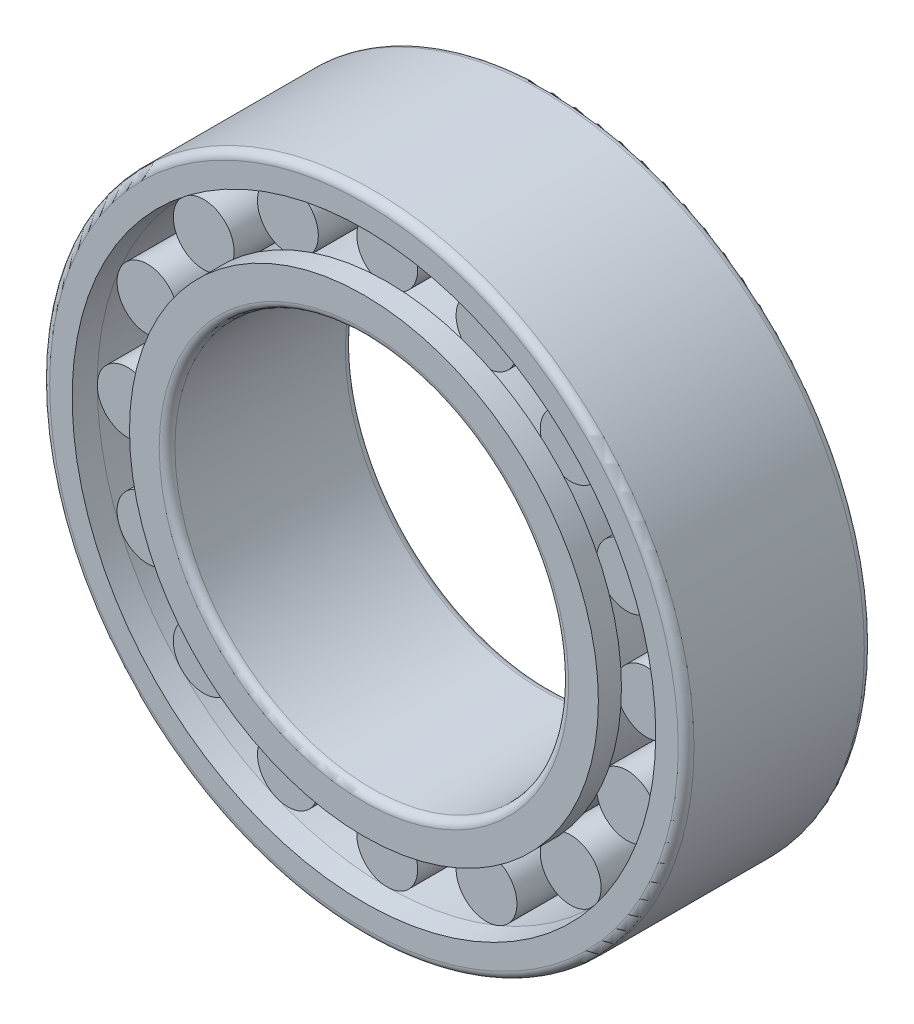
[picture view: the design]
ISO-10303-21;
HEADER;
FILE_DESCRIPTION(('STEP AP214'),'2;1');
FILE_NAME('part.step','',(''),(''),'','','');
FILE_SCHEMA(('AUTOMOTIVE_DESIGN { 1 0 10303 214 1 1 1 1 }'));
ENDSEC;
DATA;
#1=APPLICATION_CONTEXT('core data for automotive mechanical design processes');
#2=APPLICATION_PROTOCOL_DEFINITION('international standard','automotive_design',2000,#1);
#3=PRODUCT_CONTEXT('',#1,'mechanical');
#4=PRODUCT('Part','Part','',(#3));
#5=PRODUCT_RELATED_PRODUCT_CATEGORY('part','',(#4));
#6=PRODUCT_DEFINITION_FORMATION('','',#4);
#7=PRODUCT_DEFINITION_CONTEXT('part definition',#1,'design');
#8=PRODUCT_DEFINITION('design','',#6,#7);
#9=PRODUCT_DEFINITION_SHAPE('','',#8);
#10=(LENGTH_UNIT() NAMED_UNIT(*) SI_UNIT(.MILLI.,.METRE.));
#11=(NAMED_UNIT(*) PLANE_ANGLE_UNIT() SI_UNIT($,.RADIAN.));
#12=(NAMED_UNIT(*) SI_UNIT($,.STERADIAN.) SOLID_ANGLE_UNIT());
#13=UNCERTAINTY_MEASURE_WITH_UNIT(LENGTH_MEASURE(1.E-05),#10,'distance_accuracy_value','');
#14=(GEOMETRIC_REPRESENTATION_CONTEXT(3) GLOBAL_UNCERTAINTY_ASSIGNED_CONTEXT((#13)) GLOBAL_UNIT_ASSIGNED_CONTEXT((#10,
#11,#12)) REPRESENTATION_CONTEXT('',''));
#15=CARTESIAN_POINT('',(0.,0.,0.));
#16=DIRECTION('',(0.,0.,1.));
#17=DIRECTION('',(1.,0.,0.));
#18=AXIS2_PLACEMENT_3D('',#15,#16,#17);
#19=CARTESIAN_POINT('',(0.,0.,50.3916163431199));
#20=DIRECTION('',(0.,0.,1.));
#21=DIRECTION('',(1.,0.,0.));
#22=AXIS2_PLACEMENT_3D('',#19,#20,#21);
#23=CYLINDRICAL_SURFACE('',#22,40.48);
#24=DIRECTION('',(0.,0.,1.));
#25=VECTOR('',#24,1.);
#26=CARTESIAN_POINT('',(-15.8921876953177,37.2299445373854,5.52499999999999));
#27=LINE('',#26,#25);
#28=CARTESIAN_POINT('',(-15.8921876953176,37.2299445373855,9.74999999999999));
#29=VERTEX_POINT('',#28);
#30=CARTESIAN_POINT('',(-15.8921876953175,37.2299445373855,1.29999999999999));
#31=VERTEX_POINT('',#30);
#32=EDGE_CURVE('E860',#29,#31,#27,.F.);
#33=ORIENTED_EDGE('',*,*,#32,.F.);
#34=CARTESIAN_POINT('',(0.,0.,9.74999999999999));
#35=DIRECTION('',(0.,0.,-1.));
#36=DIRECTION('',(-1.,0.,0.));
#37=AXIS2_PLACEMENT_3D('',#34,#35,#36);
#38=CIRCLE('',#37,40.48);
#39=CARTESIAN_POINT('',(-15.0880725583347,37.5630199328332,9.74999999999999));
#40=VERTEX_POINT('',#39);
#41=EDGE_CURVE('E862',#40,#29,#38,.F.);
#42=ORIENTED_EDGE('',*,*,#41,.F.);
#43=DIRECTION('',(0.,0.,1.));
#44=VECTOR('',#43,1.);
#45=CARTESIAN_POINT('',(-15.0880725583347,37.5630199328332,5.52499999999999));
#46=LINE('',#45,#44);
#47=CARTESIAN_POINT('',(-15.0880725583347,37.5630199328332,1.29999999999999));
#48=VERTEX_POINT('',#47);
#49=EDGE_CURVE('E858',#48,#40,#46,.T.);
#50=ORIENTED_EDGE('',*,*,#49,.F.);
#51=CARTESIAN_POINT('',(0.,0.,1.29999999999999));
#52=DIRECTION('',(0.,0.,1.));
#53=DIRECTION('',(1.,0.,0.));
#54=AXIS2_PLACEMENT_3D('',#51,#52,#53);
#55=CIRCLE('',#54,40.48);
#56=EDGE_CURVE('E865',#31,#48,#55,.F.);
#57=ORIENTED_EDGE('',*,*,#56,.F.);
#58=EDGE_LOOP('',(#33,#42,#50,#57));
#59=FACE_BOUND('',#58,.T.);
#60=DIRECTION('',(0.,0.,1.));
#61=VECTOR('',#60,1.);
#62=CARTESIAN_POINT('',(-28.9297499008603,28.3143068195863,5.52499999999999));
#63=LINE('',#62,#61);
#64=CARTESIAN_POINT('',(-28.9297499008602,28.3143068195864,9.74999999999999));
#65=VERTEX_POINT('',#64);
#66=CARTESIAN_POINT('',(-28.9297499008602,28.3143068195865,1.29999999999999));
#67=VERTEX_POINT('',#66);
#68=EDGE_CURVE('E898',#65,#67,#63,.F.);
#69=ORIENTED_EDGE('',*,*,#68,.F.);
#70=CARTESIAN_POINT('',(0.,0.,9.74999999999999));
#71=DIRECTION('',(0.,0.,-1.));
#72=DIRECTION('',(-1.,0.,0.));
#73=AXIS2_PLACEMENT_3D('',#70,#71,#72);
#74=CIRCLE('',#73,40.48);
#75=CARTESIAN_POINT('',(-28.3143068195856,28.929749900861,9.74999999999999));
#76=VERTEX_POINT('',#75);
#77=EDGE_CURVE('E901',#76,#65,#74,.F.);
#78=ORIENTED_EDGE('',*,*,#77,.F.);
#79=DIRECTION('',(0.,0.,1.));
#80=VECTOR('',#79,1.);
#81=CARTESIAN_POINT('',(-28.3143068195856,28.929749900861,5.52499999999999));
#82=LINE('',#81,#80);
#83=CARTESIAN_POINT('',(-28.3143068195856,28.929749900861,1.29999999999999));
#84=VERTEX_POINT('',#83);
#85=EDGE_CURVE('E899',#84,#76,#82,.T.);
#86=ORIENTED_EDGE('',*,*,#85,.F.);
#87=CARTESIAN_POINT('',(0.,0.,1.29999999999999));
#88=DIRECTION('',(0.,0.,1.));
#89=DIRECTION('',(1.,0.,0.));
#90=AXIS2_PLACEMENT_3D('',#87,#88,#89);
#91=CIRCLE('',#90,40.48);
#92=EDGE_CURVE('E904',#67,#84,#91,.F.);
#93=ORIENTED_EDGE('',*,*,#92,.F.);
#94=EDGE_LOOP('',(#69,#78,#86,#93));
#95=FACE_BOUND('',#94,.T.);
#96=DIRECTION('',(0.,0.,1.));
#97=VECTOR('',#96,1.);
#98=CARTESIAN_POINT('',(-37.5630199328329,15.0880725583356,5.52499999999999));
#99=LINE('',#98,#97);
#100=CARTESIAN_POINT('',(-37.5630199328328,15.0880725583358,9.74999999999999));
#101=VERTEX_POINT('',#100);
#102=CARTESIAN_POINT('',(-37.5630199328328,15.0880725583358,1.29999999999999));
#103=VERTEX_POINT('',#102);
#104=EDGE_CURVE('E939',#101,#103,#99,.F.);
#105=ORIENTED_EDGE('',*,*,#104,.F.);
#106=CARTESIAN_POINT('',(0.,0.,9.74999999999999));
#107=DIRECTION('',(0.,0.,-1.));
#108=DIRECTION('',(-1.,0.,0.));
#109=AXIS2_PLACEMENT_3D('',#106,#107,#108);
#110=CIRCLE('',#109,40.48);
#111=CARTESIAN_POINT('',(-37.229944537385,15.8921876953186,9.74999999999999));
#112=VERTEX_POINT('',#111);
#113=EDGE_CURVE('E944',#112,#101,#110,.F.);
#114=ORIENTED_EDGE('',*,*,#113,.F.);
#115=DIRECTION('',(0.,0.,1.));
#116=VECTOR('',#115,1.);
#117=CARTESIAN_POINT('',(-37.229944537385,15.8921876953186,5.52499999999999));
#118=LINE('',#117,#116);
#119=CARTESIAN_POINT('',(-37.229944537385,15.8921876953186,1.29999999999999));
#120=VERTEX_POINT('',#119);
#121=EDGE_CURVE('E938',#120,#112,#118,.T.);
#122=ORIENTED_EDGE('',*,*,#121,.F.);
#123=CARTESIAN_POINT('',(0.,0.,1.29999999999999));
#124=DIRECTION('',(0.,0.,1.));
#125=DIRECTION('',(1.,0.,0.));
#126=AXIS2_PLACEMENT_3D('',#123,#124,#125);
#127=CIRCLE('',#126,40.48);
#128=EDGE_CURVE('E945',#103,#120,#127,.F.);
#129=ORIENTED_EDGE('',*,*,#128,.F.);
#130=EDGE_LOOP('',(#105,#114,#122,#129));
#131=FACE_BOUND('',#130,.T.);
#132=DIRECTION('',(0.,0.,1.));
#133=VECTOR('',#132,1.);
#134=CARTESIAN_POINT('',(-40.4776606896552,-0.435183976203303,5.52499999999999));
#135=LINE('',#134,#133);
#136=CARTESIAN_POINT('',(-40.4776606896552,-0.435183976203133,9.74999999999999));
#137=VERTEX_POINT('',#136);
#138=CARTESIAN_POINT('',(-40.4776606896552,-0.435183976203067,1.29999999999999));
#139=VERTEX_POINT('',#138);
#140=EDGE_CURVE('E980',#137,#139,#135,.F.);
#141=ORIENTED_EDGE('',*,*,#140,.F.);
#142=CARTESIAN_POINT('',(0.,0.,9.74999999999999));
#143=DIRECTION('',(0.,0.,-1.));
#144=DIRECTION('',(-1.,0.,0.));
#145=AXIS2_PLACEMENT_3D('',#142,#143,#144);
#146=CIRCLE('',#145,40.48);
#147=CARTESIAN_POINT('',(-40.4776606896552,0.435183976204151,9.74999999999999));
#148=VERTEX_POINT('',#147);
#149=EDGE_CURVE('E983',#148,#137,#146,.F.);
#150=ORIENTED_EDGE('',*,*,#149,.F.);
#151=DIRECTION('',(0.,0.,1.));
#152=VECTOR('',#151,1.);
#153=CARTESIAN_POINT('',(-40.4776606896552,0.43518397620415,5.52499999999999));
#154=LINE('',#153,#152);
#155=CARTESIAN_POINT('',(-40.4776606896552,0.43518397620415,1.29999999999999));
#156=VERTEX_POINT('',#155);
#157=EDGE_CURVE('E978',#156,#148,#154,.T.);
#158=ORIENTED_EDGE('',*,*,#157,.F.);
#159=CARTESIAN_POINT('',(0.,0.,1.29999999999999));
#160=DIRECTION('',(0.,0.,1.));
#161=DIRECTION('',(1.,0.,0.));
#162=AXIS2_PLACEMENT_3D('',#159,#160,#161);
#163=CIRCLE('',#162,40.48);
#164=EDGE_CURVE('E985',#139,#156,#163,.F.);
#165=ORIENTED_EDGE('',*,*,#164,.F.);
#166=EDGE_LOOP('',(#141,#150,#158,#165));
#167=FACE_BOUND('',#166,.T.);
#168=DIRECTION('',(0.,0.,1.));
#169=VECTOR('',#168,1.);
#170=CARTESIAN_POINT('',(-37.2299445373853,-15.8921876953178,5.52499999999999));
#171=LINE('',#170,#169);
#172=CARTESIAN_POINT('',(-37.2299445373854,-15.8921876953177,9.74999999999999));
#173=VERTEX_POINT('',#172);
#174=CARTESIAN_POINT('',(-37.2299445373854,-15.8921876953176,1.29999999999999));
#175=VERTEX_POINT('',#174);
#176=EDGE_CURVE('E1017',#173,#175,#171,.F.);
#177=ORIENTED_EDGE('',*,*,#176,.F.);
#178=CARTESIAN_POINT('',(0.,0.,9.74999999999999));
#179=DIRECTION('',(0.,0.,-1.));
#180=DIRECTION('',(-1.,0.,0.));
#181=AXIS2_PLACEMENT_3D('',#178,#179,#180);
#182=CIRCLE('',#181,40.48);
#183=CARTESIAN_POINT('',(-37.5630199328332,-15.0880725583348,9.74999999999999));
#184=VERTEX_POINT('',#183);
#185=EDGE_CURVE('E1024',#184,#173,#182,.F.);
#186=ORIENTED_EDGE('',*,*,#185,.F.);
#187=DIRECTION('',(0.,0.,1.));
#188=VECTOR('',#187,1.);
#189=CARTESIAN_POINT('',(-37.5630199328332,-15.0880725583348,5.52499999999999));
#190=LINE('',#189,#188);
#191=CARTESIAN_POINT('',(-37.5630199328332,-15.0880725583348,1.29999999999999));
#192=VERTEX_POINT('',#191);
#193=EDGE_CURVE('E1016',#192,#184,#190,.T.);
#194=ORIENTED_EDGE('',*,*,#193,.F.);
#195=CARTESIAN_POINT('',(0.,0.,1.29999999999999));
#196=DIRECTION('',(0.,0.,1.));
#197=DIRECTION('',(1.,0.,0.));
#198=AXIS2_PLACEMENT_3D('',#195,#196,#197);
#199=CIRCLE('',#198,40.48);
#200=EDGE_CURVE('E1025',#175,#192,#199,.F.);
#201=ORIENTED_EDGE('',*,*,#200,.F.);
#202=EDGE_LOOP('',(#177,#186,#194,#201));
#203=FACE_BOUND('',#202,.T.);
#204=DIRECTION('',(0.,0.,1.));
#205=VECTOR('',#204,1.);
#206=CARTESIAN_POINT('',(-28.3143068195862,-28.9297499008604,5.52499999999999));
#207=LINE('',#206,#205);
#208=CARTESIAN_POINT('',(-28.3143068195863,-28.9297499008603,9.74999999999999));
#209=VERTEX_POINT('',#208);
#210=CARTESIAN_POINT('',(-28.3143068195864,-28.9297499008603,1.29999999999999));
#211=VERTEX_POINT('',#210);
#212=EDGE_CURVE('E1059',#209,#211,#207,.F.);
#213=ORIENTED_EDGE('',*,*,#212,.F.);
#214=CARTESIAN_POINT('',(0.,0.,9.74999999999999));
#215=DIRECTION('',(0.,0.,-1.));
#216=DIRECTION('',(-1.,0.,0.));
#217=AXIS2_PLACEMENT_3D('',#214,#215,#216);
#218=CIRCLE('',#217,40.48);
#219=CARTESIAN_POINT('',(-28.9297499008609,-28.3143068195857,9.74999999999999));
#220=VERTEX_POINT('',#219);
#221=EDGE_CURVE('E1063',#220,#209,#218,.F.);
#222=ORIENTED_EDGE('',*,*,#221,.F.);
#223=DIRECTION('',(0.,0.,1.));
#224=VECTOR('',#223,1.);
#225=CARTESIAN_POINT('',(-28.9297499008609,-28.3143068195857,5.52499999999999));
#226=LINE('',#225,#224);
#227=CARTESIAN_POINT('',(-28.9297499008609,-28.3143068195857,1.29999999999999));
#228=VERTEX_POINT('',#227);
#229=EDGE_CURVE('E1057',#228,#220,#226,.T.);
#230=ORIENTED_EDGE('',*,*,#229,.F.);
#231=CARTESIAN_POINT('',(0.,0.,1.29999999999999));
#232=DIRECTION('',(0.,0.,1.));
#233=DIRECTION('',(1.,0.,0.));
#234=AXIS2_PLACEMENT_3D('',#231,#232,#233);
#235=CIRCLE('',#234,40.48);
#236=EDGE_CURVE('E1065',#211,#228,#235,.F.);
#237=ORIENTED_EDGE('',*,*,#236,.F.);
#238=EDGE_LOOP('',(#213,#222,#230,#237));
#239=FACE_BOUND('',#238,.T.);
#240=DIRECTION('',(0.,0.,1.));
#241=VECTOR('',#240,1.);
#242=CARTESIAN_POINT('',(-15.0880725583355,-37.5630199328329,5.52499999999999));
#243=LINE('',#242,#241);
#244=CARTESIAN_POINT('',(-15.0880725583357,-37.5630199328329,9.74999999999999));
#245=VERTEX_POINT('',#244);
#246=CARTESIAN_POINT('',(-15.0880725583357,-37.5630199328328,1.29999999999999));
#247=VERTEX_POINT('',#246);
#248=EDGE_CURVE('E1097',#245,#247,#243,.F.);
#249=ORIENTED_EDGE('',*,*,#248,.F.);
#250=CARTESIAN_POINT('',(0.,0.,9.74999999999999));
#251=DIRECTION('',(0.,0.,-1.));
#252=DIRECTION('',(-1.,0.,0.));
#253=AXIS2_PLACEMENT_3D('',#250,#251,#252);
#254=CIRCLE('',#253,40.48);
#255=CARTESIAN_POINT('',(-15.8921876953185,-37.229944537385,9.74999999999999));
#256=VERTEX_POINT('',#255);
#257=EDGE_CURVE('E1104',#256,#245,#254,.F.);
#258=ORIENTED_EDGE('',*,*,#257,.F.);
#259=DIRECTION('',(0.,0.,1.));
#260=VECTOR('',#259,1.);
#261=CARTESIAN_POINT('',(-15.8921876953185,-37.229944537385,5.52499999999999));
#262=LINE('',#261,#260);
#263=CARTESIAN_POINT('',(-15.8921876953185,-37.229944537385,1.29999999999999));
#264=VERTEX_POINT('',#263);
#265=EDGE_CURVE('E1096',#264,#256,#262,.T.);
#266=ORIENTED_EDGE('',*,*,#265,.F.);
#267=CARTESIAN_POINT('',(0.,0.,1.29999999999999));
#268=DIRECTION('',(0.,0.,1.));
#269=DIRECTION('',(1.,0.,0.));
#270=AXIS2_PLACEMENT_3D('',#267,#268,#269);
#271=CIRCLE('',#270,40.48);
#272=EDGE_CURVE('E1105',#247,#264,#271,.F.);
#273=ORIENTED_EDGE('',*,*,#272,.F.);
#274=EDGE_LOOP('',(#249,#258,#266,#273));
#275=FACE_BOUND('',#274,.T.);
#276=DIRECTION('',(0.,0.,1.));
#277=VECTOR('',#276,1.);
#278=CARTESIAN_POINT('',(0.435183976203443,-40.4776606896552,5.52499999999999));
#279=LINE('',#278,#277);
#280=CARTESIAN_POINT('',(0.435183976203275,-40.4776606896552,9.74999999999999));
#281=VERTEX_POINT('',#280);
#282=CARTESIAN_POINT('',(0.435183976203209,-40.4776606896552,1.29999999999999));
#283=VERTEX_POINT('',#282);
#284=EDGE_CURVE('E1136',#281,#283,#279,.F.);
#285=ORIENTED_EDGE('',*,*,#284,.F.);
#286=CARTESIAN_POINT('',(0.,0.,9.74999999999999));
#287=DIRECTION('',(0.,0.,-1.));
#288=DIRECTION('',(-1.,0.,0.));
#289=AXIS2_PLACEMENT_3D('',#286,#287,#288);
#290=CIRCLE('',#289,40.48);
#291=CARTESIAN_POINT('',(-0.43518397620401,-40.4776606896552,9.74999999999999));
#292=VERTEX_POINT('',#291);
#293=EDGE_CURVE('E1142',#292,#281,#290,.F.);
#294=ORIENTED_EDGE('',*,*,#293,.F.);
#295=DIRECTION('',(0.,0.,1.));
#296=VECTOR('',#295,1.);
#297=CARTESIAN_POINT('',(-0.435183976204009,-40.4776606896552,5.52499999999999));
#298=LINE('',#297,#296);
#299=CARTESIAN_POINT('',(-0.435183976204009,-40.4776606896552,1.29999999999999));
#300=VERTEX_POINT('',#299);
#301=EDGE_CURVE('E1137',#300,#292,#298,.T.);
#302=ORIENTED_EDGE('',*,*,#301,.F.);
#303=CARTESIAN_POINT('',(0.,0.,1.29999999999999));
#304=DIRECTION('',(0.,0.,1.));
#305=DIRECTION('',(1.,0.,0.));
#306=AXIS2_PLACEMENT_3D('',#303,#304,#305);
#307=CIRCLE('',#306,40.48);
#308=EDGE_CURVE('E1141',#283,#300,#307,.F.);
#309=ORIENTED_EDGE('',*,*,#308,.F.);
#310=EDGE_LOOP('',(#285,#294,#302,#309));
#311=FACE_BOUND('',#310,.T.);
#312=DIRECTION('',(0.,0.,1.));
#313=VECTOR('',#312,1.);
#314=CARTESIAN_POINT('',(15.892187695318,-37.2299445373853,5.52499999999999));
#315=LINE('',#314,#313);
#316=CARTESIAN_POINT('',(15.8921876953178,-37.2299445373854,9.74999999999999));
#317=VERTEX_POINT('',#316);
#318=CARTESIAN_POINT('',(15.8921876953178,-37.2299445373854,1.29999999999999));
#319=VERTEX_POINT('',#318);
#320=EDGE_CURVE('E1178',#317,#319,#315,.F.);
#321=ORIENTED_EDGE('',*,*,#320,.F.);
#322=CARTESIAN_POINT('',(0.,0.,9.74999999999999));
#323=DIRECTION('',(0.,0.,-1.));
#324=DIRECTION('',(-1.,0.,0.));
#325=AXIS2_PLACEMENT_3D('',#322,#323,#324);
#326=CIRCLE('',#325,40.48);
#327=CARTESIAN_POINT('',(15.088072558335,-37.5630199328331,9.74999999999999));
#328=VERTEX_POINT('',#327);
#329=EDGE_CURVE('E1183',#328,#317,#326,.F.);
#330=ORIENTED_EDGE('',*,*,#329,.F.);
#331=DIRECTION('',(0.,0.,1.));
#332=VECTOR('',#331,1.);
#333=CARTESIAN_POINT('',(15.088072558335,-37.5630199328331,5.52499999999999));
#334=LINE('',#333,#332);
#335=CARTESIAN_POINT('',(15.088072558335,-37.5630199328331,1.29999999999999));
#336=VERTEX_POINT('',#335);
#337=EDGE_CURVE('E1176',#336,#328,#334,.T.);
#338=ORIENTED_EDGE('',*,*,#337,.F.);
#339=CARTESIAN_POINT('',(0.,0.,1.29999999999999));
#340=DIRECTION('',(0.,0.,1.));
#341=DIRECTION('',(1.,0.,0.));
#342=AXIS2_PLACEMENT_3D('',#339,#340,#341);
#343=CIRCLE('',#342,40.48);
#344=EDGE_CURVE('E1185',#319,#336,#343,.F.);
#345=ORIENTED_EDGE('',*,*,#344,.F.);
#346=EDGE_LOOP('',(#321,#330,#338,#345));
#347=FACE_BOUND('',#346,.T.);
#348=DIRECTION('',(0.,0.,1.));
#349=VECTOR('',#348,1.);
#350=CARTESIAN_POINT('',(28.9297499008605,-28.3143068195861,5.52499999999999));
#351=LINE('',#350,#349);
#352=CARTESIAN_POINT('',(28.9297499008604,-28.3143068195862,9.74999999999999));
#353=VERTEX_POINT('',#352);
#354=CARTESIAN_POINT('',(28.9297499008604,-28.3143068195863,1.29999999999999));
#355=VERTEX_POINT('',#354);
#356=EDGE_CURVE('E1218',#353,#355,#351,.F.);
#357=ORIENTED_EDGE('',*,*,#356,.F.);
#358=CARTESIAN_POINT('',(0.,0.,9.74999999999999));
#359=DIRECTION('',(0.,0.,-1.));
#360=DIRECTION('',(-1.,0.,0.));
#361=AXIS2_PLACEMENT_3D('',#358,#359,#360);
#362=CIRCLE('',#361,40.48);
#363=CARTESIAN_POINT('',(28.3143068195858,-28.9297499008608,9.74999999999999));
#364=VERTEX_POINT('',#363);
#365=EDGE_CURVE('E1222',#364,#353,#362,.F.);
#366=ORIENTED_EDGE('',*,*,#365,.F.);
#367=DIRECTION('',(0.,0.,1.));
#368=VECTOR('',#367,1.);
#369=CARTESIAN_POINT('',(28.3143068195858,-28.9297499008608,5.52499999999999));
#370=LINE('',#369,#368);
#371=CARTESIAN_POINT('',(28.3143068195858,-28.9297499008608,1.29999999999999));
#372=VERTEX_POINT('',#371);
#373=EDGE_CURVE('E1219',#372,#364,#370,.T.);
#374=ORIENTED_EDGE('',*,*,#373,.F.);
#375=CARTESIAN_POINT('',(0.,0.,1.29999999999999));
#376=DIRECTION('',(0.,0.,1.));
#377=DIRECTION('',(1.,0.,0.));
#378=AXIS2_PLACEMENT_3D('',#375,#376,#377);
#379=CIRCLE('',#378,40.48);
#380=EDGE_CURVE('E1221',#355,#372,#379,.F.);
#381=ORIENTED_EDGE('',*,*,#380,.F.);
#382=EDGE_LOOP('',(#357,#366,#374,#381));
#383=FACE_BOUND('',#382,.T.);
#384=DIRECTION('',(0.,0.,1.));
#385=VECTOR('',#384,1.);
#386=CARTESIAN_POINT('',(37.563019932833,-15.0880725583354,5.52499999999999));
#387=LINE('',#386,#385);
#388=CARTESIAN_POINT('',(37.563019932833,-15.0880725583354,9.74999999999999));
#389=VERTEX_POINT('',#388);
#390=CARTESIAN_POINT('',(37.5630199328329,-15.0880725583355,1.29999999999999));
#391=VERTEX_POINT('',#390);
#392=EDGE_CURVE('E1256',#389,#391,#387,.F.);
#393=ORIENTED_EDGE('',*,*,#392,.F.);
#394=CARTESIAN_POINT('',(0.,0.,9.74999999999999));
#395=DIRECTION('',(0.,0.,-1.));
#396=DIRECTION('',(-1.,0.,0.));
#397=AXIS2_PLACEMENT_3D('',#394,#395,#396);
#398=CIRCLE('',#397,40.48);
#399=CARTESIAN_POINT('',(37.2299445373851,-15.8921876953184,9.74999999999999));
#400=VERTEX_POINT('',#399);
#401=EDGE_CURVE('E1263',#400,#389,#398,.F.);
#402=ORIENTED_EDGE('',*,*,#401,.F.);
#403=DIRECTION('',(0.,0.,1.));
#404=VECTOR('',#403,1.);
#405=CARTESIAN_POINT('',(37.2299445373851,-15.8921876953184,5.52499999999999));
#406=LINE('',#405,#404);
#407=CARTESIAN_POINT('',(37.2299445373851,-15.8921876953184,1.29999999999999));
#408=VERTEX_POINT('',#407);
#409=EDGE_CURVE('E1257',#408,#400,#406,.T.);
#410=ORIENTED_EDGE('',*,*,#409,.F.);
#411=CARTESIAN_POINT('',(0.,0.,1.29999999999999));
#412=DIRECTION('',(0.,0.,1.));
#413=DIRECTION('',(1.,0.,0.));
#414=AXIS2_PLACEMENT_3D('',#411,#412,#413);
#415=CIRCLE('',#414,40.48);
#416=EDGE_CURVE('E1265',#391,#408,#415,.F.);
#417=ORIENTED_EDGE('',*,*,#416,.F.);
#418=EDGE_LOOP('',(#393,#402,#410,#417));
#419=FACE_BOUND('',#418,.T.);
#420=DIRECTION('',(0.,0.,1.));
#421=VECTOR('',#420,1.);
#422=CARTESIAN_POINT('',(40.4776606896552,0.435183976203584,5.52499999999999));
#423=LINE('',#422,#421);
#424=CARTESIAN_POINT('',(40.4776606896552,0.435183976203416,9.74999999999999));
#425=VERTEX_POINT('',#424);
#426=CARTESIAN_POINT('',(40.4776606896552,0.43518397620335,1.29999999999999));
#427=VERTEX_POINT('',#426);
#428=EDGE_CURVE('E1298',#425,#427,#423,.F.);
#429=ORIENTED_EDGE('',*,*,#428,.F.);
#430=CARTESIAN_POINT('',(0.,0.,9.74999999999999));
#431=DIRECTION('',(0.,0.,-1.));
#432=DIRECTION('',(-1.,0.,0.));
#433=AXIS2_PLACEMENT_3D('',#430,#431,#432);
#434=CIRCLE('',#433,40.48);
#435=CARTESIAN_POINT('',(40.4776606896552,-0.435183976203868,9.74999999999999));
#436=VERTEX_POINT('',#435);
#437=EDGE_CURVE('E1301',#436,#425,#434,.F.);
#438=ORIENTED_EDGE('',*,*,#437,.F.);
#439=DIRECTION('',(0.,0.,1.));
#440=VECTOR('',#439,1.);
#441=CARTESIAN_POINT('',(40.4776606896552,-0.435183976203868,5.52499999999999));
#442=LINE('',#441,#440);
#443=CARTESIAN_POINT('',(40.4776606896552,-0.435183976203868,1.29999999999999));
#444=VERTEX_POINT('',#443);
#445=EDGE_CURVE('E1299',#444,#436,#442,.T.);
#446=ORIENTED_EDGE('',*,*,#445,.F.);
#447=CARTESIAN_POINT('',(0.,0.,1.29999999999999));
#448=DIRECTION('',(0.,0.,1.));
#449=DIRECTION('',(1.,0.,0.));
#450=AXIS2_PLACEMENT_3D('',#447,#448,#449);
#451=CIRCLE('',#450,40.48);
#452=EDGE_CURVE('E1304',#427,#444,#451,.F.);
#453=ORIENTED_EDGE('',*,*,#452,.F.);
#454=EDGE_LOOP('',(#429,#438,#446,#453));
#455=FACE_BOUND('',#454,.T.);
#456=DIRECTION('',(0.,0.,1.));
#457=VECTOR('',#456,1.);
#458=CARTESIAN_POINT('',(37.2299445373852,15.8921876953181,5.52499999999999));
#459=LINE('',#458,#457);
#460=CARTESIAN_POINT('',(37.2299445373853,15.8921876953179,9.74999999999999));
#461=VERTEX_POINT('',#460);
#462=CARTESIAN_POINT('',(37.2299445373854,15.8921876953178,1.29999999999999));
#463=VERTEX_POINT('',#462);
#464=EDGE_CURVE('E1336',#461,#463,#459,.F.);
#465=ORIENTED_EDGE('',*,*,#464,.F.);
#466=CARTESIAN_POINT('',(0.,0.,9.74999999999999));
#467=DIRECTION('',(0.,0.,-1.));
#468=DIRECTION('',(-1.,0.,0.));
#469=AXIS2_PLACEMENT_3D('',#466,#467,#468);
#470=CIRCLE('',#469,40.48);
#471=CARTESIAN_POINT('',(37.5630199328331,15.0880725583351,9.74999999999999));
#472=VERTEX_POINT('',#471);
#473=EDGE_CURVE('E1342',#472,#461,#470,.F.);
#474=ORIENTED_EDGE('',*,*,#473,.F.);
#475=DIRECTION('',(0.,0.,1.));
#476=VECTOR('',#475,1.);
#477=CARTESIAN_POINT('',(37.5630199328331,15.0880725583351,5.52499999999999));
#478=LINE('',#477,#476);
#479=CARTESIAN_POINT('',(37.5630199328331,15.0880725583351,1.29999999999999));
#480=VERTEX_POINT('',#479);
#481=EDGE_CURVE('E1337',#480,#472,#478,.T.);
#482=ORIENTED_EDGE('',*,*,#481,.F.);
#483=CARTESIAN_POINT('',(0.,0.,1.29999999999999));
#484=DIRECTION('',(0.,0.,1.));
#485=DIRECTION('',(1.,0.,0.));
#486=AXIS2_PLACEMENT_3D('',#483,#484,#485);
#487=CIRCLE('',#486,40.48);
#488=EDGE_CURVE('E1341',#463,#480,#487,.F.);
#489=ORIENTED_EDGE('',*,*,#488,.F.);
#490=EDGE_LOOP('',(#465,#474,#482,#489));
#491=FACE_BOUND('',#490,.T.);
#492=DIRECTION('',(0.,0.,1.));
#493=VECTOR('',#492,1.);
#494=CARTESIAN_POINT('',(28.314306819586,28.9297499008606,5.52499999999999));
#495=LINE('',#494,#493);
#496=CARTESIAN_POINT('',(28.3143068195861,28.9297499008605,9.74999999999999));
#497=VERTEX_POINT('',#496);
#498=CARTESIAN_POINT('',(28.3143068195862,28.9297499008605,1.29999999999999));
#499=VERTEX_POINT('',#498);
#500=EDGE_CURVE('E1380',#497,#499,#495,.F.);
#501=ORIENTED_EDGE('',*,*,#500,.F.);
#502=CARTESIAN_POINT('',(0.,0.,9.74999999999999));
#503=DIRECTION('',(0.,0.,-1.));
#504=DIRECTION('',(-1.,0.,0.));
#505=AXIS2_PLACEMENT_3D('',#502,#503,#504);
#506=CIRCLE('',#505,40.48);
#507=CARTESIAN_POINT('',(28.9297499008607,28.3143068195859,9.74999999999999));
#508=VERTEX_POINT('',#507);
#509=EDGE_CURVE('E1384',#508,#497,#506,.F.);
#510=ORIENTED_EDGE('',*,*,#509,.F.);
#511=DIRECTION('',(0.,0.,1.));
#512=VECTOR('',#511,1.);
#513=CARTESIAN_POINT('',(28.9297499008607,28.3143068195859,5.52499999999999));
#514=LINE('',#513,#512);
#515=CARTESIAN_POINT('',(28.9297499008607,28.3143068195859,1.29999999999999));
#516=VERTEX_POINT('',#515);
#517=EDGE_CURVE('E1378',#516,#508,#514,.T.);
#518=ORIENTED_EDGE('',*,*,#517,.F.);
#519=CARTESIAN_POINT('',(0.,0.,1.29999999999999));
#520=DIRECTION('',(0.,0.,1.));
#521=DIRECTION('',(1.,0.,0.));
#522=AXIS2_PLACEMENT_3D('',#519,#520,#521);
#523=CIRCLE('',#522,40.48);
#524=EDGE_CURVE('E1382',#499,#516,#523,.F.);
#525=ORIENTED_EDGE('',*,*,#524,.F.);
#526=EDGE_LOOP('',(#501,#510,#518,#525));
#527=FACE_BOUND('',#526,.T.);
#528=DIRECTION('',(0.,0.,1.));
#529=VECTOR('',#528,1.);
#530=CARTESIAN_POINT('',(15.0880725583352,37.563019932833,5.52499999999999));
#531=LINE('',#530,#529);
#532=CARTESIAN_POINT('',(15.0880725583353,37.563019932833,9.74999999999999));
#533=VERTEX_POINT('',#532);
#534=CARTESIAN_POINT('',(15.0880725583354,37.563019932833,1.29999999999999));
#535=VERTEX_POINT('',#534);
#536=EDGE_CURVE('E1418',#533,#535,#531,.F.);
#537=ORIENTED_EDGE('',*,*,#536,.F.);
#538=CARTESIAN_POINT('',(0.,0.,9.74999999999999));
#539=DIRECTION('',(0.,0.,-1.));
#540=DIRECTION('',(-1.,0.,0.));
#541=AXIS2_PLACEMENT_3D('',#538,#539,#540);
#542=CIRCLE('',#541,40.48);
#543=CARTESIAN_POINT('',(15.8921876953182,37.2299445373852,9.74999999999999));
#544=VERTEX_POINT('',#543);
#545=EDGE_CURVE('E1422',#544,#533,#542,.F.);
#546=ORIENTED_EDGE('',*,*,#545,.F.);
#547=DIRECTION('',(0.,0.,1.));
#548=VECTOR('',#547,1.);
#549=CARTESIAN_POINT('',(15.8921876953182,37.2299445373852,5.52499999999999));
#550=LINE('',#549,#548);
#551=CARTESIAN_POINT('',(15.8921876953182,37.2299445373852,1.29999999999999));
#552=VERTEX_POINT('',#551);
#553=EDGE_CURVE('E1419',#552,#544,#550,.T.);
#554=ORIENTED_EDGE('',*,*,#553,.F.);
#555=CARTESIAN_POINT('',(0.,0.,1.29999999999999));
#556=DIRECTION('',(0.,0.,1.));
#557=DIRECTION('',(1.,0.,0.));
#558=AXIS2_PLACEMENT_3D('',#555,#556,#557);
#559=CIRCLE('',#558,40.48);
#560=EDGE_CURVE('E1421',#535,#552,#559,.F.);
#561=ORIENTED_EDGE('',*,*,#560,.F.);
#562=EDGE_LOOP('',(#537,#546,#554,#561));
#563=FACE_BOUND('',#562,.T.);
#564=CARTESIAN_POINT('',(0.,0.,9.74999999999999));
#565=DIRECTION('',(0.,0.,-1.));
#566=DIRECTION('',(-1.,0.,0.));
#567=AXIS2_PLACEMENT_3D('',#564,#565,#566);
#568=CIRCLE('',#567,40.48);
#569=CARTESIAN_POINT('',(-0.435183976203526,40.4776606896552,9.74999999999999));
#570=VERTEX_POINT('',#569);
#571=CARTESIAN_POINT('',(0.435183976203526,40.4776606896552,9.74999999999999));
#572=VERTEX_POINT('',#571);
#573=EDGE_CURVE('E1488',#570,#572,#568,.T.);
#574=ORIENTED_EDGE('',*,*,#573,.T.);
#575=DIRECTION('',(0.,0.,1.));
#576=VECTOR('',#575,1.);
#577=CARTESIAN_POINT('',(0.435183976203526,40.4776606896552,5.52499999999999));
#578=LINE('',#577,#576);
#579=CARTESIAN_POINT('',(0.435183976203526,40.4776606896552,1.29999999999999));
#580=VERTEX_POINT('',#579);
#581=EDGE_CURVE('E1502',#572,#580,#578,.F.);
#582=ORIENTED_EDGE('',*,*,#581,.T.);
#583=CARTESIAN_POINT('',(0.,0.,1.29999999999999));
#584=DIRECTION('',(0.,0.,1.));
#585=DIRECTION('',(1.,0.,0.));
#586=AXIS2_PLACEMENT_3D('',#583,#584,#585);
#587=CIRCLE('',#586,40.48);
#588=CARTESIAN_POINT('',(-0.435183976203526,40.4776606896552,1.29999999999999));
#589=VERTEX_POINT('',#588);
#590=EDGE_CURVE('E1490',#580,#589,#587,.T.);
#591=ORIENTED_EDGE('',*,*,#590,.T.);
#592=DIRECTION('',(0.,0.,1.));
#593=VECTOR('',#592,1.);
#594=CARTESIAN_POINT('',(-0.435183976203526,40.4776606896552,5.52499999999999));
#595=LINE('',#594,#593);
#596=EDGE_CURVE('E1497',#589,#570,#595,.T.);
#597=ORIENTED_EDGE('',*,*,#596,.T.);
#598=EDGE_LOOP('',(#574,#582,#591,#597));
#599=FACE_BOUND('',#598,.T.);
#600=CARTESIAN_POINT('',(0.,0.,9.775));
#601=DIRECTION('',(0.,0.,1.));
#602=DIRECTION('',(1.,0.,0.));
#603=AXIS2_PLACEMENT_3D('',#600,#601,#602);
#604=CIRCLE('',#603,40.48);
#605=CARTESIAN_POINT('',(40.48,0.,9.775));
#606=VERTEX_POINT('',#605);
#607=EDGE_CURVE('E1482',#606,#606,#604,.T.);
#608=ORIENTED_EDGE('',*,*,#607,.T.);
#609=EDGE_LOOP('',(#608));
#610=FACE_BOUND('',#609,.T.);
#611=CARTESIAN_POINT('',(0.,0.,-9.775));
#612=DIRECTION('',(0.,0.,1.));
#613=DIRECTION('',(1.,0.,0.));
#614=AXIS2_PLACEMENT_3D('',#611,#612,#613);
#615=CIRCLE('',#614,40.48);
#616=CARTESIAN_POINT('',(40.48,0.,-9.775));
#617=VERTEX_POINT('',#616);
#618=EDGE_CURVE('E1477',#617,#617,#615,.T.);
#619=ORIENTED_EDGE('',*,*,#618,.F.);
#620=EDGE_LOOP('',(#619));
#621=FACE_BOUND('',#620,.T.);
#622=CARTESIAN_POINT('',(0.,0.,-1.30000000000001));
#623=DIRECTION('',(0.,0.,-1.));
#624=DIRECTION('',(-1.,0.,0.));
#625=AXIS2_PLACEMENT_3D('',#622,#623,#624);
#626=CIRCLE('',#625,40.48);
#627=CARTESIAN_POINT('',(0.435183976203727,40.4776606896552,-1.30000000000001));
#628=VERTEX_POINT('',#627);
#629=CARTESIAN_POINT('',(-0.435183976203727,40.4776606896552,-1.30000000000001));
#630=VERTEX_POINT('',#629);
#631=EDGE_CURVE('E1513',#628,#630,#626,.F.);
#632=ORIENTED_EDGE('',*,*,#631,.F.);
#633=DIRECTION('',(0.,0.,1.));
#634=VECTOR('',#633,1.);
#635=CARTESIAN_POINT('',(0.435183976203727,40.4776606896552,-5.52500000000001));
#636=LINE('',#635,#634);
#637=CARTESIAN_POINT('',(0.435183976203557,40.4776606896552,-9.75000000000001));
#638=VERTEX_POINT('',#637);
#639=EDGE_CURVE('E1509',#638,#628,#636,.T.);
#640=ORIENTED_EDGE('',*,*,#639,.F.);
#641=CARTESIAN_POINT('',(0.,0.,-9.75000000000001));
#642=DIRECTION('',(0.,0.,1.));
#643=DIRECTION('',(1.,0.,0.));
#644=AXIS2_PLACEMENT_3D('',#641,#642,#643);
#645=CIRCLE('',#644,40.48);
#646=CARTESIAN_POINT('',(-0.435183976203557,40.4776606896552,-9.75000000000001));
#647=VERTEX_POINT('',#646);
#648=EDGE_CURVE('E1507',#647,#638,#645,.F.);
#649=ORIENTED_EDGE('',*,*,#648,.F.);
#650=DIRECTION('',(0.,0.,1.));
#651=VECTOR('',#650,1.);
#652=CARTESIAN_POINT('',(-0.435183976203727,40.4776606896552,-5.52500000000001));
#653=LINE('',#652,#651);
#654=EDGE_CURVE('E1515',#630,#647,#653,.F.);
#655=ORIENTED_EDGE('',*,*,#654,.F.);
#656=EDGE_LOOP('',(#632,#640,#649,#655));
#657=FACE_BOUND('',#656,.T.);
#658=CARTESIAN_POINT('',(0.,0.,-1.30000000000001));
#659=DIRECTION('',(0.,0.,-1.));
#660=DIRECTION('',(-1.,0.,0.));
#661=AXIS2_PLACEMENT_3D('',#658,#659,#660);
#662=CIRCLE('',#661,40.48);
#663=CARTESIAN_POINT('',(15.8921876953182,37.2299445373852,-1.30000000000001));
#664=VERTEX_POINT('',#663);
#665=CARTESIAN_POINT('',(15.0880725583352,37.563019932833,-1.30000000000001));
#666=VERTEX_POINT('',#665);
#667=EDGE_CURVE('E1404',#664,#666,#662,.F.);
#668=ORIENTED_EDGE('',*,*,#667,.F.);
#669=DIRECTION('',(0.,0.,1.));
#670=VECTOR('',#669,1.);
#671=CARTESIAN_POINT('',(15.8921876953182,37.2299445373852,-5.52500000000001));
#672=LINE('',#671,#670);
#673=CARTESIAN_POINT('',(15.8921876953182,37.2299445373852,-9.75000000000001));
#674=VERTEX_POINT('',#673);
#675=EDGE_CURVE('E1397',#674,#664,#672,.T.);
#676=ORIENTED_EDGE('',*,*,#675,.F.);
#677=CARTESIAN_POINT('',(0.,0.,-9.75000000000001));
#678=DIRECTION('',(0.,0.,1.));
#679=DIRECTION('',(1.,0.,0.));
#680=AXIS2_PLACEMENT_3D('',#677,#678,#679);
#681=CIRCLE('',#680,40.48);
#682=CARTESIAN_POINT('',(15.0880725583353,37.563019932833,-9.75000000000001));
#683=VERTEX_POINT('',#682);
#684=EDGE_CURVE('E1396',#683,#674,#681,.F.);
#685=ORIENTED_EDGE('',*,*,#684,.F.);
#686=DIRECTION('',(0.,0.,1.));
#687=VECTOR('',#686,1.);
#688=CARTESIAN_POINT('',(15.0880725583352,37.563019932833,-5.52500000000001));
#689=LINE('',#688,#687);
#690=EDGE_CURVE('E1405',#666,#683,#689,.F.);
#691=ORIENTED_EDGE('',*,*,#690,.F.);
#692=EDGE_LOOP('',(#668,#676,#685,#691));
#693=FACE_BOUND('',#692,.T.);
#694=CARTESIAN_POINT('',(0.,0.,-1.30000000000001));
#695=DIRECTION('',(0.,0.,-1.));
#696=DIRECTION('',(-1.,0.,0.));
#697=AXIS2_PLACEMENT_3D('',#694,#695,#696);
#698=CIRCLE('',#697,40.48);
#699=CARTESIAN_POINT('',(28.9297499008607,28.3143068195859,-1.30000000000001));
#700=VERTEX_POINT('',#699);
#701=CARTESIAN_POINT('',(28.314306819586,28.9297499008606,-1.30000000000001));
#702=VERTEX_POINT('',#701);
#703=EDGE_CURVE('E1363',#700,#702,#698,.F.);
#704=ORIENTED_EDGE('',*,*,#703,.F.);
#705=DIRECTION('',(0.,0.,1.));
#706=VECTOR('',#705,1.);
#707=CARTESIAN_POINT('',(28.9297499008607,28.3143068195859,-5.52500000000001));
#708=LINE('',#707,#706);
#709=CARTESIAN_POINT('',(28.9297499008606,28.314306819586,-9.75000000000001));
#710=VERTEX_POINT('',#709);
#711=EDGE_CURVE('E1359',#710,#700,#708,.T.);
#712=ORIENTED_EDGE('',*,*,#711,.F.);
#713=CARTESIAN_POINT('',(0.,0.,-9.75000000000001));
#714=DIRECTION('',(0.,0.,1.));
#715=DIRECTION('',(1.,0.,0.));
#716=AXIS2_PLACEMENT_3D('',#713,#714,#715);
#717=CIRCLE('',#716,40.48);
#718=CARTESIAN_POINT('',(28.3143068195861,28.9297499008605,-9.75000000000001));
#719=VERTEX_POINT('',#718);
#720=EDGE_CURVE('E1357',#719,#710,#717,.F.);
#721=ORIENTED_EDGE('',*,*,#720,.F.);
#722=DIRECTION('',(0.,0.,1.));
#723=VECTOR('',#722,1.);
#724=CARTESIAN_POINT('',(28.314306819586,28.9297499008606,-5.52500000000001));
#725=LINE('',#724,#723);
#726=EDGE_CURVE('E1365',#702,#719,#725,.F.);
#727=ORIENTED_EDGE('',*,*,#726,.F.);
#728=EDGE_LOOP('',(#704,#712,#721,#727));
#729=FACE_BOUND('',#728,.T.);
#730=CARTESIAN_POINT('',(0.,0.,-1.30000000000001));
#731=DIRECTION('',(0.,0.,-1.));
#732=DIRECTION('',(-1.,0.,0.));
#733=AXIS2_PLACEMENT_3D('',#730,#731,#732);
#734=CIRCLE('',#733,40.48);
#735=CARTESIAN_POINT('',(37.5630199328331,15.0880725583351,-1.30000000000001));
#736=VERTEX_POINT('',#735);
#737=CARTESIAN_POINT('',(37.2299445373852,15.8921876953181,-1.30000000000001));
#738=VERTEX_POINT('',#737);
#739=EDGE_CURVE('E1324',#736,#738,#734,.F.);
#740=ORIENTED_EDGE('',*,*,#739,.F.);
#741=DIRECTION('',(0.,0.,1.));
#742=VECTOR('',#741,1.);
#743=CARTESIAN_POINT('',(37.5630199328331,15.0880725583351,-5.52500000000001));
#744=LINE('',#743,#742);
#745=CARTESIAN_POINT('',(37.563019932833,15.0880725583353,-9.75000000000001));
#746=VERTEX_POINT('',#745);
#747=EDGE_CURVE('E1317',#746,#736,#744,.T.);
#748=ORIENTED_EDGE('',*,*,#747,.F.);
#749=CARTESIAN_POINT('',(0.,0.,-9.75000000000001));
#750=DIRECTION('',(0.,0.,1.));
#751=DIRECTION('',(1.,0.,0.));
#752=AXIS2_PLACEMENT_3D('',#749,#750,#751);
#753=CIRCLE('',#752,40.48);
#754=CARTESIAN_POINT('',(37.2299445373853,15.8921876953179,-9.75000000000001));
#755=VERTEX_POINT('',#754);
#756=EDGE_CURVE('E1316',#755,#746,#753,.F.);
#757=ORIENTED_EDGE('',*,*,#756,.F.);
#758=DIRECTION('',(0.,0.,1.));
#759=VECTOR('',#758,1.);
#760=CARTESIAN_POINT('',(37.2299445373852,15.8921876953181,-5.52500000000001));
#761=LINE('',#760,#759);
#762=EDGE_CURVE('E1325',#738,#755,#761,.F.);
#763=ORIENTED_EDGE('',*,*,#762,.F.);
#764=EDGE_LOOP('',(#740,#748,#757,#763));
#765=FACE_BOUND('',#764,.T.);
#766=CARTESIAN_POINT('',(0.,0.,-1.30000000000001));
#767=DIRECTION('',(0.,0.,-1.));
#768=DIRECTION('',(-1.,0.,0.));
#769=AXIS2_PLACEMENT_3D('',#766,#767,#768);
#770=CIRCLE('',#769,40.48);
#771=CARTESIAN_POINT('',(40.4776606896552,-0.435183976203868,-1.30000000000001));
#772=VERTEX_POINT('',#771);
#773=CARTESIAN_POINT('',(40.4776606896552,0.435183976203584,-1.30000000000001));
#774=VERTEX_POINT('',#773);
#775=EDGE_CURVE('E1283',#772,#774,#770,.F.);
#776=ORIENTED_EDGE('',*,*,#775,.F.);
#777=DIRECTION('',(0.,0.,1.));
#778=VECTOR('',#777,1.);
#779=CARTESIAN_POINT('',(40.4776606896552,-0.435183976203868,-5.52500000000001));
#780=LINE('',#779,#778);
#781=CARTESIAN_POINT('',(40.4776606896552,-0.435183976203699,-9.75000000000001));
#782=VERTEX_POINT('',#781);
#783=EDGE_CURVE('E1280',#782,#772,#780,.T.);
#784=ORIENTED_EDGE('',*,*,#783,.F.);
#785=CARTESIAN_POINT('',(0.,0.,-9.75000000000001));
#786=DIRECTION('',(0.,0.,1.));
#787=DIRECTION('',(1.,0.,0.));
#788=AXIS2_PLACEMENT_3D('',#785,#786,#787);
#789=CIRCLE('',#788,40.48);
#790=CARTESIAN_POINT('',(40.4776606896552,0.435183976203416,-9.75000000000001));
#791=VERTEX_POINT('',#790);
#792=EDGE_CURVE('E1278',#791,#782,#789,.F.);
#793=ORIENTED_EDGE('',*,*,#792,.F.);
#794=DIRECTION('',(0.,0.,1.));
#795=VECTOR('',#794,1.);
#796=CARTESIAN_POINT('',(40.4776606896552,0.435183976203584,-5.52500000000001));
#797=LINE('',#796,#795);
#798=EDGE_CURVE('E1285',#774,#791,#797,.F.);
#799=ORIENTED_EDGE('',*,*,#798,.F.);
#800=EDGE_LOOP('',(#776,#784,#793,#799));
#801=FACE_BOUND('',#800,.T.);
#802=CARTESIAN_POINT('',(0.,0.,-1.30000000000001));
#803=DIRECTION('',(0.,0.,-1.));
#804=DIRECTION('',(-1.,0.,0.));
#805=AXIS2_PLACEMENT_3D('',#802,#803,#804);
#806=CIRCLE('',#805,40.48);
#807=CARTESIAN_POINT('',(37.2299445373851,-15.8921876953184,-1.30000000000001));
#808=VERTEX_POINT('',#807);
#809=CARTESIAN_POINT('',(37.563019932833,-15.0880725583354,-1.30000000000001));
#810=VERTEX_POINT('',#809);
#811=EDGE_CURVE('E1244',#808,#810,#806,.F.);
#812=ORIENTED_EDGE('',*,*,#811,.F.);
#813=DIRECTION('',(0.,0.,1.));
#814=VECTOR('',#813,1.);
#815=CARTESIAN_POINT('',(37.2299445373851,-15.8921876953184,-5.52500000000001));
#816=LINE('',#815,#814);
#817=CARTESIAN_POINT('',(37.2299445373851,-15.8921876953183,-9.75000000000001));
#818=VERTEX_POINT('',#817);
#819=EDGE_CURVE('E1239',#818,#808,#816,.T.);
#820=ORIENTED_EDGE('',*,*,#819,.F.);
#821=CARTESIAN_POINT('',(0.,0.,-9.75000000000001));
#822=DIRECTION('',(0.,0.,1.));
#823=DIRECTION('',(1.,0.,0.));
#824=AXIS2_PLACEMENT_3D('',#821,#822,#823);
#825=CIRCLE('',#824,40.48);
#826=CARTESIAN_POINT('',(37.563019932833,-15.0880725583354,-9.75000000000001));
#827=VERTEX_POINT('',#826);
#828=EDGE_CURVE('E1238',#827,#818,#825,.F.);
#829=ORIENTED_EDGE('',*,*,#828,.F.);
#830=DIRECTION('',(0.,0.,1.));
#831=VECTOR('',#830,1.);
#832=CARTESIAN_POINT('',(37.563019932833,-15.0880725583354,-5.52500000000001));
#833=LINE('',#832,#831);
#834=EDGE_CURVE('E1245',#810,#827,#833,.F.);
#835=ORIENTED_EDGE('',*,*,#834,.F.);
#836=EDGE_LOOP('',(#812,#820,#829,#835));
#837=FACE_BOUND('',#836,.T.);
#838=CARTESIAN_POINT('',(0.,0.,-1.30000000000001));
#839=DIRECTION('',(0.,0.,-1.));
#840=DIRECTION('',(-1.,0.,0.));
#841=AXIS2_PLACEMENT_3D('',#838,#839,#840);
#842=CIRCLE('',#841,40.48);
#843=CARTESIAN_POINT('',(28.3143068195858,-28.9297499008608,-1.30000000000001));
#844=VERTEX_POINT('',#843);
#845=CARTESIAN_POINT('',(28.9297499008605,-28.3143068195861,-1.30000000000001));
#846=VERTEX_POINT('',#845);
#847=EDGE_CURVE('E1201',#844,#846,#842,.F.);
#848=ORIENTED_EDGE('',*,*,#847,.F.);
#849=DIRECTION('',(0.,0.,1.));
#850=VECTOR('',#849,1.);
#851=CARTESIAN_POINT('',(28.3143068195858,-28.9297499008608,-5.52500000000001));
#852=LINE('',#851,#850);
#853=CARTESIAN_POINT('',(28.3143068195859,-28.9297499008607,-9.75000000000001));
#854=VERTEX_POINT('',#853);
#855=EDGE_CURVE('E1198',#854,#844,#852,.T.);
#856=ORIENTED_EDGE('',*,*,#855,.F.);
#857=CARTESIAN_POINT('',(0.,0.,-9.75000000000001));
#858=DIRECTION('',(0.,0.,1.));
#859=DIRECTION('',(1.,0.,0.));
#860=AXIS2_PLACEMENT_3D('',#857,#858,#859);
#861=CIRCLE('',#860,40.48);
#862=CARTESIAN_POINT('',(28.9297499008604,-28.3143068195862,-9.75000000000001));
#863=VERTEX_POINT('',#862);
#864=EDGE_CURVE('E1199',#863,#854,#861,.F.);
#865=ORIENTED_EDGE('',*,*,#864,.F.);
#866=DIRECTION('',(0.,0.,1.));
#867=VECTOR('',#866,1.);
#868=CARTESIAN_POINT('',(28.9297499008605,-28.3143068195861,-5.52500000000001));
#869=LINE('',#868,#867);
#870=EDGE_CURVE('E1204',#846,#863,#869,.F.);
#871=ORIENTED_EDGE('',*,*,#870,.F.);
#872=EDGE_LOOP('',(#848,#856,#865,#871));
#873=FACE_BOUND('',#872,.T.);
#874=CARTESIAN_POINT('',(0.,0.,-1.30000000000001));
#875=DIRECTION('',(0.,0.,-1.));
#876=DIRECTION('',(-1.,0.,0.));
#877=AXIS2_PLACEMENT_3D('',#874,#875,#876);
#878=CIRCLE('',#877,40.48);
#879=CARTESIAN_POINT('',(15.088072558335,-37.5630199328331,-1.30000000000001));
#880=VERTEX_POINT('',#879);
#881=CARTESIAN_POINT('',(15.892187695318,-37.2299445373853,-1.30000000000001));
#882=VERTEX_POINT('',#881);
#883=EDGE_CURVE('E1162',#880,#882,#878,.F.);
#884=ORIENTED_EDGE('',*,*,#883,.F.);
#885=DIRECTION('',(0.,0.,1.));
#886=VECTOR('',#885,1.);
#887=CARTESIAN_POINT('',(15.088072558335,-37.5630199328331,-5.52500000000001));
#888=LINE('',#887,#886);
#889=CARTESIAN_POINT('',(15.0880725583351,-37.5630199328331,-9.75000000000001));
#890=VERTEX_POINT('',#889);
#891=EDGE_CURVE('E1160',#890,#880,#888,.T.);
#892=ORIENTED_EDGE('',*,*,#891,.F.);
#893=CARTESIAN_POINT('',(0.,0.,-9.75000000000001));
#894=DIRECTION('',(0.,0.,1.));
#895=DIRECTION('',(1.,0.,0.));
#896=AXIS2_PLACEMENT_3D('',#893,#894,#895);
#897=CIRCLE('',#896,40.48);
#898=CARTESIAN_POINT('',(15.8921876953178,-37.2299445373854,-9.75000000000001));
#899=VERTEX_POINT('',#898);
#900=EDGE_CURVE('E1158',#899,#890,#897,.F.);
#901=ORIENTED_EDGE('',*,*,#900,.F.);
#902=DIRECTION('',(0.,0.,1.));
#903=VECTOR('',#902,1.);
#904=CARTESIAN_POINT('',(15.892187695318,-37.2299445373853,-5.52500000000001));
#905=LINE('',#904,#903);
#906=EDGE_CURVE('E1165',#882,#899,#905,.F.);
#907=ORIENTED_EDGE('',*,*,#906,.F.);
#908=EDGE_LOOP('',(#884,#892,#901,#907));
#909=FACE_BOUND('',#908,.T.);
#910=CARTESIAN_POINT('',(0.,0.,-1.30000000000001));
#911=DIRECTION('',(0.,0.,-1.));
#912=DIRECTION('',(-1.,0.,0.));
#913=AXIS2_PLACEMENT_3D('',#910,#911,#912);
#914=CIRCLE('',#913,40.48);
#915=CARTESIAN_POINT('',(-0.435183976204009,-40.4776606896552,-1.30000000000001));
#916=VERTEX_POINT('',#915);
#917=CARTESIAN_POINT('',(0.435183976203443,-40.4776606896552,-1.30000000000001));
#918=VERTEX_POINT('',#917);
#919=EDGE_CURVE('E1122',#916,#918,#914,.F.);
#920=ORIENTED_EDGE('',*,*,#919,.F.);
#921=DIRECTION('',(0.,0.,1.));
#922=VECTOR('',#921,1.);
#923=CARTESIAN_POINT('',(-0.435183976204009,-40.4776606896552,-5.52500000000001));
#924=LINE('',#923,#922);
#925=CARTESIAN_POINT('',(-0.43518397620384,-40.4776606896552,-9.75000000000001));
#926=VERTEX_POINT('',#925);
#927=EDGE_CURVE('E1118',#926,#916,#924,.T.);
#928=ORIENTED_EDGE('',*,*,#927,.F.);
#929=CARTESIAN_POINT('',(0.,0.,-9.75000000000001));
#930=DIRECTION('',(0.,0.,1.));
#931=DIRECTION('',(1.,0.,0.));
#932=AXIS2_PLACEMENT_3D('',#929,#930,#931);
#933=CIRCLE('',#932,40.48);
#934=CARTESIAN_POINT('',(0.435183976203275,-40.4776606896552,-9.75000000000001));
#935=VERTEX_POINT('',#934);
#936=EDGE_CURVE('E1119',#935,#926,#933,.F.);
#937=ORIENTED_EDGE('',*,*,#936,.F.);
#938=DIRECTION('',(0.,0.,1.));
#939=VECTOR('',#938,1.);
#940=CARTESIAN_POINT('',(0.435183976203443,-40.4776606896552,-5.52500000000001));
#941=LINE('',#940,#939);
#942=EDGE_CURVE('E1121',#918,#935,#941,.F.);
#943=ORIENTED_EDGE('',*,*,#942,.F.);
#944=EDGE_LOOP('',(#920,#928,#937,#943));
#945=FACE_BOUND('',#944,.T.);
#946=CARTESIAN_POINT('',(0.,0.,-1.30000000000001));
#947=DIRECTION('',(0.,0.,-1.));
#948=DIRECTION('',(-1.,0.,0.));
#949=AXIS2_PLACEMENT_3D('',#946,#947,#948);
#950=CIRCLE('',#949,40.48);
#951=CARTESIAN_POINT('',(-15.8921876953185,-37.229944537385,-1.30000000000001));
#952=VERTEX_POINT('',#951);
#953=CARTESIAN_POINT('',(-15.0880725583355,-37.5630199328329,-1.30000000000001));
#954=VERTEX_POINT('',#953);
#955=EDGE_CURVE('E1084',#952,#954,#950,.F.);
#956=ORIENTED_EDGE('',*,*,#955,.F.);
#957=DIRECTION('',(0.,0.,1.));
#958=VECTOR('',#957,1.);
#959=CARTESIAN_POINT('',(-15.8921876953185,-37.229944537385,-5.52500000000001));
#960=LINE('',#959,#958);
#961=CARTESIAN_POINT('',(-15.8921876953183,-37.2299445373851,-9.75000000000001));
#962=VERTEX_POINT('',#961);
#963=EDGE_CURVE('E1080',#962,#952,#960,.T.);
#964=ORIENTED_EDGE('',*,*,#963,.F.);
#965=CARTESIAN_POINT('',(0.,0.,-9.75000000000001));
#966=DIRECTION('',(0.,0.,1.));
#967=DIRECTION('',(1.,0.,0.));
#968=AXIS2_PLACEMENT_3D('',#965,#966,#967);
#969=CIRCLE('',#968,40.48);
#970=CARTESIAN_POINT('',(-15.0880725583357,-37.5630199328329,-9.75000000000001));
#971=VERTEX_POINT('',#970);
#972=EDGE_CURVE('E1078',#971,#962,#969,.F.);
#973=ORIENTED_EDGE('',*,*,#972,.F.);
#974=DIRECTION('',(0.,0.,1.));
#975=VECTOR('',#974,1.);
#976=CARTESIAN_POINT('',(-15.0880725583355,-37.5630199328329,-5.52500000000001));
#977=LINE('',#976,#975);
#978=EDGE_CURVE('E1082',#954,#971,#977,.F.);
#979=ORIENTED_EDGE('',*,*,#978,.F.);
#980=EDGE_LOOP('',(#956,#964,#973,#979));
#981=FACE_BOUND('',#980,.T.);
#982=CARTESIAN_POINT('',(0.,0.,-1.30000000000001));
#983=DIRECTION('',(0.,0.,-1.));
#984=DIRECTION('',(-1.,0.,0.));
#985=AXIS2_PLACEMENT_3D('',#982,#983,#984);
#986=CIRCLE('',#985,40.48);
#987=CARTESIAN_POINT('',(-28.9297499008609,-28.3143068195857,-1.30000000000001));
#988=VERTEX_POINT('',#987);
#989=CARTESIAN_POINT('',(-28.3143068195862,-28.9297499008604,-1.30000000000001));
#990=VERTEX_POINT('',#989);
#991=EDGE_CURVE('E1042',#988,#990,#986,.F.);
#992=ORIENTED_EDGE('',*,*,#991,.F.);
#993=DIRECTION('',(0.,0.,1.));
#994=VECTOR('',#993,1.);
#995=CARTESIAN_POINT('',(-28.9297499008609,-28.3143068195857,-5.52500000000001));
#996=LINE('',#995,#994);
#997=CARTESIAN_POINT('',(-28.9297499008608,-28.3143068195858,-9.75000000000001));
#998=VERTEX_POINT('',#997);
#999=EDGE_CURVE('E1036',#998,#988,#996,.T.);
#1000=ORIENTED_EDGE('',*,*,#999,.F.);
#1001=CARTESIAN_POINT('',(0.,0.,-9.75000000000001));
#1002=DIRECTION('',(0.,0.,1.));
#1003=DIRECTION('',(1.,0.,0.));
#1004=AXIS2_PLACEMENT_3D('',#1001,#1002,#1003);
#1005=CIRCLE('',#1004,40.48);
#1006=CARTESIAN_POINT('',(-28.3143068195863,-28.9297499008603,-9.75000000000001));
#1007=VERTEX_POINT('',#1006);
#1008=EDGE_CURVE('E1037',#1007,#998,#1005,.F.);
#1009=ORIENTED_EDGE('',*,*,#1008,.F.);
#1010=DIRECTION('',(0.,0.,1.));
#1011=VECTOR('',#1010,1.);
#1012=CARTESIAN_POINT('',(-28.3143068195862,-28.9297499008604,-5.52500000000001));
#1013=LINE('',#1012,#1011);
#1014=EDGE_CURVE('E1041',#990,#1007,#1013,.F.);
#1015=ORIENTED_EDGE('',*,*,#1014,.F.);
#1016=EDGE_LOOP('',(#992,#1000,#1009,#1015));
#1017=FACE_BOUND('',#1016,.T.);
#1018=CARTESIAN_POINT('',(0.,0.,-1.30000000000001));
#1019=DIRECTION('',(0.,0.,-1.));
#1020=DIRECTION('',(-1.,0.,0.));
#1021=AXIS2_PLACEMENT_3D('',#1018,#1019,#1020);
#1022=CIRCLE('',#1021,40.48);
#1023=CARTESIAN_POINT('',(-37.5630199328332,-15.0880725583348,-1.30000000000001));
#1024=VERTEX_POINT('',#1023);
#1025=CARTESIAN_POINT('',(-37.2299445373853,-15.8921876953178,-1.30000000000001));
#1026=VERTEX_POINT('',#1025);
#1027=EDGE_CURVE('E1001',#1024,#1026,#1022,.F.);
#1028=ORIENTED_EDGE('',*,*,#1027,.F.);
#1029=DIRECTION('',(0.,0.,1.));
#1030=VECTOR('',#1029,1.);
#1031=CARTESIAN_POINT('',(-37.5630199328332,-15.0880725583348,-5.52500000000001));
#1032=LINE('',#1031,#1030);
#1033=CARTESIAN_POINT('',(-37.5630199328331,-15.088072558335,-9.75000000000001));
#1034=VERTEX_POINT('',#1033);
#1035=EDGE_CURVE('E998',#1034,#1024,#1032,.T.);
#1036=ORIENTED_EDGE('',*,*,#1035,.F.);
#1037=CARTESIAN_POINT('',(0.,0.,-9.75000000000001));
#1038=DIRECTION('',(0.,0.,1.));
#1039=DIRECTION('',(1.,0.,0.));
#1040=AXIS2_PLACEMENT_3D('',#1037,#1038,#1039);
#1041=CIRCLE('',#1040,40.48);
#1042=CARTESIAN_POINT('',(-37.2299445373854,-15.8921876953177,-9.75000000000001));
#1043=VERTEX_POINT('',#1042);
#1044=EDGE_CURVE('E999',#1043,#1034,#1041,.F.);
#1045=ORIENTED_EDGE('',*,*,#1044,.F.);
#1046=DIRECTION('',(0.,0.,1.));
#1047=VECTOR('',#1046,1.);
#1048=CARTESIAN_POINT('',(-37.2299445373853,-15.8921876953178,-5.52500000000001));
#1049=LINE('',#1048,#1047);
#1050=EDGE_CURVE('E1004',#1026,#1043,#1049,.F.);
#1051=ORIENTED_EDGE('',*,*,#1050,.F.);
#1052=EDGE_LOOP('',(#1028,#1036,#1045,#1051));
#1053=FACE_BOUND('',#1052,.T.);
#1054=CARTESIAN_POINT('',(0.,0.,-1.30000000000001));
#1055=DIRECTION('',(0.,0.,-1.));
#1056=DIRECTION('',(-1.,0.,0.));
#1057=AXIS2_PLACEMENT_3D('',#1054,#1055,#1056);
#1058=CIRCLE('',#1057,40.48);
#1059=CARTESIAN_POINT('',(-40.4776606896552,0.43518397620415,-1.30000000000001));
#1060=VERTEX_POINT('',#1059);
#1061=CARTESIAN_POINT('',(-40.4776606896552,-0.435183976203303,-1.30000000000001));
#1062=VERTEX_POINT('',#1061);
#1063=EDGE_CURVE('E963',#1060,#1062,#1058,.F.);
#1064=ORIENTED_EDGE('',*,*,#1063,.F.);
#1065=DIRECTION('',(0.,0.,1.));
#1066=VECTOR('',#1065,1.);
#1067=CARTESIAN_POINT('',(-40.4776606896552,0.43518397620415,-5.52500000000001));
#1068=LINE('',#1067,#1066);
#1069=CARTESIAN_POINT('',(-40.4776606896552,0.435183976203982,-9.75000000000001));
#1070=VERTEX_POINT('',#1069);
#1071=EDGE_CURVE('E956',#1070,#1060,#1068,.T.);
#1072=ORIENTED_EDGE('',*,*,#1071,.F.);
#1073=CARTESIAN_POINT('',(0.,0.,-9.75000000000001));
#1074=DIRECTION('',(0.,0.,1.));
#1075=DIRECTION('',(1.,0.,0.));
#1076=AXIS2_PLACEMENT_3D('',#1073,#1074,#1075);
#1077=CIRCLE('',#1076,40.48);
#1078=CARTESIAN_POINT('',(-40.4776606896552,-0.435183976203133,-9.75000000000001));
#1079=VERTEX_POINT('',#1078);
#1080=EDGE_CURVE('E957',#1079,#1070,#1077,.F.);
#1081=ORIENTED_EDGE('',*,*,#1080,.F.);
#1082=DIRECTION('',(0.,0.,1.));
#1083=VECTOR('',#1082,1.);
#1084=CARTESIAN_POINT('',(-40.4776606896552,-0.435183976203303,-5.52500000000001));
#1085=LINE('',#1084,#1083);
#1086=EDGE_CURVE('E965',#1062,#1079,#1085,.F.);
#1087=ORIENTED_EDGE('',*,*,#1086,.F.);
#1088=EDGE_LOOP('',(#1064,#1072,#1081,#1087));
#1089=FACE_BOUND('',#1088,.T.);
#1090=CARTESIAN_POINT('',(0.,0.,-1.30000000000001));
#1091=DIRECTION('',(0.,0.,-1.));
#1092=DIRECTION('',(-1.,0.,0.));
#1093=AXIS2_PLACEMENT_3D('',#1090,#1091,#1092);
#1094=CIRCLE('',#1093,40.48);
#1095=CARTESIAN_POINT('',(-37.229944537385,15.8921876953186,-1.30000000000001));
#1096=VERTEX_POINT('',#1095);
#1097=CARTESIAN_POINT('',(-37.5630199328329,15.0880725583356,-1.30000000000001));
#1098=VERTEX_POINT('',#1097);
#1099=EDGE_CURVE('E922',#1096,#1098,#1094,.F.);
#1100=ORIENTED_EDGE('',*,*,#1099,.F.);
#1101=DIRECTION('',(0.,0.,1.));
#1102=VECTOR('',#1101,1.);
#1103=CARTESIAN_POINT('',(-37.229944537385,15.8921876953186,-5.52500000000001));
#1104=LINE('',#1103,#1102);
#1105=CARTESIAN_POINT('',(-37.2299445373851,15.8921876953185,-9.75000000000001));
#1106=VERTEX_POINT('',#1105);
#1107=EDGE_CURVE('E918',#1106,#1096,#1104,.T.);
#1108=ORIENTED_EDGE('',*,*,#1107,.F.);
#1109=CARTESIAN_POINT('',(0.,0.,-9.75000000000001));
#1110=DIRECTION('',(0.,0.,1.));
#1111=DIRECTION('',(1.,0.,0.));
#1112=AXIS2_PLACEMENT_3D('',#1109,#1110,#1111);
#1113=CIRCLE('',#1112,40.48);
#1114=CARTESIAN_POINT('',(-37.5630199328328,15.0880725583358,-9.75000000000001));
#1115=VERTEX_POINT('',#1114);
#1116=EDGE_CURVE('E919',#1115,#1106,#1113,.F.);
#1117=ORIENTED_EDGE('',*,*,#1116,.F.);
#1118=DIRECTION('',(0.,0.,1.));
#1119=VECTOR('',#1118,1.);
#1120=CARTESIAN_POINT('',(-37.5630199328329,15.0880725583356,-5.52500000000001));
#1121=LINE('',#1120,#1119);
#1122=EDGE_CURVE('E921',#1098,#1115,#1121,.F.);
#1123=ORIENTED_EDGE('',*,*,#1122,.F.);
#1124=EDGE_LOOP('',(#1100,#1108,#1117,#1123));
#1125=FACE_BOUND('',#1124,.T.);
#1126=CARTESIAN_POINT('',(0.,0.,-1.30000000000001));
#1127=DIRECTION('',(0.,0.,-1.));
#1128=DIRECTION('',(-1.,0.,0.));
#1129=AXIS2_PLACEMENT_3D('',#1126,#1127,#1128);
#1130=CIRCLE('',#1129,40.48);
#1131=CARTESIAN_POINT('',(-28.3143068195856,28.929749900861,-1.30000000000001));
#1132=VERTEX_POINT('',#1131);
#1133=CARTESIAN_POINT('',(-28.9297499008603,28.3143068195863,-1.30000000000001));
#1134=VERTEX_POINT('',#1133);
#1135=EDGE_CURVE('E883',#1132,#1134,#1130,.F.);
#1136=ORIENTED_EDGE('',*,*,#1135,.F.);
#1137=DIRECTION('',(0.,0.,1.));
#1138=VECTOR('',#1137,1.);
#1139=CARTESIAN_POINT('',(-28.3143068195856,28.929749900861,-5.52500000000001));
#1140=LINE('',#1139,#1138);
#1141=CARTESIAN_POINT('',(-28.3143068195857,28.9297499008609,-9.75000000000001));
#1142=VERTEX_POINT('',#1141);
#1143=EDGE_CURVE('E878',#1142,#1132,#1140,.T.);
#1144=ORIENTED_EDGE('',*,*,#1143,.F.);
#1145=CARTESIAN_POINT('',(0.,0.,-9.75000000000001));
#1146=DIRECTION('',(0.,0.,1.));
#1147=DIRECTION('',(1.,0.,0.));
#1148=AXIS2_PLACEMENT_3D('',#1145,#1146,#1147);
#1149=CIRCLE('',#1148,40.48);
#1150=CARTESIAN_POINT('',(-28.9297499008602,28.3143068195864,-9.75000000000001));
#1151=VERTEX_POINT('',#1150);
#1152=EDGE_CURVE('E876',#1151,#1142,#1149,.F.);
#1153=ORIENTED_EDGE('',*,*,#1152,.F.);
#1154=DIRECTION('',(0.,0.,1.));
#1155=VECTOR('',#1154,1.);
#1156=CARTESIAN_POINT('',(-28.9297499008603,28.3143068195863,-5.52500000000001));
#1157=LINE('',#1156,#1155);
#1158=EDGE_CURVE('E885',#1134,#1151,#1157,.F.);
#1159=ORIENTED_EDGE('',*,*,#1158,.F.);
#1160=EDGE_LOOP('',(#1136,#1144,#1153,#1159));
#1161=FACE_BOUND('',#1160,.T.);
#1162=CARTESIAN_POINT('',(0.,0.,-1.30000000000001));
#1163=DIRECTION('',(0.,0.,-1.));
#1164=DIRECTION('',(-1.,0.,0.));
#1165=AXIS2_PLACEMENT_3D('',#1162,#1163,#1164);
#1166=CIRCLE('',#1165,40.48);
#1167=CARTESIAN_POINT('',(-15.0880725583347,37.5630199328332,-1.30000000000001));
#1168=VERTEX_POINT('',#1167);
#1169=CARTESIAN_POINT('',(-15.8921876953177,37.2299445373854,-1.30000000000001));
#1170=VERTEX_POINT('',#1169);
#1171=EDGE_CURVE('E58',#1168,#1170,#1166,.F.);
#1172=ORIENTED_EDGE('',*,*,#1171,.F.);
#1173=DIRECTION('',(0.,0.,1.));
#1174=VECTOR('',#1173,1.);
#1175=CARTESIAN_POINT('',(-15.0880725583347,37.5630199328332,-5.52500000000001));
#1176=LINE('',#1175,#1174);
#1177=CARTESIAN_POINT('',(-15.0880725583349,37.5630199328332,-9.75000000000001));
#1178=VERTEX_POINT('',#1177);
#1179=EDGE_CURVE('E824',#1178,#1168,#1176,.T.);
#1180=ORIENTED_EDGE('',*,*,#1179,.F.);
#1181=CARTESIAN_POINT('',(0.,0.,-9.75000000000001));
#1182=DIRECTION('',(0.,0.,1.));
#1183=DIRECTION('',(1.,0.,0.));
#1184=AXIS2_PLACEMENT_3D('',#1181,#1182,#1183);
#1185=CIRCLE('',#1184,40.48);
#1186=CARTESIAN_POINT('',(-15.8921876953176,37.2299445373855,-9.75000000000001));
#1187=VERTEX_POINT('',#1186);
#1188=EDGE_CURVE('E825',#1187,#1178,#1185,.F.);
#1189=ORIENTED_EDGE('',*,*,#1188,.F.);
#1190=DIRECTION('',(0.,0.,1.));
#1191=VECTOR('',#1190,1.);
#1192=CARTESIAN_POINT('',(-15.8921876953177,37.2299445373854,-5.52500000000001));
#1193=LINE('',#1192,#1191);
#1194=EDGE_CURVE('E57',#1170,#1187,#1193,.F.);
#1195=ORIENTED_EDGE('',*,*,#1194,.F.);
#1196=EDGE_LOOP('',(#1172,#1180,#1189,#1195));
#1197=FACE_BOUND('',#1196,.T.);
#1198=ADVANCED_FACE('F41',(#59,#95,#131,#167,#203,#239,#275,#311,#347,#383,#419,#455,#491,#527,
#563,#599,#610,#621,#657,#693,#729,#765,#801,#837,#873,#909,#945,#981,#1017,#1053,#1089,#1125,
#1161,#1197),#23,.F.);
#1199=CARTESIAN_POINT('',(0.,0.,70.8625909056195));
#1200=DIRECTION('',(0.,0.,1.));
#1201=DIRECTION('',(1.,0.,0.));
#1202=AXIS2_PLACEMENT_3D('',#1199,#1200,#1201);
#1203=CYLINDRICAL_SURFACE('',#1202,32.02);
#1204=DIRECTION('',(0.,0.,1.));
#1205=VECTOR('',#1204,1.);
#1206=CARTESIAN_POINT('',(-12.6102113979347,29.4323456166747,5.52499999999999));
#1207=LINE('',#1206,#1205);
#1208=CARTESIAN_POINT('',(-12.6102113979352,29.4323456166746,1.29999999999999));
#1209=VERTEX_POINT('',#1208);
#1210=CARTESIAN_POINT('',(-12.6102113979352,29.4323456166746,9.74999999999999));
#1211=VERTEX_POINT('',#1210);
#1212=EDGE_CURVE('E1888',#1209,#1211,#1207,.T.);
#1213=ORIENTED_EDGE('',*,*,#1212,.F.);
#1214=CARTESIAN_POINT('',(0.,0.,1.3));
#1215=DIRECTION('',(0.,0.,1.));
#1216=DIRECTION('',(1.,0.,0.));
#1217=AXIS2_PLACEMENT_3D('',#1214,#1215,#1216);
#1218=CIRCLE('',#1217,32.02);
#1219=CARTESIAN_POINT('',(-11.8950451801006,29.7285771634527,1.29999999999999));
#1220=VERTEX_POINT('',#1219);
#1221=EDGE_CURVE('E1884',#1220,#1209,#1218,.T.);
#1222=ORIENTED_EDGE('',*,*,#1221,.F.);
#1223=DIRECTION('',(0.,0.,1.));
#1224=VECTOR('',#1223,1.);
#1225=CARTESIAN_POINT('',(-11.8950451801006,29.7285771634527,5.52499999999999));
#1226=LINE('',#1225,#1224);
#1227=CARTESIAN_POINT('',(-11.8950451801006,29.7285771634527,9.74999999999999));
#1228=VERTEX_POINT('',#1227);
#1229=EDGE_CURVE('E1882',#1228,#1220,#1226,.F.);
#1230=ORIENTED_EDGE('',*,*,#1229,.F.);
#1231=CARTESIAN_POINT('',(0.,0.,9.74999999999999));
#1232=DIRECTION('',(0.,0.,-1.));
#1233=DIRECTION('',(-1.,0.,0.));
#1234=AXIS2_PLACEMENT_3D('',#1231,#1232,#1233);
#1235=CIRCLE('',#1234,32.02);
#1236=EDGE_CURVE('E1890',#1211,#1228,#1235,.T.);
#1237=ORIENTED_EDGE('',*,*,#1236,.F.);
#1238=EDGE_LOOP('',(#1213,#1222,#1230,#1237));
#1239=FACE_BOUND('',#1238,.T.);
#1240=DIRECTION('',(0.,0.,1.));
#1241=VECTOR('',#1240,1.);
#1242=CARTESIAN_POINT('',(-22.9135872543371,22.366222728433,5.52499999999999));
#1243=LINE('',#1242,#1241);
#1244=CARTESIAN_POINT('',(-22.9135872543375,22.3662227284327,1.29999999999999));
#1245=VERTEX_POINT('',#1244);
#1246=CARTESIAN_POINT('',(-22.9135872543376,22.3662227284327,9.74999999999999));
#1247=VERTEX_POINT('',#1246);
#1248=EDGE_CURVE('E1869',#1245,#1247,#1243,.T.);
#1249=ORIENTED_EDGE('',*,*,#1248,.F.);
#1250=CARTESIAN_POINT('',(0.,0.,1.3));
#1251=DIRECTION('',(0.,0.,1.));
#1252=DIRECTION('',(1.,0.,0.));
#1253=AXIS2_PLACEMENT_3D('',#1250,#1251,#1252);
#1254=CIRCLE('',#1253,32.02);
#1255=CARTESIAN_POINT('',(-22.3662227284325,22.9135872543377,1.29999999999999));
#1256=VERTEX_POINT('',#1255);
#1257=EDGE_CURVE('E1858',#1256,#1245,#1254,.T.);
#1258=ORIENTED_EDGE('',*,*,#1257,.F.);
#1259=DIRECTION('',(0.,0.,1.));
#1260=VECTOR('',#1259,1.);
#1261=CARTESIAN_POINT('',(-22.3662227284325,22.9135872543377,5.52499999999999));
#1262=LINE('',#1261,#1260);
#1263=CARTESIAN_POINT('',(-22.3662227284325,22.9135872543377,9.74999999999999));
#1264=VERTEX_POINT('',#1263);
#1265=EDGE_CURVE('E1860',#1264,#1256,#1262,.F.);
#1266=ORIENTED_EDGE('',*,*,#1265,.F.);
#1267=CARTESIAN_POINT('',(0.,0.,9.74999999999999));
#1268=DIRECTION('',(0.,0.,-1.));
#1269=DIRECTION('',(-1.,0.,0.));
#1270=AXIS2_PLACEMENT_3D('',#1267,#1268,#1269);
#1271=CIRCLE('',#1270,32.02);
#1272=EDGE_CURVE('E1864',#1247,#1264,#1271,.T.);
#1273=ORIENTED_EDGE('',*,*,#1272,.F.);
#1274=EDGE_LOOP('',(#1249,#1258,#1266,#1273));
#1275=FACE_BOUND('',#1274,.T.);
#1276=DIRECTION('',(0.,0.,1.));
#1277=VECTOR('',#1276,1.);
#1278=CARTESIAN_POINT('',(-29.7285771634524,11.8950451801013,5.52499999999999));
#1279=LINE('',#1278,#1277);
#1280=CARTESIAN_POINT('',(-29.7285771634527,11.8950451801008,1.29999999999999));
#1281=VERTEX_POINT('',#1280);
#1282=CARTESIAN_POINT('',(-29.7285771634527,11.8950451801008,9.74999999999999));
#1283=VERTEX_POINT('',#1282);
#1284=EDGE_CURVE('E1845',#1281,#1283,#1279,.T.);
#1285=ORIENTED_EDGE('',*,*,#1284,.F.);
#1286=CARTESIAN_POINT('',(0.,0.,1.3));
#1287=DIRECTION('',(0.,0.,1.));
#1288=DIRECTION('',(1.,0.,0.));
#1289=AXIS2_PLACEMENT_3D('',#1286,#1287,#1288);
#1290=CIRCLE('',#1289,32.02);
#1291=CARTESIAN_POINT('',(-29.4323456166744,12.6102113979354,1.29999999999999));
#1292=VERTEX_POINT('',#1291);
#1293=EDGE_CURVE('E1838',#1292,#1281,#1290,.T.);
#1294=ORIENTED_EDGE('',*,*,#1293,.F.);
#1295=DIRECTION('',(0.,0.,1.));
#1296=VECTOR('',#1295,1.);
#1297=CARTESIAN_POINT('',(-29.4323456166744,12.6102113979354,5.52499999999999));
#1298=LINE('',#1297,#1296);
#1299=CARTESIAN_POINT('',(-29.4323456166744,12.6102113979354,9.74999999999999));
#1300=VERTEX_POINT('',#1299);
#1301=EDGE_CURVE('E1831',#1300,#1292,#1298,.F.);
#1302=ORIENTED_EDGE('',*,*,#1301,.F.);
#1303=CARTESIAN_POINT('',(0.,0.,9.74999999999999));
#1304=DIRECTION('',(0.,0.,-1.));
#1305=DIRECTION('',(-1.,0.,0.));
#1306=AXIS2_PLACEMENT_3D('',#1303,#1304,#1305);
#1307=CIRCLE('',#1306,32.02);
#1308=EDGE_CURVE('E1839',#1283,#1300,#1307,.T.);
#1309=ORIENTED_EDGE('',*,*,#1308,.F.);
#1310=EDGE_LOOP('',(#1285,#1294,#1302,#1309));
#1311=FACE_BOUND('',#1310,.T.);
#1312=DIRECTION('',(0.,0.,1.));
#1313=VECTOR('',#1312,1.);
#1314=CARTESIAN_POINT('',(-32.0176606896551,-0.387045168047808,5.52499999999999));
#1315=LINE('',#1314,#1313);
#1316=CARTESIAN_POINT('',(-32.0176606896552,-0.387045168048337,1.29999999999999));
#1317=VERTEX_POINT('',#1316);
#1318=CARTESIAN_POINT('',(-32.0176606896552,-0.387045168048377,9.74999999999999));
#1319=VERTEX_POINT('',#1318);
#1320=EDGE_CURVE('E1820',#1317,#1319,#1315,.T.);
#1321=ORIENTED_EDGE('',*,*,#1320,.F.);
#1322=CARTESIAN_POINT('',(0.,0.,1.3));
#1323=DIRECTION('',(0.,0.,1.));
#1324=DIRECTION('',(1.,0.,0.));
#1325=AXIS2_PLACEMENT_3D('',#1322,#1323,#1324);
#1326=CIRCLE('',#1325,32.02);
#1327=CARTESIAN_POINT('',(-32.0176606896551,0.38704516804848,1.29999999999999));
#1328=VERTEX_POINT('',#1327);
#1329=EDGE_CURVE('E1815',#1328,#1317,#1326,.T.);
#1330=ORIENTED_EDGE('',*,*,#1329,.F.);
#1331=DIRECTION('',(0.,0.,1.));
#1332=VECTOR('',#1331,1.);
#1333=CARTESIAN_POINT('',(-32.0176606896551,0.387045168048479,5.52499999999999));
#1334=LINE('',#1333,#1332);
#1335=CARTESIAN_POINT('',(-32.0176606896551,0.387045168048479,9.74999999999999));
#1336=VERTEX_POINT('',#1335);
#1337=EDGE_CURVE('E1809',#1336,#1328,#1334,.F.);
#1338=ORIENTED_EDGE('',*,*,#1337,.F.);
#1339=CARTESIAN_POINT('',(0.,0.,9.74999999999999));
#1340=DIRECTION('',(0.,0.,-1.));
#1341=DIRECTION('',(-1.,0.,0.));
#1342=AXIS2_PLACEMENT_3D('',#1339,#1340,#1341);
#1343=CIRCLE('',#1342,32.02);
#1344=EDGE_CURVE('E1813',#1319,#1336,#1343,.T.);
#1345=ORIENTED_EDGE('',*,*,#1344,.F.);
#1346=EDGE_LOOP('',(#1321,#1330,#1338,#1345));
#1347=FACE_BOUND('',#1346,.T.);
#1348=DIRECTION('',(0.,0.,1.));
#1349=VECTOR('',#1348,1.);
#1350=CARTESIAN_POINT('',(-29.4323456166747,-12.6102113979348,5.52499999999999));
#1351=LINE('',#1350,#1349);
#1352=CARTESIAN_POINT('',(-29.4323456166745,-12.6102113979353,1.29999999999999));
#1353=VERTEX_POINT('',#1352);
#1354=CARTESIAN_POINT('',(-29.4323456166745,-12.6102113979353,9.74999999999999));
#1355=VERTEX_POINT('',#1354);
#1356=EDGE_CURVE('E1793',#1353,#1355,#1351,.T.);
#1357=ORIENTED_EDGE('',*,*,#1356,.F.);
#1358=CARTESIAN_POINT('',(0.,0.,1.3));
#1359=DIRECTION('',(0.,0.,1.));
#1360=DIRECTION('',(1.,0.,0.));
#1361=AXIS2_PLACEMENT_3D('',#1358,#1359,#1360);
#1362=CIRCLE('',#1361,32.02);
#1363=CARTESIAN_POINT('',(-29.7285771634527,-11.8950451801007,1.29999999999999));
#1364=VERTEX_POINT('',#1363);
#1365=EDGE_CURVE('E1789',#1364,#1353,#1362,.T.);
#1366=ORIENTED_EDGE('',*,*,#1365,.F.);
#1367=DIRECTION('',(0.,0.,1.));
#1368=VECTOR('',#1367,1.);
#1369=CARTESIAN_POINT('',(-29.7285771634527,-11.8950451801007,5.52499999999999));
#1370=LINE('',#1369,#1368);
#1371=CARTESIAN_POINT('',(-29.7285771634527,-11.8950451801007,9.74999999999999));
#1372=VERTEX_POINT('',#1371);
#1373=EDGE_CURVE('E1783',#1372,#1364,#1370,.F.);
#1374=ORIENTED_EDGE('',*,*,#1373,.F.);
#1375=CARTESIAN_POINT('',(0.,0.,9.74999999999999));
#1376=DIRECTION('',(0.,0.,-1.));
#1377=DIRECTION('',(-1.,0.,0.));
#1378=AXIS2_PLACEMENT_3D('',#1375,#1376,#1377);
#1379=CIRCLE('',#1378,32.02);
#1380=EDGE_CURVE('E1794',#1355,#1372,#1379,.T.);
#1381=ORIENTED_EDGE('',*,*,#1380,.F.);
#1382=EDGE_LOOP('',(#1357,#1366,#1374,#1381));
#1383=FACE_BOUND('',#1382,.T.);
#1384=DIRECTION('',(0.,0.,1.));
#1385=VECTOR('',#1384,1.);
#1386=CARTESIAN_POINT('',(-22.3662227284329,-22.9135872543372,5.52499999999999));
#1387=LINE('',#1386,#1385);
#1388=CARTESIAN_POINT('',(-22.3662227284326,-22.9135872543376,1.29999999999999));
#1389=VERTEX_POINT('',#1388);
#1390=CARTESIAN_POINT('',(-22.3662227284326,-22.9135872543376,9.74999999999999));
#1391=VERTEX_POINT('',#1390);
#1392=EDGE_CURVE('E1769',#1389,#1391,#1387,.T.);
#1393=ORIENTED_EDGE('',*,*,#1392,.F.);
#1394=CARTESIAN_POINT('',(0.,0.,1.3));
#1395=DIRECTION('',(0.,0.,1.));
#1396=DIRECTION('',(1.,0.,0.));
#1397=AXIS2_PLACEMENT_3D('',#1394,#1395,#1396);
#1398=CIRCLE('',#1397,32.02);
#1399=CARTESIAN_POINT('',(-22.9135872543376,-22.3662227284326,1.29999999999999));
#1400=VERTEX_POINT('',#1399);
#1401=EDGE_CURVE('E1764',#1400,#1389,#1398,.T.);
#1402=ORIENTED_EDGE('',*,*,#1401,.F.);
#1403=DIRECTION('',(0.,0.,1.));
#1404=VECTOR('',#1403,1.);
#1405=CARTESIAN_POINT('',(-22.9135872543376,-22.3662227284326,5.52499999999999));
#1406=LINE('',#1405,#1404);
#1407=CARTESIAN_POINT('',(-22.9135872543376,-22.3662227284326,9.74999999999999));
#1408=VERTEX_POINT('',#1407);
#1409=EDGE_CURVE('E1763',#1408,#1400,#1406,.F.);
#1410=ORIENTED_EDGE('',*,*,#1409,.F.);
#1411=CARTESIAN_POINT('',(0.,0.,9.74999999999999));
#1412=DIRECTION('',(0.,0.,-1.));
#1413=DIRECTION('',(-1.,0.,0.));
#1414=AXIS2_PLACEMENT_3D('',#1411,#1412,#1413);
#1415=CIRCLE('',#1414,32.02);
#1416=EDGE_CURVE('E1770',#1391,#1408,#1415,.T.);
#1417=ORIENTED_EDGE('',*,*,#1416,.F.);
#1418=EDGE_LOOP('',(#1393,#1402,#1410,#1417));
#1419=FACE_BOUND('',#1418,.T.);
#1420=DIRECTION('',(0.,0.,1.));
#1421=VECTOR('',#1420,1.);
#1422=CARTESIAN_POINT('',(-11.8950451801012,-29.7285771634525,5.52499999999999));
#1423=LINE('',#1422,#1421);
#1424=CARTESIAN_POINT('',(-11.8950451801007,-29.7285771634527,1.29999999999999));
#1425=VERTEX_POINT('',#1424);
#1426=CARTESIAN_POINT('',(-11.8950451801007,-29.7285771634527,9.74999999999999));
#1427=VERTEX_POINT('',#1426);
#1428=EDGE_CURVE('E1749',#1425,#1427,#1423,.T.);
#1429=ORIENTED_EDGE('',*,*,#1428,.F.);
#1430=CARTESIAN_POINT('',(0.,0.,1.3));
#1431=DIRECTION('',(0.,0.,1.));
#1432=DIRECTION('',(1.,0.,0.));
#1433=AXIS2_PLACEMENT_3D('',#1430,#1431,#1432);
#1434=CIRCLE('',#1433,32.02);
#1435=CARTESIAN_POINT('',(-12.6102113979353,-29.4323456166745,1.29999999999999));
#1436=VERTEX_POINT('',#1435);
#1437=EDGE_CURVE('E1738',#1436,#1425,#1434,.T.);
#1438=ORIENTED_EDGE('',*,*,#1437,.F.);
#1439=DIRECTION('',(0.,0.,1.));
#1440=VECTOR('',#1439,1.);
#1441=CARTESIAN_POINT('',(-12.6102113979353,-29.4323456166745,5.52499999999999));
#1442=LINE('',#1441,#1440);
#1443=CARTESIAN_POINT('',(-12.6102113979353,-29.4323456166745,9.74999999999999));
#1444=VERTEX_POINT('',#1443);
#1445=EDGE_CURVE('E1740',#1444,#1436,#1442,.F.);
#1446=ORIENTED_EDGE('',*,*,#1445,.F.);
#1447=CARTESIAN_POINT('',(0.,0.,9.74999999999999));
#1448=DIRECTION('',(0.,0.,-1.));
#1449=DIRECTION('',(-1.,0.,0.));
#1450=AXIS2_PLACEMENT_3D('',#1447,#1448,#1449);
#1451=CIRCLE('',#1450,32.02);
#1452=EDGE_CURVE('E1745',#1427,#1444,#1451,.T.);
#1453=ORIENTED_EDGE('',*,*,#1452,.F.);
#1454=EDGE_LOOP('',(#1429,#1438,#1446,#1453));
#1455=FACE_BOUND('',#1454,.T.);
#1456=DIRECTION('',(0.,0.,1.));
#1457=VECTOR('',#1456,1.);
#1458=CARTESIAN_POINT('',(0.38704516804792,-32.0176606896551,5.52499999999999));
#1459=LINE('',#1458,#1457);
#1460=CARTESIAN_POINT('',(0.387045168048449,-32.0176606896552,1.29999999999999));
#1461=VERTEX_POINT('',#1460);
#1462=CARTESIAN_POINT('',(0.387045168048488,-32.0176606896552,9.74999999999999));
#1463=VERTEX_POINT('',#1462);
#1464=EDGE_CURVE('E1721',#1461,#1463,#1459,.T.);
#1465=ORIENTED_EDGE('',*,*,#1464,.F.);
#1466=CARTESIAN_POINT('',(0.,0.,1.3));
#1467=DIRECTION('',(0.,0.,1.));
#1468=DIRECTION('',(1.,0.,0.));
#1469=AXIS2_PLACEMENT_3D('',#1466,#1467,#1468);
#1470=CIRCLE('',#1469,32.02);
#1471=CARTESIAN_POINT('',(-0.387045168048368,-32.0176606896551,1.29999999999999));
#1472=VERTEX_POINT('',#1471);
#1473=EDGE_CURVE('E1719',#1472,#1461,#1470,.T.);
#1474=ORIENTED_EDGE('',*,*,#1473,.F.);
#1475=DIRECTION('',(0.,0.,1.));
#1476=VECTOR('',#1475,1.);
#1477=CARTESIAN_POINT('',(-0.387045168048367,-32.0176606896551,5.52499999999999));
#1478=LINE('',#1477,#1476);
#1479=CARTESIAN_POINT('',(-0.387045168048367,-32.0176606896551,9.74999999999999));
#1480=VERTEX_POINT('',#1479);
#1481=EDGE_CURVE('E1714',#1480,#1472,#1478,.F.);
#1482=ORIENTED_EDGE('',*,*,#1481,.F.);
#1483=CARTESIAN_POINT('',(0.,0.,9.74999999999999));
#1484=DIRECTION('',(0.,0.,-1.));
#1485=DIRECTION('',(-1.,0.,0.));
#1486=AXIS2_PLACEMENT_3D('',#1483,#1484,#1485);
#1487=CIRCLE('',#1486,32.02);
#1488=EDGE_CURVE('E1718',#1463,#1480,#1487,.T.);
#1489=ORIENTED_EDGE('',*,*,#1488,.F.);
#1490=EDGE_LOOP('',(#1465,#1474,#1482,#1489));
#1491=FACE_BOUND('',#1490,.T.);
#1492=DIRECTION('',(0.,0.,1.));
#1493=VECTOR('',#1492,1.);
#1494=CARTESIAN_POINT('',(12.6102113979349,-29.4323456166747,5.52499999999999));
#1495=LINE('',#1494,#1493);
#1496=CARTESIAN_POINT('',(12.6102113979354,-29.4323456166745,1.29999999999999));
#1497=VERTEX_POINT('',#1496);
#1498=CARTESIAN_POINT('',(12.6102113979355,-29.4323456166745,9.74999999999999));
#1499=VERTEX_POINT('',#1498);
#1500=EDGE_CURVE('E1698',#1497,#1499,#1495,.T.);
#1501=ORIENTED_EDGE('',*,*,#1500,.F.);
#1502=CARTESIAN_POINT('',(0.,0.,1.3));
#1503=DIRECTION('',(0.,0.,1.));
#1504=DIRECTION('',(1.,0.,0.));
#1505=AXIS2_PLACEMENT_3D('',#1502,#1503,#1504);
#1506=CIRCLE('',#1505,32.02);
#1507=CARTESIAN_POINT('',(11.8950451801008,-29.7285771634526,1.29999999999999));
#1508=VERTEX_POINT('',#1507);
#1509=EDGE_CURVE('E1695',#1508,#1497,#1506,.T.);
#1510=ORIENTED_EDGE('',*,*,#1509,.F.);
#1511=DIRECTION('',(0.,0.,1.));
#1512=VECTOR('',#1511,1.);
#1513=CARTESIAN_POINT('',(11.8950451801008,-29.7285771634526,5.52499999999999));
#1514=LINE('',#1513,#1512);
#1515=CARTESIAN_POINT('',(11.8950451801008,-29.7285771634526,9.74999999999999));
#1516=VERTEX_POINT('',#1515);
#1517=EDGE_CURVE('E1689',#1516,#1508,#1514,.F.);
#1518=ORIENTED_EDGE('',*,*,#1517,.F.);
#1519=CARTESIAN_POINT('',(0.,0.,9.74999999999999));
#1520=DIRECTION('',(0.,0.,-1.));
#1521=DIRECTION('',(-1.,0.,0.));
#1522=AXIS2_PLACEMENT_3D('',#1519,#1520,#1521);
#1523=CIRCLE('',#1522,32.02);
#1524=EDGE_CURVE('E1694',#1499,#1516,#1523,.T.);
#1525=ORIENTED_EDGE('',*,*,#1524,.F.);
#1526=EDGE_LOOP('',(#1501,#1510,#1518,#1525));
#1527=FACE_BOUND('',#1526,.T.);
#1528=DIRECTION('',(0.,0.,1.));
#1529=VECTOR('',#1528,1.);
#1530=CARTESIAN_POINT('',(22.9135872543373,-22.3662227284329,5.52499999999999));
#1531=LINE('',#1530,#1529);
#1532=CARTESIAN_POINT('',(22.9135872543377,-22.3662227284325,1.29999999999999));
#1533=VERTEX_POINT('',#1532);
#1534=CARTESIAN_POINT('',(22.9135872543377,-22.3662227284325,9.74999999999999));
#1535=VERTEX_POINT('',#1534);
#1536=EDGE_CURVE('E1673',#1533,#1535,#1531,.T.);
#1537=ORIENTED_EDGE('',*,*,#1536,.F.);
#1538=CARTESIAN_POINT('',(0.,0.,1.3));
#1539=DIRECTION('',(0.,0.,1.));
#1540=DIRECTION('',(1.,0.,0.));
#1541=AXIS2_PLACEMENT_3D('',#1538,#1539,#1540);
#1542=CIRCLE('',#1541,32.02);
#1543=CARTESIAN_POINT('',(22.3662227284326,-22.9135872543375,1.29999999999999));
#1544=VERTEX_POINT('',#1543);
#1545=EDGE_CURVE('E1670',#1544,#1533,#1542,.T.);
#1546=ORIENTED_EDGE('',*,*,#1545,.F.);
#1547=DIRECTION('',(0.,0.,1.));
#1548=VECTOR('',#1547,1.);
#1549=CARTESIAN_POINT('',(22.3662227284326,-22.9135872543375,5.52499999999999));
#1550=LINE('',#1549,#1548);
#1551=CARTESIAN_POINT('',(22.3662227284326,-22.9135872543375,9.74999999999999));
#1552=VERTEX_POINT('',#1551);
#1553=EDGE_CURVE('E1663',#1552,#1544,#1550,.F.);
#1554=ORIENTED_EDGE('',*,*,#1553,.F.);
#1555=CARTESIAN_POINT('',(0.,0.,9.74999999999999));
#1556=DIRECTION('',(0.,0.,-1.));
#1557=DIRECTION('',(-1.,0.,0.));
#1558=AXIS2_PLACEMENT_3D('',#1555,#1556,#1557);
#1559=CIRCLE('',#1558,32.02);
#1560=EDGE_CURVE('E1674',#1535,#1552,#1559,.T.);
#1561=ORIENTED_EDGE('',*,*,#1560,.F.);
#1562=EDGE_LOOP('',(#1537,#1546,#1554,#1561));
#1563=FACE_BOUND('',#1562,.T.);
#1564=DIRECTION('',(0.,0.,1.));
#1565=VECTOR('',#1564,1.);
#1566=CARTESIAN_POINT('',(29.7285771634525,-11.8950451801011,5.52499999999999));
#1567=LINE('',#1566,#1565);
#1568=CARTESIAN_POINT('',(29.7285771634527,-11.8950451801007,1.29999999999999));
#1569=VERTEX_POINT('',#1568);
#1570=CARTESIAN_POINT('',(29.7285771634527,-11.8950451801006,9.74999999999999));
#1571=VERTEX_POINT('',#1570);
#1572=EDGE_CURVE('E1647',#1569,#1571,#1567,.T.);
#1573=ORIENTED_EDGE('',*,*,#1572,.F.);
#1574=CARTESIAN_POINT('',(0.,0.,1.3));
#1575=DIRECTION('',(0.,0.,1.));
#1576=DIRECTION('',(1.,0.,0.));
#1577=AXIS2_PLACEMENT_3D('',#1574,#1575,#1576);
#1578=CIRCLE('',#1577,32.02);
#1579=CARTESIAN_POINT('',(29.4323456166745,-12.6102113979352,1.29999999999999));
#1580=VERTEX_POINT('',#1579);
#1581=EDGE_CURVE('E1643',#1580,#1569,#1578,.T.);
#1582=ORIENTED_EDGE('',*,*,#1581,.F.);
#1583=DIRECTION('',(0.,0.,1.));
#1584=VECTOR('',#1583,1.);
#1585=CARTESIAN_POINT('',(29.4323456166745,-12.6102113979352,5.52499999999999));
#1586=LINE('',#1585,#1584);
#1587=CARTESIAN_POINT('',(29.4323456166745,-12.6102113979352,9.74999999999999));
#1588=VERTEX_POINT('',#1587);
#1589=EDGE_CURVE('E1644',#1588,#1580,#1586,.F.);
#1590=ORIENTED_EDGE('',*,*,#1589,.F.);
#1591=CARTESIAN_POINT('',(0.,0.,9.74999999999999));
#1592=DIRECTION('',(0.,0.,-1.));
#1593=DIRECTION('',(-1.,0.,0.));
#1594=AXIS2_PLACEMENT_3D('',#1591,#1592,#1593);
#1595=CIRCLE('',#1594,32.02);
#1596=EDGE_CURVE('E1646',#1571,#1588,#1595,.T.);
#1597=ORIENTED_EDGE('',*,*,#1596,.F.);
#1598=EDGE_LOOP('',(#1573,#1582,#1590,#1597));
#1599=FACE_BOUND('',#1598,.T.);
#1600=DIRECTION('',(0.,0.,1.));
#1601=VECTOR('',#1600,1.);
#1602=CARTESIAN_POINT('',(32.0176606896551,0.387045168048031,5.52499999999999));
#1603=LINE('',#1602,#1601);
#1604=CARTESIAN_POINT('',(32.0176606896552,0.387045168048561,1.29999999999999));
#1605=VERTEX_POINT('',#1604);
#1606=CARTESIAN_POINT('',(32.0176606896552,0.3870451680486,9.74999999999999));
#1607=VERTEX_POINT('',#1606);
#1608=EDGE_CURVE('E1626',#1605,#1607,#1603,.T.);
#1609=ORIENTED_EDGE('',*,*,#1608,.F.);
#1610=CARTESIAN_POINT('',(0.,0.,1.3));
#1611=DIRECTION('',(0.,0.,1.));
#1612=DIRECTION('',(1.,0.,0.));
#1613=AXIS2_PLACEMENT_3D('',#1610,#1611,#1612);
#1614=CIRCLE('',#1613,32.02);
#1615=CARTESIAN_POINT('',(32.0176606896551,-0.387045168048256,1.29999999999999));
#1616=VERTEX_POINT('',#1615);
#1617=EDGE_CURVE('E1619',#1616,#1605,#1614,.T.);
#1618=ORIENTED_EDGE('',*,*,#1617,.F.);
#1619=DIRECTION('',(0.,0.,1.));
#1620=VECTOR('',#1619,1.);
#1621=CARTESIAN_POINT('',(32.0176606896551,-0.387045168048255,5.52499999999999));
#1622=LINE('',#1621,#1620);
#1623=CARTESIAN_POINT('',(32.0176606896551,-0.387045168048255,9.74999999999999));
#1624=VERTEX_POINT('',#1623);
#1625=EDGE_CURVE('E1620',#1624,#1616,#1622,.F.);
#1626=ORIENTED_EDGE('',*,*,#1625,.F.);
#1627=CARTESIAN_POINT('',(0.,0.,9.74999999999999));
#1628=DIRECTION('',(0.,0.,-1.));
#1629=DIRECTION('',(-1.,0.,0.));
#1630=AXIS2_PLACEMENT_3D('',#1627,#1628,#1629);
#1631=CIRCLE('',#1630,32.02);
#1632=EDGE_CURVE('E1623',#1607,#1624,#1631,.T.);
#1633=ORIENTED_EDGE('',*,*,#1632,.F.);
#1634=EDGE_LOOP('',(#1609,#1618,#1626,#1633));
#1635=FACE_BOUND('',#1634,.T.);
#1636=DIRECTION('',(0.,0.,1.));
#1637=VECTOR('',#1636,1.);
#1638=CARTESIAN_POINT('',(29.4323456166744,12.6102113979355,5.52499999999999));
#1639=LINE('',#1638,#1637);
#1640=CARTESIAN_POINT('',(29.4323456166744,12.6102113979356,1.29999999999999));
#1641=VERTEX_POINT('',#1640);
#1642=CARTESIAN_POINT('',(29.4323456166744,12.6102113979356,9.74999999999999));
#1643=VERTEX_POINT('',#1642);
#1644=EDGE_CURVE('E1604',#1641,#1643,#1639,.T.);
#1645=ORIENTED_EDGE('',*,*,#1644,.F.);
#1646=CARTESIAN_POINT('',(0.,0.,1.3));
#1647=DIRECTION('',(0.,0.,1.));
#1648=DIRECTION('',(1.,0.,0.));
#1649=AXIS2_PLACEMENT_3D('',#1646,#1647,#1648);
#1650=CIRCLE('',#1649,32.02);
#1651=CARTESIAN_POINT('',(29.7285771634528,11.8950451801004,1.29999999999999));
#1652=VERTEX_POINT('',#1651);
#1653=EDGE_CURVE('E1599',#1652,#1641,#1650,.T.);
#1654=ORIENTED_EDGE('',*,*,#1653,.F.);
#1655=DIRECTION('',(0.,0.,1.));
#1656=VECTOR('',#1655,1.);
#1657=CARTESIAN_POINT('',(29.7285771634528,11.8950451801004,5.52499999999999));
#1658=LINE('',#1657,#1656);
#1659=CARTESIAN_POINT('',(29.7285771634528,11.8950451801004,9.74999999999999));
#1660=VERTEX_POINT('',#1659);
#1661=EDGE_CURVE('E1595',#1660,#1652,#1658,.F.);
#1662=ORIENTED_EDGE('',*,*,#1661,.F.);
#1663=CARTESIAN_POINT('',(0.,0.,9.74999999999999));
#1664=DIRECTION('',(0.,0.,-1.));
#1665=DIRECTION('',(-1.,0.,0.));
#1666=AXIS2_PLACEMENT_3D('',#1663,#1664,#1665);
#1667=CIRCLE('',#1666,32.02);
#1668=EDGE_CURVE('E1598',#1643,#1660,#1667,.T.);
#1669=ORIENTED_EDGE('',*,*,#1668,.F.);
#1670=EDGE_LOOP('',(#1645,#1654,#1662,#1669));
#1671=FACE_BOUND('',#1670,.T.);
#1672=DIRECTION('',(0.,0.,1.));
#1673=VECTOR('',#1672,1.);
#1674=CARTESIAN_POINT('',(22.3662227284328,22.9135872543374,5.52499999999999));
#1675=LINE('',#1674,#1673);
#1676=CARTESIAN_POINT('',(22.3662227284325,22.9135872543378,1.29999999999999));
#1677=VERTEX_POINT('',#1676);
#1678=CARTESIAN_POINT('',(22.3662227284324,22.9135872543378,9.74999999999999));
#1679=VERTEX_POINT('',#1678);
#1680=EDGE_CURVE('E1577',#1677,#1679,#1675,.T.);
#1681=ORIENTED_EDGE('',*,*,#1680,.F.);
#1682=CARTESIAN_POINT('',(0.,0.,1.3));
#1683=DIRECTION('',(0.,0.,1.));
#1684=DIRECTION('',(1.,0.,0.));
#1685=AXIS2_PLACEMENT_3D('',#1682,#1683,#1684);
#1686=CIRCLE('',#1685,32.02);
#1687=CARTESIAN_POINT('',(22.9135872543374,22.3662227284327,1.29999999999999));
#1688=VERTEX_POINT('',#1687);
#1689=EDGE_CURVE('E1571',#1688,#1677,#1686,.T.);
#1690=ORIENTED_EDGE('',*,*,#1689,.F.);
#1691=DIRECTION('',(0.,0.,1.));
#1692=VECTOR('',#1691,1.);
#1693=CARTESIAN_POINT('',(22.9135872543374,22.3662227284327,5.52499999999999));
#1694=LINE('',#1693,#1692);
#1695=CARTESIAN_POINT('',(22.9135872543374,22.3662227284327,9.74999999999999));
#1696=VERTEX_POINT('',#1695);
#1697=EDGE_CURVE('E1568',#1696,#1688,#1694,.F.);
#1698=ORIENTED_EDGE('',*,*,#1697,.F.);
#1699=CARTESIAN_POINT('',(0.,0.,9.74999999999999));
#1700=DIRECTION('',(0.,0.,-1.));
#1701=DIRECTION('',(-1.,0.,0.));
#1702=AXIS2_PLACEMENT_3D('',#1699,#1700,#1701);
#1703=CIRCLE('',#1702,32.02);
#1704=EDGE_CURVE('E1572',#1679,#1696,#1703,.T.);
#1705=ORIENTED_EDGE('',*,*,#1704,.F.);
#1706=EDGE_LOOP('',(#1681,#1690,#1698,#1705));
#1707=FACE_BOUND('',#1706,.T.);
#1708=DIRECTION('',(0.,0.,1.));
#1709=VECTOR('',#1708,1.);
#1710=CARTESIAN_POINT('',(11.895045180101,29.7285771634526,5.52499999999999));
#1711=LINE('',#1710,#1709);
#1712=CARTESIAN_POINT('',(11.8950451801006,29.7285771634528,1.29999999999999));
#1713=VERTEX_POINT('',#1712);
#1714=CARTESIAN_POINT('',(11.8950451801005,29.7285771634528,9.74999999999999));
#1715=VERTEX_POINT('',#1714);
#1716=EDGE_CURVE('E1553',#1713,#1715,#1711,.T.);
#1717=ORIENTED_EDGE('',*,*,#1716,.F.);
#1718=CARTESIAN_POINT('',(0.,0.,1.3));
#1719=DIRECTION('',(0.,0.,1.));
#1720=DIRECTION('',(1.,0.,0.));
#1721=AXIS2_PLACEMENT_3D('',#1718,#1719,#1720);
#1722=CIRCLE('',#1721,32.02);
#1723=CARTESIAN_POINT('',(12.6102113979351,29.4323456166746,1.29999999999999));
#1724=VERTEX_POINT('',#1723);
#1725=EDGE_CURVE('E1548',#1724,#1713,#1722,.T.);
#1726=ORIENTED_EDGE('',*,*,#1725,.F.);
#1727=DIRECTION('',(0.,0.,1.));
#1728=VECTOR('',#1727,1.);
#1729=CARTESIAN_POINT('',(12.6102113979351,29.4323456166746,5.52499999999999));
#1730=LINE('',#1729,#1728);
#1731=CARTESIAN_POINT('',(12.6102113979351,29.4323456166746,9.74999999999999));
#1732=VERTEX_POINT('',#1731);
#1733=EDGE_CURVE('E1544',#1732,#1724,#1730,.F.);
#1734=ORIENTED_EDGE('',*,*,#1733,.F.);
#1735=CARTESIAN_POINT('',(0.,0.,9.74999999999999));
#1736=DIRECTION('',(0.,0.,-1.));
#1737=DIRECTION('',(-1.,0.,0.));
#1738=AXIS2_PLACEMENT_3D('',#1735,#1736,#1737);
#1739=CIRCLE('',#1738,32.02);
#1740=EDGE_CURVE('E1551',#1715,#1732,#1739,.T.);
#1741=ORIENTED_EDGE('',*,*,#1740,.F.);
#1742=EDGE_LOOP('',(#1717,#1726,#1734,#1741));
#1743=FACE_BOUND('',#1742,.T.);
#1744=CARTESIAN_POINT('',(0.,0.,9.775));
#1745=DIRECTION('',(0.,0.,1.));
#1746=DIRECTION('',(1.,0.,0.));
#1747=AXIS2_PLACEMENT_3D('',#1744,#1745,#1746);
#1748=CIRCLE('',#1747,32.02);
#1749=CARTESIAN_POINT('',(32.02,0.,9.775));
#1750=VERTEX_POINT('',#1749);
#1751=EDGE_CURVE('E1440',#1750,#1750,#1748,.T.);
#1752=ORIENTED_EDGE('',*,*,#1751,.F.);
#1753=EDGE_LOOP('',(#1752));
#1754=FACE_BOUND('',#1753,.T.);
#1755=CARTESIAN_POINT('',(0.,0.,-9.77500000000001));
#1756=DIRECTION('',(0.,0.,1.));
#1757=DIRECTION('',(1.,0.,0.));
#1758=AXIS2_PLACEMENT_3D('',#1755,#1756,#1757);
#1759=CIRCLE('',#1758,32.02);
#1760=CARTESIAN_POINT('',(32.02,0.,-9.77500000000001));
#1761=VERTEX_POINT('',#1760);
#1762=EDGE_CURVE('E1434',#1761,#1761,#1759,.T.);
#1763=ORIENTED_EDGE('',*,*,#1762,.T.);
#1764=EDGE_LOOP('',(#1763));
#1765=FACE_BOUND('',#1764,.T.);
#1766=DIRECTION('',(0.,0.,1.));
#1767=VECTOR('',#1766,1.);
#1768=CARTESIAN_POINT('',(0.387045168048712,32.0176606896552,0.));
#1769=LINE('',#1768,#1767);
#1770=CARTESIAN_POINT('',(0.387045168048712,32.0176606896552,-9.75000000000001));
#1771=VERTEX_POINT('',#1770);
#1772=CARTESIAN_POINT('',(0.387045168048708,32.0176606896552,-1.30000000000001));
#1773=VERTEX_POINT('',#1772);
#1774=EDGE_CURVE('E1448',#1771,#1773,#1769,.T.);
#1775=ORIENTED_EDGE('',*,*,#1774,.T.);
#1776=CARTESIAN_POINT('',(0.,0.,-1.30000000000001));
#1777=DIRECTION('',(0.,0.,-1.));
#1778=DIRECTION('',(-1.,0.,0.));
#1779=AXIS2_PLACEMENT_3D('',#1776,#1777,#1778);
#1780=CIRCLE('',#1779,32.02);
#1781=CARTESIAN_POINT('',(-0.387045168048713,32.0176606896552,-1.30000000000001));
#1782=VERTEX_POINT('',#1781);
#1783=EDGE_CURVE('E1454',#1773,#1782,#1780,.F.);
#1784=ORIENTED_EDGE('',*,*,#1783,.T.);
#1785=DIRECTION('',(0.,0.,1.));
#1786=VECTOR('',#1785,1.);
#1787=CARTESIAN_POINT('',(-0.387045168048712,32.0176606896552,0.));
#1788=LINE('',#1787,#1786);
#1789=CARTESIAN_POINT('',(-0.387045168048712,32.0176606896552,-9.75000000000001));
#1790=VERTEX_POINT('',#1789);
#1791=EDGE_CURVE('E1449',#1782,#1790,#1788,.F.);
#1792=ORIENTED_EDGE('',*,*,#1791,.T.);
#1793=CARTESIAN_POINT('',(0.,0.,-9.75000000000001));
#1794=DIRECTION('',(0.,0.,1.));
#1795=DIRECTION('',(1.,0.,0.));
#1796=AXIS2_PLACEMENT_3D('',#1793,#1794,#1795);
#1797=CIRCLE('',#1796,32.02);
#1798=EDGE_CURVE('E1520',#1790,#1771,#1797,.F.);
#1799=ORIENTED_EDGE('',*,*,#1798,.T.);
#1800=EDGE_LOOP('',(#1775,#1784,#1792,#1799));
#1801=FACE_BOUND('',#1800,.T.);
#1802=CARTESIAN_POINT('',(0.,0.,1.3));
#1803=DIRECTION('',(0.,0.,1.));
#1804=DIRECTION('',(1.,0.,0.));
#1805=AXIS2_PLACEMENT_3D('',#1802,#1803,#1804);
#1806=CIRCLE('',#1805,32.02);
#1807=CARTESIAN_POINT('',(-0.387045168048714,32.0176606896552,1.29999999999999));
#1808=VERTEX_POINT('',#1807);
#1809=CARTESIAN_POINT('',(0.387045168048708,32.0176606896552,1.29999999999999));
#1810=VERTEX_POINT('',#1809);
#1811=EDGE_CURVE('E1456',#1808,#1810,#1806,.F.);
#1812=ORIENTED_EDGE('',*,*,#1811,.T.);
#1813=DIRECTION('',(0.,0.,1.));
#1814=VECTOR('',#1813,1.);
#1815=CARTESIAN_POINT('',(0.387045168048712,32.0176606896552,5.525));
#1816=LINE('',#1815,#1814);
#1817=CARTESIAN_POINT('',(0.387045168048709,32.0176606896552,9.74999999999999));
#1818=VERTEX_POINT('',#1817);
#1819=EDGE_CURVE('E1464',#1810,#1818,#1816,.T.);
#1820=ORIENTED_EDGE('',*,*,#1819,.T.);
#1821=CARTESIAN_POINT('',(0.,0.,9.74999999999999));
#1822=DIRECTION('',(0.,0.,-1.));
#1823=DIRECTION('',(-1.,0.,0.));
#1824=AXIS2_PLACEMENT_3D('',#1821,#1822,#1823);
#1825=CIRCLE('',#1824,32.02);
#1826=CARTESIAN_POINT('',(-0.387045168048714,32.0176606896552,9.74999999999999));
#1827=VERTEX_POINT('',#1826);
#1828=EDGE_CURVE('E1463',#1818,#1827,#1825,.F.);
#1829=ORIENTED_EDGE('',*,*,#1828,.T.);
#1830=DIRECTION('',(0.,0.,1.));
#1831=VECTOR('',#1830,1.);
#1832=CARTESIAN_POINT('',(-0.387045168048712,32.0176606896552,5.525));
#1833=LINE('',#1832,#1831);
#1834=EDGE_CURVE('E1451',#1827,#1808,#1833,.F.);
#1835=ORIENTED_EDGE('',*,*,#1834,.T.);
#1836=EDGE_LOOP('',(#1812,#1820,#1829,#1835));
#1837=FACE_BOUND('',#1836,.T.);
#1838=CARTESIAN_POINT('',(0.,0.,-1.30000000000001));
#1839=DIRECTION('',(0.,0.,-1.));
#1840=DIRECTION('',(-1.,0.,0.));
#1841=AXIS2_PLACEMENT_3D('',#1838,#1839,#1840);
#1842=CIRCLE('',#1841,32.02);
#1843=CARTESIAN_POINT('',(11.895045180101,29.7285771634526,-1.30000000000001));
#1844=VERTEX_POINT('',#1843);
#1845=CARTESIAN_POINT('',(12.6102113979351,29.4323456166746,-1.30000000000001));
#1846=VERTEX_POINT('',#1845);
#1847=EDGE_CURVE('E1569',#1844,#1846,#1842,.T.);
#1848=ORIENTED_EDGE('',*,*,#1847,.F.);
#1849=DIRECTION('',(0.,0.,1.));
#1850=VECTOR('',#1849,1.);
#1851=CARTESIAN_POINT('',(11.895045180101,29.7285771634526,-5.52500000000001));
#1852=LINE('',#1851,#1850);
#1853=CARTESIAN_POINT('',(11.8950451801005,29.7285771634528,-9.75000000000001));
#1854=VERTEX_POINT('',#1853);
#1855=EDGE_CURVE('E1564',#1854,#1844,#1852,.T.);
#1856=ORIENTED_EDGE('',*,*,#1855,.F.);
#1857=CARTESIAN_POINT('',(0.,0.,-9.75000000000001));
#1858=DIRECTION('',(0.,0.,1.));
#1859=DIRECTION('',(1.,0.,0.));
#1860=AXIS2_PLACEMENT_3D('',#1857,#1858,#1859);
#1861=CIRCLE('',#1860,32.02);
#1862=CARTESIAN_POINT('',(12.6102113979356,29.4323456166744,-9.75000000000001));
#1863=VERTEX_POINT('',#1862);
#1864=EDGE_CURVE('E1560',#1863,#1854,#1861,.T.);
#1865=ORIENTED_EDGE('',*,*,#1864,.F.);
#1866=DIRECTION('',(0.,0.,1.));
#1867=VECTOR('',#1866,1.);
#1868=CARTESIAN_POINT('',(12.6102113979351,29.4323456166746,-5.52500000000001));
#1869=LINE('',#1868,#1867);
#1870=EDGE_CURVE('E1558',#1846,#1863,#1869,.F.);
#1871=ORIENTED_EDGE('',*,*,#1870,.F.);
#1872=EDGE_LOOP('',(#1848,#1856,#1865,#1871));
#1873=FACE_BOUND('',#1872,.T.);
#1874=CARTESIAN_POINT('',(0.,0.,-1.30000000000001));
#1875=DIRECTION('',(0.,0.,-1.));
#1876=DIRECTION('',(-1.,0.,0.));
#1877=AXIS2_PLACEMENT_3D('',#1874,#1875,#1876);
#1878=CIRCLE('',#1877,32.02);
#1879=CARTESIAN_POINT('',(22.3662227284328,22.9135872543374,-1.30000000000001));
#1880=VERTEX_POINT('',#1879);
#1881=CARTESIAN_POINT('',(22.9135872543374,22.3662227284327,-1.30000000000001));
#1882=VERTEX_POINT('',#1881);
#1883=EDGE_CURVE('E1588',#1880,#1882,#1878,.T.);
#1884=ORIENTED_EDGE('',*,*,#1883,.F.);
#1885=DIRECTION('',(0.,0.,1.));
#1886=VECTOR('',#1885,1.);
#1887=CARTESIAN_POINT('',(22.3662227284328,22.9135872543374,-5.52500000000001));
#1888=LINE('',#1887,#1886);
#1889=CARTESIAN_POINT('',(22.3662227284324,22.9135872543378,-9.75000000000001));
#1890=VERTEX_POINT('',#1889);
#1891=EDGE_CURVE('E1590',#1890,#1880,#1888,.T.);
#1892=ORIENTED_EDGE('',*,*,#1891,.F.);
#1893=CARTESIAN_POINT('',(0.,0.,-9.75000000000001));
#1894=DIRECTION('',(0.,0.,1.));
#1895=DIRECTION('',(1.,0.,0.));
#1896=AXIS2_PLACEMENT_3D('',#1893,#1894,#1895);
#1897=CIRCLE('',#1896,32.02);
#1898=CARTESIAN_POINT('',(22.9135872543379,22.3662227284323,-9.75000000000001));
#1899=VERTEX_POINT('',#1898);
#1900=EDGE_CURVE('E1582',#1899,#1890,#1897,.T.);
#1901=ORIENTED_EDGE('',*,*,#1900,.F.);
#1902=DIRECTION('',(0.,0.,1.));
#1903=VECTOR('',#1902,1.);
#1904=CARTESIAN_POINT('',(22.9135872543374,22.3662227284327,-5.52500000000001));
#1905=LINE('',#1904,#1903);
#1906=EDGE_CURVE('E1584',#1882,#1899,#1905,.F.);
#1907=ORIENTED_EDGE('',*,*,#1906,.F.);
#1908=EDGE_LOOP('',(#1884,#1892,#1901,#1907));
#1909=FACE_BOUND('',#1908,.T.);
#1910=CARTESIAN_POINT('',(0.,0.,-1.30000000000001));
#1911=DIRECTION('',(0.,0.,-1.));
#1912=DIRECTION('',(-1.,0.,0.));
#1913=AXIS2_PLACEMENT_3D('',#1910,#1911,#1912);
#1914=CIRCLE('',#1913,32.02);
#1915=CARTESIAN_POINT('',(29.4323456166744,12.6102113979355,-1.30000000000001));
#1916=VERTEX_POINT('',#1915);
#1917=CARTESIAN_POINT('',(29.7285771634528,11.8950451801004,-1.30000000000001));
#1918=VERTEX_POINT('',#1917);
#1919=EDGE_CURVE('E1614',#1916,#1918,#1914,.T.);
#1920=ORIENTED_EDGE('',*,*,#1919,.F.);
#1921=DIRECTION('',(0.,0.,1.));
#1922=VECTOR('',#1921,1.);
#1923=CARTESIAN_POINT('',(29.4323456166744,12.6102113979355,-5.52500000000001));
#1924=LINE('',#1923,#1922);
#1925=CARTESIAN_POINT('',(29.4323456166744,12.6102113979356,-9.75000000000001));
#1926=VERTEX_POINT('',#1925);
#1927=EDGE_CURVE('E1613',#1926,#1916,#1924,.T.);
#1928=ORIENTED_EDGE('',*,*,#1927,.F.);
#1929=CARTESIAN_POINT('',(0.,0.,-9.75000000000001));
#1930=DIRECTION('',(0.,0.,1.));
#1931=DIRECTION('',(1.,0.,0.));
#1932=AXIS2_PLACEMENT_3D('',#1929,#1930,#1931);
#1933=CIRCLE('',#1932,32.02);
#1934=CARTESIAN_POINT('',(29.7285771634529,11.8950451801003,-9.75000000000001));
#1935=VERTEX_POINT('',#1934);
#1936=EDGE_CURVE('E1601',#1935,#1926,#1933,.T.);
#1937=ORIENTED_EDGE('',*,*,#1936,.F.);
#1938=DIRECTION('',(0.,0.,1.));
#1939=VECTOR('',#1938,1.);
#1940=CARTESIAN_POINT('',(29.7285771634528,11.8950451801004,-5.52500000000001));
#1941=LINE('',#1940,#1939);
#1942=EDGE_CURVE('E1606',#1918,#1935,#1941,.F.);
#1943=ORIENTED_EDGE('',*,*,#1942,.F.);
#1944=EDGE_LOOP('',(#1920,#1928,#1937,#1943));
#1945=FACE_BOUND('',#1944,.T.);
#1946=CARTESIAN_POINT('',(0.,0.,-1.30000000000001));
#1947=DIRECTION('',(0.,0.,-1.));
#1948=DIRECTION('',(-1.,0.,0.));
#1949=AXIS2_PLACEMENT_3D('',#1946,#1947,#1948);
#1950=CIRCLE('',#1949,32.02);
#1951=CARTESIAN_POINT('',(32.0176606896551,0.387045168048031,-1.30000000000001));
#1952=VERTEX_POINT('',#1951);
#1953=CARTESIAN_POINT('',(32.0176606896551,-0.387045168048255,-1.30000000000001));
#1954=VERTEX_POINT('',#1953);
#1955=EDGE_CURVE('E1639',#1952,#1954,#1950,.T.);
#1956=ORIENTED_EDGE('',*,*,#1955,.F.);
#1957=DIRECTION('',(0.,0.,1.));
#1958=VECTOR('',#1957,1.);
#1959=CARTESIAN_POINT('',(32.0176606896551,0.387045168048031,-5.52500000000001));
#1960=LINE('',#1959,#1958);
#1961=CARTESIAN_POINT('',(32.0176606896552,0.3870451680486,-9.75000000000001));
#1962=VERTEX_POINT('',#1961);
#1963=EDGE_CURVE('E1633',#1962,#1952,#1960,.T.);
#1964=ORIENTED_EDGE('',*,*,#1963,.F.);
#1965=CARTESIAN_POINT('',(0.,0.,-9.75000000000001));
#1966=DIRECTION('',(0.,0.,1.));
#1967=DIRECTION('',(1.,0.,0.));
#1968=AXIS2_PLACEMENT_3D('',#1965,#1966,#1967);
#1969=CIRCLE('',#1968,32.02);
#1970=CARTESIAN_POINT('',(32.0176606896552,-0.387045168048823,-9.75000000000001));
#1971=VERTEX_POINT('',#1970);
#1972=EDGE_CURVE('E1628',#1971,#1962,#1969,.T.);
#1973=ORIENTED_EDGE('',*,*,#1972,.F.);
#1974=DIRECTION('',(0.,0.,1.));
#1975=VECTOR('',#1974,1.);
#1976=CARTESIAN_POINT('',(32.0176606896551,-0.387045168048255,-5.52500000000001));
#1977=LINE('',#1976,#1975);
#1978=EDGE_CURVE('E1635',#1954,#1971,#1977,.F.);
#1979=ORIENTED_EDGE('',*,*,#1978,.F.);
#1980=EDGE_LOOP('',(#1956,#1964,#1973,#1979));
#1981=FACE_BOUND('',#1980,.T.);
#1982=CARTESIAN_POINT('',(0.,0.,-1.30000000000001));
#1983=DIRECTION('',(0.,0.,-1.));
#1984=DIRECTION('',(-1.,0.,0.));
#1985=AXIS2_PLACEMENT_3D('',#1982,#1983,#1984);
#1986=CIRCLE('',#1985,32.02);
#1987=CARTESIAN_POINT('',(29.7285771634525,-11.8950451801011,-1.30000000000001));
#1988=VERTEX_POINT('',#1987);
#1989=CARTESIAN_POINT('',(29.4323456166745,-12.6102113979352,-1.30000000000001));
#1990=VERTEX_POINT('',#1989);
#1991=EDGE_CURVE('E1665',#1988,#1990,#1986,.T.);
#1992=ORIENTED_EDGE('',*,*,#1991,.F.);
#1993=DIRECTION('',(0.,0.,1.));
#1994=VECTOR('',#1993,1.);
#1995=CARTESIAN_POINT('',(29.7285771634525,-11.8950451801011,-5.52500000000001));
#1996=LINE('',#1995,#1994);
#1997=CARTESIAN_POINT('',(29.7285771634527,-11.8950451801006,-9.75000000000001));
#1998=VERTEX_POINT('',#1997);
#1999=EDGE_CURVE('E1659',#1998,#1988,#1996,.T.);
#2000=ORIENTED_EDGE('',*,*,#1999,.F.);
#2001=CARTESIAN_POINT('',(0.,0.,-9.75000000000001));
#2002=DIRECTION('',(0.,0.,1.));
#2003=DIRECTION('',(1.,0.,0.));
#2004=AXIS2_PLACEMENT_3D('',#2001,#2002,#2003);
#2005=CIRCLE('',#2004,32.02);
#2006=CARTESIAN_POINT('',(29.4323456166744,-12.6102113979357,-9.75000000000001));
#2007=VERTEX_POINT('',#2006);
#2008=EDGE_CURVE('E1652',#2007,#1998,#2005,.T.);
#2009=ORIENTED_EDGE('',*,*,#2008,.F.);
#2010=DIRECTION('',(0.,0.,1.));
#2011=VECTOR('',#2010,1.);
#2012=CARTESIAN_POINT('',(29.4323456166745,-12.6102113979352,-5.52500000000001));
#2013=LINE('',#2012,#2011);
#2014=EDGE_CURVE('E1657',#1990,#2007,#2013,.F.);
#2015=ORIENTED_EDGE('',*,*,#2014,.F.);
#2016=EDGE_LOOP('',(#1992,#2000,#2009,#2015));
#2017=FACE_BOUND('',#2016,.T.);
#2018=CARTESIAN_POINT('',(0.,0.,-1.30000000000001));
#2019=DIRECTION('',(0.,0.,-1.));
#2020=DIRECTION('',(-1.,0.,0.));
#2021=AXIS2_PLACEMENT_3D('',#2018,#2019,#2020);
#2022=CIRCLE('',#2021,32.02);
#2023=CARTESIAN_POINT('',(22.9135872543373,-22.3662227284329,-1.30000000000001));
#2024=VERTEX_POINT('',#2023);
#2025=CARTESIAN_POINT('',(22.3662227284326,-22.9135872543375,-1.30000000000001));
#2026=VERTEX_POINT('',#2025);
#2027=EDGE_CURVE('E1688',#2024,#2026,#2022,.T.);
#2028=ORIENTED_EDGE('',*,*,#2027,.F.);
#2029=DIRECTION('',(0.,0.,1.));
#2030=VECTOR('',#2029,1.);
#2031=CARTESIAN_POINT('',(22.9135872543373,-22.3662227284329,-5.52500000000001));
#2032=LINE('',#2031,#2030);
#2033=CARTESIAN_POINT('',(22.9135872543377,-22.3662227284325,-9.75000000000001));
#2034=VERTEX_POINT('',#2033);
#2035=EDGE_CURVE('E1681',#2034,#2024,#2032,.T.);
#2036=ORIENTED_EDGE('',*,*,#2035,.F.);
#2037=CARTESIAN_POINT('',(0.,0.,-9.75000000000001));
#2038=DIRECTION('',(0.,0.,1.));
#2039=DIRECTION('',(1.,0.,0.));
#2040=AXIS2_PLACEMENT_3D('',#2037,#2038,#2039);
#2041=CIRCLE('',#2040,32.02);
#2042=CARTESIAN_POINT('',(22.3662227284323,-22.913587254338,-9.75000000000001));
#2043=VERTEX_POINT('',#2042);
#2044=EDGE_CURVE('E1679',#2043,#2034,#2041,.T.);
#2045=ORIENTED_EDGE('',*,*,#2044,.F.);
#2046=DIRECTION('',(0.,0.,1.));
#2047=VECTOR('',#2046,1.);
#2048=CARTESIAN_POINT('',(22.3662227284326,-22.9135872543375,-5.52500000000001));
#2049=LINE('',#2048,#2047);
#2050=EDGE_CURVE('E1676',#2026,#2043,#2049,.F.);
#2051=ORIENTED_EDGE('',*,*,#2050,.F.);
#2052=EDGE_LOOP('',(#2028,#2036,#2045,#2051));
#2053=FACE_BOUND('',#2052,.T.);
#2054=CARTESIAN_POINT('',(0.,0.,-1.30000000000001));
#2055=DIRECTION('',(0.,0.,-1.));
#2056=DIRECTION('',(-1.,0.,0.));
#2057=AXIS2_PLACEMENT_3D('',#2054,#2055,#2056);
#2058=CIRCLE('',#2057,32.02);
#2059=CARTESIAN_POINT('',(12.6102113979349,-29.4323456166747,-1.30000000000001));
#2060=VERTEX_POINT('',#2059);
#2061=CARTESIAN_POINT('',(11.8950451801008,-29.7285771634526,-1.30000000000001));
#2062=VERTEX_POINT('',#2061);
#2063=EDGE_CURVE('E1708',#2060,#2062,#2058,.T.);
#2064=ORIENTED_EDGE('',*,*,#2063,.F.);
#2065=DIRECTION('',(0.,0.,1.));
#2066=VECTOR('',#2065,1.);
#2067=CARTESIAN_POINT('',(12.6102113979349,-29.4323456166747,-5.52500000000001));
#2068=LINE('',#2067,#2066);
#2069=CARTESIAN_POINT('',(12.6102113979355,-29.4323456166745,-9.75000000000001));
#2070=VERTEX_POINT('',#2069);
#2071=EDGE_CURVE('E1710',#2070,#2060,#2068,.T.);
#2072=ORIENTED_EDGE('',*,*,#2071,.F.);
#2073=CARTESIAN_POINT('',(0.,0.,-9.75000000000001));
#2074=DIRECTION('',(0.,0.,1.));
#2075=DIRECTION('',(1.,0.,0.));
#2076=AXIS2_PLACEMENT_3D('',#2073,#2074,#2075);
#2077=CIRCLE('',#2076,32.02);
#2078=CARTESIAN_POINT('',(11.8950451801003,-29.7285771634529,-9.75000000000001));
#2079=VERTEX_POINT('',#2078);
#2080=EDGE_CURVE('E1701',#2079,#2070,#2077,.T.);
#2081=ORIENTED_EDGE('',*,*,#2080,.F.);
#2082=DIRECTION('',(0.,0.,1.));
#2083=VECTOR('',#2082,1.);
#2084=CARTESIAN_POINT('',(11.8950451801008,-29.7285771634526,-5.52500000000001));
#2085=LINE('',#2084,#2083);
#2086=EDGE_CURVE('E1703',#2062,#2079,#2085,.F.);
#2087=ORIENTED_EDGE('',*,*,#2086,.F.);
#2088=EDGE_LOOP('',(#2064,#2072,#2081,#2087));
#2089=FACE_BOUND('',#2088,.T.);
#2090=CARTESIAN_POINT('',(0.,0.,-1.30000000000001));
#2091=DIRECTION('',(0.,0.,-1.));
#2092=DIRECTION('',(-1.,0.,0.));
#2093=AXIS2_PLACEMENT_3D('',#2090,#2091,#2092);
#2094=CIRCLE('',#2093,32.02);
#2095=CARTESIAN_POINT('',(0.38704516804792,-32.0176606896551,-1.30000000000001));
#2096=VERTEX_POINT('',#2095);
#2097=CARTESIAN_POINT('',(-0.387045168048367,-32.0176606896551,-1.30000000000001));
#2098=VERTEX_POINT('',#2097);
#2099=EDGE_CURVE('E1734',#2096,#2098,#2094,.T.);
#2100=ORIENTED_EDGE('',*,*,#2099,.F.);
#2101=DIRECTION('',(0.,0.,1.));
#2102=VECTOR('',#2101,1.);
#2103=CARTESIAN_POINT('',(0.38704516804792,-32.0176606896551,-5.52500000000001));
#2104=LINE('',#2103,#2102);
#2105=CARTESIAN_POINT('',(0.387045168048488,-32.0176606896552,-9.75000000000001));
#2106=VERTEX_POINT('',#2105);
#2107=EDGE_CURVE('E1732',#2106,#2096,#2104,.T.);
#2108=ORIENTED_EDGE('',*,*,#2107,.F.);
#2109=CARTESIAN_POINT('',(0.,0.,-9.75000000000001));
#2110=DIRECTION('',(0.,0.,1.));
#2111=DIRECTION('',(1.,0.,0.));
#2112=AXIS2_PLACEMENT_3D('',#2109,#2110,#2111);
#2113=CIRCLE('',#2112,32.02);
#2114=CARTESIAN_POINT('',(-0.387045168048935,-32.0176606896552,-9.75000000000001));
#2115=VERTEX_POINT('',#2114);
#2116=EDGE_CURVE('E1722',#2115,#2106,#2113,.T.);
#2117=ORIENTED_EDGE('',*,*,#2116,.F.);
#2118=DIRECTION('',(0.,0.,1.));
#2119=VECTOR('',#2118,1.);
#2120=CARTESIAN_POINT('',(-0.387045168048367,-32.0176606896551,-5.52500000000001));
#2121=LINE('',#2120,#2119);
#2122=EDGE_CURVE('E1727',#2098,#2115,#2121,.F.);
#2123=ORIENTED_EDGE('',*,*,#2122,.F.);
#2124=EDGE_LOOP('',(#2100,#2108,#2117,#2123));
#2125=FACE_BOUND('',#2124,.T.);
#2126=CARTESIAN_POINT('',(0.,0.,-1.30000000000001));
#2127=DIRECTION('',(0.,0.,-1.));
#2128=DIRECTION('',(-1.,0.,0.));
#2129=AXIS2_PLACEMENT_3D('',#2126,#2127,#2128);
#2130=CIRCLE('',#2129,32.02);
#2131=CARTESIAN_POINT('',(-11.8950451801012,-29.7285771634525,-1.30000000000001));
#2132=VERTEX_POINT('',#2131);
#2133=CARTESIAN_POINT('',(-12.6102113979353,-29.4323456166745,-1.30000000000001));
#2134=VERTEX_POINT('',#2133);
#2135=EDGE_CURVE('E1756',#2132,#2134,#2130,.T.);
#2136=ORIENTED_EDGE('',*,*,#2135,.F.);
#2137=DIRECTION('',(0.,0.,1.));
#2138=VECTOR('',#2137,1.);
#2139=CARTESIAN_POINT('',(-11.8950451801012,-29.7285771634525,-5.52500000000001));
#2140=LINE('',#2139,#2138);
#2141=CARTESIAN_POINT('',(-11.8950451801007,-29.7285771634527,-9.75000000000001));
#2142=VERTEX_POINT('',#2141);
#2143=EDGE_CURVE('E1751',#2142,#2132,#2140,.T.);
#2144=ORIENTED_EDGE('',*,*,#2143,.F.);
#2145=CARTESIAN_POINT('',(0.,0.,-9.75000000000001));
#2146=DIRECTION('',(0.,0.,1.));
#2147=DIRECTION('',(1.,0.,0.));
#2148=AXIS2_PLACEMENT_3D('',#2145,#2146,#2147);
#2149=CIRCLE('',#2148,32.02);
#2150=CARTESIAN_POINT('',(-12.6102113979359,-29.4323456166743,-9.75000000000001));
#2151=VERTEX_POINT('',#2150);
#2152=EDGE_CURVE('E1748',#2151,#2142,#2149,.T.);
#2153=ORIENTED_EDGE('',*,*,#2152,.F.);
#2154=DIRECTION('',(0.,0.,1.));
#2155=VECTOR('',#2154,1.);
#2156=CARTESIAN_POINT('',(-12.6102113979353,-29.4323456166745,-5.52500000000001));
#2157=LINE('',#2156,#2155);
#2158=EDGE_CURVE('E1754',#2134,#2151,#2157,.F.);
#2159=ORIENTED_EDGE('',*,*,#2158,.F.);
#2160=EDGE_LOOP('',(#2136,#2144,#2153,#2159));
#2161=FACE_BOUND('',#2160,.T.);
#2162=CARTESIAN_POINT('',(0.,0.,-1.30000000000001));
#2163=DIRECTION('',(0.,0.,-1.));
#2164=DIRECTION('',(-1.,0.,0.));
#2165=AXIS2_PLACEMENT_3D('',#2162,#2163,#2164);
#2166=CIRCLE('',#2165,32.02);
#2167=CARTESIAN_POINT('',(-22.3662227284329,-22.9135872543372,-1.30000000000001));
#2168=VERTEX_POINT('',#2167);
#2169=CARTESIAN_POINT('',(-22.9135872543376,-22.3662227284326,-1.30000000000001));
#2170=VERTEX_POINT('',#2169);
#2171=EDGE_CURVE('E1785',#2168,#2170,#2166,.T.);
#2172=ORIENTED_EDGE('',*,*,#2171,.F.);
#2173=DIRECTION('',(0.,0.,1.));
#2174=VECTOR('',#2173,1.);
#2175=CARTESIAN_POINT('',(-22.3662227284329,-22.9135872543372,-5.52500000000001));
#2176=LINE('',#2175,#2174);
#2177=CARTESIAN_POINT('',(-22.3662227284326,-22.9135872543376,-9.75000000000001));
#2178=VERTEX_POINT('',#2177);
#2179=EDGE_CURVE('E1778',#2178,#2168,#2176,.T.);
#2180=ORIENTED_EDGE('',*,*,#2179,.F.);
#2181=CARTESIAN_POINT('',(0.,0.,-9.75000000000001));
#2182=DIRECTION('',(0.,0.,1.));
#2183=DIRECTION('',(1.,0.,0.));
#2184=AXIS2_PLACEMENT_3D('',#2181,#2182,#2183);
#2185=CIRCLE('',#2184,32.02);
#2186=CARTESIAN_POINT('',(-22.913587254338,-22.3662227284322,-9.75000000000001));
#2187=VERTEX_POINT('',#2186);
#2188=EDGE_CURVE('E1773',#2187,#2178,#2185,.T.);
#2189=ORIENTED_EDGE('',*,*,#2188,.F.);
#2190=DIRECTION('',(0.,0.,1.));
#2191=VECTOR('',#2190,1.);
#2192=CARTESIAN_POINT('',(-22.9135872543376,-22.3662227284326,-5.52500000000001));
#2193=LINE('',#2192,#2191);
#2194=EDGE_CURVE('E1776',#2170,#2187,#2193,.F.);
#2195=ORIENTED_EDGE('',*,*,#2194,.F.);
#2196=EDGE_LOOP('',(#2172,#2180,#2189,#2195));
#2197=FACE_BOUND('',#2196,.T.);
#2198=CARTESIAN_POINT('',(0.,0.,-1.30000000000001));
#2199=DIRECTION('',(0.,0.,-1.));
#2200=DIRECTION('',(-1.,0.,0.));
#2201=AXIS2_PLACEMENT_3D('',#2198,#2199,#2200);
#2202=CIRCLE('',#2201,32.02);
#2203=CARTESIAN_POINT('',(-29.4323456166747,-12.6102113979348,-1.30000000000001));
#2204=VERTEX_POINT('',#2203);
#2205=CARTESIAN_POINT('',(-29.7285771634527,-11.8950451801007,-1.30000000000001));
#2206=VERTEX_POINT('',#2205);
#2207=EDGE_CURVE('E1807',#2204,#2206,#2202,.T.);
#2208=ORIENTED_EDGE('',*,*,#2207,.F.);
#2209=DIRECTION('',(0.,0.,1.));
#2210=VECTOR('',#2209,1.);
#2211=CARTESIAN_POINT('',(-29.4323456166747,-12.6102113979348,-5.52500000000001));
#2212=LINE('',#2211,#2210);
#2213=CARTESIAN_POINT('',(-29.4323456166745,-12.6102113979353,-9.75000000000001));
#2214=VERTEX_POINT('',#2213);
#2215=EDGE_CURVE('E1802',#2214,#2204,#2212,.T.);
#2216=ORIENTED_EDGE('',*,*,#2215,.F.);
#2217=CARTESIAN_POINT('',(0.,0.,-9.75000000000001));
#2218=DIRECTION('',(0.,0.,1.));
#2219=DIRECTION('',(1.,0.,0.));
#2220=AXIS2_PLACEMENT_3D('',#2217,#2218,#2219);
#2221=CIRCLE('',#2220,32.02);
#2222=CARTESIAN_POINT('',(-29.7285771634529,-11.8950451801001,-9.75000000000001));
#2223=VERTEX_POINT('',#2222);
#2224=EDGE_CURVE('E1796',#2223,#2214,#2221,.T.);
#2225=ORIENTED_EDGE('',*,*,#2224,.F.);
#2226=DIRECTION('',(0.,0.,1.));
#2227=VECTOR('',#2226,1.);
#2228=CARTESIAN_POINT('',(-29.7285771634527,-11.8950451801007,-5.52500000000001));
#2229=LINE('',#2228,#2227);
#2230=EDGE_CURVE('E1797',#2206,#2223,#2229,.F.);
#2231=ORIENTED_EDGE('',*,*,#2230,.F.);
#2232=EDGE_LOOP('',(#2208,#2216,#2225,#2231));
#2233=FACE_BOUND('',#2232,.T.);
#2234=CARTESIAN_POINT('',(0.,0.,-1.30000000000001));
#2235=DIRECTION('',(0.,0.,-1.));
#2236=DIRECTION('',(-1.,0.,0.));
#2237=AXIS2_PLACEMENT_3D('',#2234,#2235,#2236);
#2238=CIRCLE('',#2237,32.02);
#2239=CARTESIAN_POINT('',(-32.0176606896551,-0.387045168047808,-1.30000000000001));
#2240=VERTEX_POINT('',#2239);
#2241=CARTESIAN_POINT('',(-32.0176606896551,0.387045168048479,-1.30000000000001));
#2242=VERTEX_POINT('',#2241);
#2243=EDGE_CURVE('E1826',#2240,#2242,#2238,.T.);
#2244=ORIENTED_EDGE('',*,*,#2243,.F.);
#2245=DIRECTION('',(0.,0.,1.));
#2246=VECTOR('',#2245,1.);
#2247=CARTESIAN_POINT('',(-32.0176606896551,-0.387045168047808,-5.52500000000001));
#2248=LINE('',#2247,#2246);
#2249=CARTESIAN_POINT('',(-32.0176606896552,-0.387045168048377,-9.75000000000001));
#2250=VERTEX_POINT('',#2249);
#2251=EDGE_CURVE('E1829',#2250,#2240,#2248,.T.);
#2252=ORIENTED_EDGE('',*,*,#2251,.F.);
#2253=CARTESIAN_POINT('',(0.,0.,-9.75000000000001));
#2254=DIRECTION('',(0.,0.,1.));
#2255=DIRECTION('',(1.,0.,0.));
#2256=AXIS2_PLACEMENT_3D('',#2253,#2254,#2255);
#2257=CIRCLE('',#2256,32.02);
#2258=CARTESIAN_POINT('',(-32.0176606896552,0.387045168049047,-9.75000000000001));
#2259=VERTEX_POINT('',#2258);
#2260=EDGE_CURVE('E1824',#2259,#2250,#2257,.T.);
#2261=ORIENTED_EDGE('',*,*,#2260,.F.);
#2262=DIRECTION('',(0.,0.,1.));
#2263=VECTOR('',#2262,1.);
#2264=CARTESIAN_POINT('',(-32.0176606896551,0.387045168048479,-5.52500000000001));
#2265=LINE('',#2264,#2263);
#2266=EDGE_CURVE('E1823',#2242,#2259,#2265,.F.);
#2267=ORIENTED_EDGE('',*,*,#2266,.F.);
#2268=EDGE_LOOP('',(#2244,#2252,#2261,#2267));
#2269=FACE_BOUND('',#2268,.T.);
#2270=CARTESIAN_POINT('',(0.,0.,-1.30000000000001));
#2271=DIRECTION('',(0.,0.,-1.));
#2272=DIRECTION('',(-1.,0.,0.));
#2273=AXIS2_PLACEMENT_3D('',#2270,#2271,#2272);
#2274=CIRCLE('',#2273,32.02);
#2275=CARTESIAN_POINT('',(-29.7285771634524,11.8950451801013,-1.30000000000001));
#2276=VERTEX_POINT('',#2275);
#2277=CARTESIAN_POINT('',(-29.4323456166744,12.6102113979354,-1.30000000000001));
#2278=VERTEX_POINT('',#2277);
#2279=EDGE_CURVE('E1853',#2276,#2278,#2274,.T.);
#2280=ORIENTED_EDGE('',*,*,#2279,.F.);
#2281=DIRECTION('',(0.,0.,1.));
#2282=VECTOR('',#2281,1.);
#2283=CARTESIAN_POINT('',(-29.7285771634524,11.8950451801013,-5.52500000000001));
#2284=LINE('',#2283,#2282);
#2285=CARTESIAN_POINT('',(-29.7285771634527,11.8950451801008,-9.75000000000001));
#2286=VERTEX_POINT('',#2285);
#2287=EDGE_CURVE('E1851',#2286,#2276,#2284,.T.);
#2288=ORIENTED_EDGE('',*,*,#2287,.F.);
#2289=CARTESIAN_POINT('',(0.,0.,-9.75000000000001));
#2290=DIRECTION('',(0.,0.,1.));
#2291=DIRECTION('',(1.,0.,0.));
#2292=AXIS2_PLACEMENT_3D('',#2289,#2290,#2291);
#2293=CIRCLE('',#2292,32.02);
#2294=CARTESIAN_POINT('',(-29.4323456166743,12.610211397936,-9.75000000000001));
#2295=VERTEX_POINT('',#2294);
#2296=EDGE_CURVE('E1844',#2295,#2286,#2293,.T.);
#2297=ORIENTED_EDGE('',*,*,#2296,.F.);
#2298=DIRECTION('',(0.,0.,1.));
#2299=VECTOR('',#2298,1.);
#2300=CARTESIAN_POINT('',(-29.4323456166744,12.6102113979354,-5.52500000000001));
#2301=LINE('',#2300,#2299);
#2302=EDGE_CURVE('E1848',#2278,#2295,#2301,.F.);
#2303=ORIENTED_EDGE('',*,*,#2302,.F.);
#2304=EDGE_LOOP('',(#2280,#2288,#2297,#2303));
#2305=FACE_BOUND('',#2304,.T.);
#2306=CARTESIAN_POINT('',(0.,0.,-1.30000000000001));
#2307=DIRECTION('',(0.,0.,-1.));
#2308=DIRECTION('',(-1.,0.,0.));
#2309=AXIS2_PLACEMENT_3D('',#2306,#2307,#2308);
#2310=CIRCLE('',#2309,32.02);
#2311=CARTESIAN_POINT('',(-22.9135872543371,22.366222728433,-1.30000000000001));
#2312=VERTEX_POINT('',#2311);
#2313=CARTESIAN_POINT('',(-22.3662227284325,22.9135872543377,-1.30000000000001));
#2314=VERTEX_POINT('',#2313);
#2315=EDGE_CURVE('E1877',#2312,#2314,#2310,.T.);
#2316=ORIENTED_EDGE('',*,*,#2315,.F.);
#2317=DIRECTION('',(0.,0.,1.));
#2318=VECTOR('',#2317,1.);
#2319=CARTESIAN_POINT('',(-22.9135872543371,22.366222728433,-5.52500000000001));
#2320=LINE('',#2319,#2318);
#2321=CARTESIAN_POINT('',(-22.9135872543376,22.3662227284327,-9.75000000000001));
#2322=VERTEX_POINT('',#2321);
#2323=EDGE_CURVE('E1872',#2322,#2312,#2320,.T.);
#2324=ORIENTED_EDGE('',*,*,#2323,.F.);
#2325=CARTESIAN_POINT('',(0.,0.,-9.75000000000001));
#2326=DIRECTION('',(0.,0.,1.));
#2327=DIRECTION('',(1.,0.,0.));
#2328=AXIS2_PLACEMENT_3D('',#2325,#2326,#2327);
#2329=CIRCLE('',#2328,32.02);
#2330=CARTESIAN_POINT('',(-22.3662227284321,22.9135872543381,-9.75000000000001));
#2331=VERTEX_POINT('',#2330);
#2332=EDGE_CURVE('E1868',#2331,#2322,#2329,.T.);
#2333=ORIENTED_EDGE('',*,*,#2332,.F.);
#2334=DIRECTION('',(0.,0.,1.));
#2335=VECTOR('',#2334,1.);
#2336=CARTESIAN_POINT('',(-22.3662227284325,22.9135872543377,-5.52500000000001));
#2337=LINE('',#2336,#2335);
#2338=EDGE_CURVE('E1871',#2314,#2331,#2337,.F.);
#2339=ORIENTED_EDGE('',*,*,#2338,.F.);
#2340=EDGE_LOOP('',(#2316,#2324,#2333,#2339));
#2341=FACE_BOUND('',#2340,.T.);
#2342=CARTESIAN_POINT('',(0.,0.,-1.30000000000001));
#2343=DIRECTION('',(0.,0.,-1.));
#2344=DIRECTION('',(-1.,0.,0.));
#2345=AXIS2_PLACEMENT_3D('',#2342,#2343,#2344);
#2346=CIRCLE('',#2345,32.02);
#2347=CARTESIAN_POINT('',(-12.6102113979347,29.4323456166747,-1.30000000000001));
#2348=VERTEX_POINT('',#2347);
#2349=CARTESIAN_POINT('',(-11.8950451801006,29.7285771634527,-1.30000000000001));
#2350=VERTEX_POINT('',#2349);
#2351=EDGE_CURVE('E11',#2348,#2350,#2346,.T.);
#2352=ORIENTED_EDGE('',*,*,#2351,.F.);
#2353=DIRECTION('',(0.,0.,1.));
#2354=VECTOR('',#2353,1.);
#2355=CARTESIAN_POINT('',(-12.6102113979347,29.4323456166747,-5.52500000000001));
#2356=LINE('',#2355,#2354);
#2357=CARTESIAN_POINT('',(-12.6102113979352,29.4323456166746,-9.75000000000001));
#2358=VERTEX_POINT('',#2357);
#2359=EDGE_CURVE('E47',#2358,#2348,#2356,.T.);
#2360=ORIENTED_EDGE('',*,*,#2359,.F.);
#2361=CARTESIAN_POINT('',(0.,0.,-9.75000000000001));
#2362=DIRECTION('',(0.,0.,1.));
#2363=DIRECTION('',(1.,0.,0.));
#2364=AXIS2_PLACEMENT_3D('',#2361,#2362,#2363);
#2365=CIRCLE('',#2364,32.02);
#2366=CARTESIAN_POINT('',(-11.8950451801,29.728577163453,-9.75000000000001));
#2367=VERTEX_POINT('',#2366);
#2368=EDGE_CURVE('E1895',#2367,#2358,#2365,.T.);
#2369=ORIENTED_EDGE('',*,*,#2368,.F.);
#2370=DIRECTION('',(0.,0.,1.));
#2371=VECTOR('',#2370,1.);
#2372=CARTESIAN_POINT('',(-11.8950451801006,29.7285771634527,-5.52500000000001));
#2373=LINE('',#2372,#2371);
#2374=EDGE_CURVE('E844',#2350,#2367,#2373,.F.);
#2375=ORIENTED_EDGE('',*,*,#2374,.F.);
#2376=EDGE_LOOP('',(#2352,#2360,#2369,#2375));
#2377=FACE_BOUND('',#2376,.T.);
#2378=ADVANCED_FACE('F1902',(#1239,#1275,#1311,#1347,#1383,#1419,#1455,#1491,#1527,#1563,#1599,
#1635,#1671,#1707,#1743,#1754,#1765,#1801,#1837,#1873,#1909,#1945,#1981,#2017,#2053,#2089,#2125,
#2161,#2197,#2233,#2269,#2305,#2341,#2377),#1203,.T.);
#2379=CARTESIAN_POINT('',(0.,40.5,9.74999999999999));
#2380=DIRECTION('',(0.,0.,-1.));
#2381=DIRECTION('',(-1.,0.,0.));
#2382=AXIS2_PLACEMENT_3D('',#2379,#2380,#2381);
#2383=PLANE('',#2382);
#2384=ORIENTED_EDGE('',*,*,#1828,.F.);
#2385=CARTESIAN_POINT('',(0.,36.25,9.74999999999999));
#2386=DIRECTION('',(0.,0.,1.));
#2387=DIRECTION('',(1.,0.,0.));
#2388=AXIS2_PLACEMENT_3D('',#2385,#2386,#2387);
#2389=CIRCLE('',#2388,4.25000000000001);
#2390=EDGE_CURVE('E1495',#1818,#572,#2389,.T.);
#2391=ORIENTED_EDGE('',*,*,#2390,.T.);
#2392=ORIENTED_EDGE('',*,*,#573,.F.);
#2393=EDGE_CURVE('E1493',#570,#1827,#2389,.T.);
#2394=ORIENTED_EDGE('',*,*,#2393,.T.);
#2395=EDGE_LOOP('',(#2384,#2391,#2392,#2394));
#2396=FACE_BOUND('',#2395,.T.);
#2397=ADVANCED_FACE('F1901',(#2396),#2383,.F.);
#2398=CARTESIAN_POINT('',(0.,40.5,1.29999999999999));
#2399=DIRECTION('',(0.,0.,1.));
#2400=DIRECTION('',(1.,0.,0.));
#2401=AXIS2_PLACEMENT_3D('',#2398,#2399,#2400);
#2402=PLANE('',#2401);
#2403=ORIENTED_EDGE('',*,*,#1811,.F.);
#2404=CARTESIAN_POINT('',(0.,36.25,1.29999999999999));
#2405=DIRECTION('',(0.,0.,1.));
#2406=DIRECTION('',(1.,0.,0.));
#2407=AXIS2_PLACEMENT_3D('',#2404,#2405,#2406);
#2408=CIRCLE('',#2407,4.25);
#2409=EDGE_CURVE('E1500',#589,#1808,#2408,.T.);
#2410=ORIENTED_EDGE('',*,*,#2409,.F.);
#2411=ORIENTED_EDGE('',*,*,#590,.F.);
#2412=EDGE_CURVE('E1496',#1810,#580,#2408,.T.);
#2413=ORIENTED_EDGE('',*,*,#2412,.F.);
#2414=EDGE_LOOP('',(#2403,#2410,#2411,#2413));
#2415=FACE_BOUND('',#2414,.T.);
#2416=ADVANCED_FACE('F1911',(#2415),#2402,.F.);
#2417=CARTESIAN_POINT('',(0.,36.25,9.74999999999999));
#2418=DIRECTION('',(0.,0.,1.));
#2419=DIRECTION('',(1.,0.,0.));
#2420=AXIS2_PLACEMENT_3D('',#2417,#2418,#2419);
#2421=CYLINDRICAL_SURFACE('',#2420,4.25000000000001);
#2422=ORIENTED_EDGE('',*,*,#1819,.F.);
#2423=ORIENTED_EDGE('',*,*,#2412,.T.);
#2424=ORIENTED_EDGE('',*,*,#581,.F.);
#2425=ORIENTED_EDGE('',*,*,#2390,.F.);
#2426=EDGE_LOOP('',(#2422,#2423,#2424,#2425));
#2427=FACE_BOUND('',#2426,.T.);
#2428=ADVANCED_FACE('F1968',(#2427),#2421,.T.);
#2429=ORIENTED_EDGE('',*,*,#1834,.F.);
#2430=ORIENTED_EDGE('',*,*,#2393,.F.);
#2431=ORIENTED_EDGE('',*,*,#596,.F.);
#2432=ORIENTED_EDGE('',*,*,#2409,.T.);
#2433=EDGE_LOOP('',(#2429,#2430,#2431,#2432));
#2434=FACE_BOUND('',#2433,.T.);
#2435=ADVANCED_FACE('F1948',(#2434),#2421,.T.);
#2436=CARTESIAN_POINT('',(0.,40.5,-1.30000000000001));
#2437=DIRECTION('',(0.,0.,-1.));
#2438=DIRECTION('',(-1.,0.,0.));
#2439=AXIS2_PLACEMENT_3D('',#2436,#2437,#2438);
#2440=PLANE('',#2439);
#2441=ORIENTED_EDGE('',*,*,#1783,.F.);
#2442=CARTESIAN_POINT('',(0.,36.25,-1.30000000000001));
#2443=DIRECTION('',(0.,0.,1.));
#2444=DIRECTION('',(1.,0.,0.));
#2445=AXIS2_PLACEMENT_3D('',#2442,#2443,#2444);
#2446=CIRCLE('',#2445,4.25);
#2447=EDGE_CURVE('E1471',#1773,#628,#2446,.T.);
#2448=ORIENTED_EDGE('',*,*,#2447,.T.);
#2449=ORIENTED_EDGE('',*,*,#631,.T.);
#2450=EDGE_CURVE('E1475',#630,#1782,#2446,.T.);
#2451=ORIENTED_EDGE('',*,*,#2450,.T.);
#2452=EDGE_LOOP('',(#2441,#2448,#2449,#2451));
#2453=FACE_BOUND('',#2452,.T.);
#2454=ADVANCED_FACE('F1942',(#2453),#2440,.F.);
#2455=CARTESIAN_POINT('',(0.,36.25,9.74999999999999));
#2456=DIRECTION('',(0.,0.,1.));
#2457=DIRECTION('',(1.,0.,0.));
#2458=AXIS2_PLACEMENT_3D('',#2455,#2456,#2457);
#2459=CYLINDRICAL_SURFACE('',#2458,4.25000000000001);
#2460=ORIENTED_EDGE('',*,*,#1774,.F.);
#2461=CARTESIAN_POINT('',(0.,36.25,-9.75000000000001));
#2462=DIRECTION('',(0.,0.,1.));
#2463=DIRECTION('',(1.,0.,0.));
#2464=AXIS2_PLACEMENT_3D('',#2461,#2462,#2463);
#2465=CIRCLE('',#2464,4.25000000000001);
#2466=EDGE_CURVE('E1470',#1771,#638,#2465,.T.);
#2467=ORIENTED_EDGE('',*,*,#2466,.T.);
#2468=ORIENTED_EDGE('',*,*,#639,.T.);
#2469=ORIENTED_EDGE('',*,*,#2447,.F.);
#2470=EDGE_LOOP('',(#2460,#2467,#2468,#2469));
#2471=FACE_BOUND('',#2470,.T.);
#2472=ADVANCED_FACE('F1941',(#2471),#2459,.T.);
#2473=ORIENTED_EDGE('',*,*,#1791,.F.);
#2474=ORIENTED_EDGE('',*,*,#2450,.F.);
#2475=ORIENTED_EDGE('',*,*,#654,.T.);
#2476=EDGE_CURVE('E1468',#647,#1790,#2465,.T.);
#2477=ORIENTED_EDGE('',*,*,#2476,.T.);
#2478=EDGE_LOOP('',(#2473,#2474,#2475,#2477));
#2479=FACE_BOUND('',#2478,.T.);
#2480=ADVANCED_FACE('F1938',(#2479),#2459,.T.);
#2481=CARTESIAN_POINT('',(0.,40.5,-9.75000000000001));
#2482=DIRECTION('',(0.,0.,1.));
#2483=DIRECTION('',(1.,0.,0.));
#2484=AXIS2_PLACEMENT_3D('',#2481,#2482,#2483);
#2485=PLANE('',#2484);
#2486=ORIENTED_EDGE('',*,*,#1798,.F.);
#2487=ORIENTED_EDGE('',*,*,#2476,.F.);
#2488=ORIENTED_EDGE('',*,*,#648,.T.);
#2489=ORIENTED_EDGE('',*,*,#2466,.F.);
#2490=EDGE_LOOP('',(#2486,#2487,#2488,#2489));
#2491=FACE_BOUND('',#2490,.T.);
#2492=ADVANCED_FACE('F1937',(#2491),#2485,.F.);
#2493=CARTESIAN_POINT('',(0.,45.,13.));
#2494=DIRECTION('',(0.,0.,-1.));
#2495=DIRECTION('',(-1.,0.,0.));
#2496=AXIS2_PLACEMENT_3D('',#2493,#2494,#2495);
#2497=PLANE('',#2496);
#2498=CARTESIAN_POINT('',(0.,0.,13.));
#2499=DIRECTION('',(0.,0.,-1.));
#2500=DIRECTION('',(-1.,0.,0.));
#2501=AXIS2_PLACEMENT_3D('',#2498,#2499,#2500);
#2502=CIRCLE('',#2501,43.9);
#2503=CARTESIAN_POINT('',(-43.9,0.,13.));
#2504=VERTEX_POINT('',#2503);
#2505=EDGE_CURVE('E1545',#2504,#2504,#2502,.F.);
#2506=ORIENTED_EDGE('',*,*,#2505,.T.);
#2507=EDGE_LOOP('',(#2506));
#2508=FACE_BOUND('',#2507,.T.);
#2509=CARTESIAN_POINT('',(0.,0.,13.));
#2510=DIRECTION('',(0.,0.,1.));
#2511=DIRECTION('',(1.,0.,0.));
#2512=AXIS2_PLACEMENT_3D('',#2509,#2510,#2511);
#2513=CIRCLE('',#2512,40.7621509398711);
#2514=CARTESIAN_POINT('',(40.7621509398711,0.,13.));
#2515=VERTEX_POINT('',#2514);
#2516=EDGE_CURVE('E1481',#2515,#2515,#2513,.T.);
#2517=ORIENTED_EDGE('',*,*,#2516,.F.);
#2518=EDGE_LOOP('',(#2517));
#2519=FACE_BOUND('',#2518,.T.);
#2520=ADVANCED_FACE('F1936',(#2508,#2519),#2497,.F.);
#2521=CARTESIAN_POINT('',(0.,0.,13.));
#2522=DIRECTION('',(0.,0.,1.));
#2523=DIRECTION('',(1.,0.,0.));
#2524=AXIS2_PLACEMENT_3D('',#2521,#2522,#2523);
#2525=CONICAL_SURFACE('',#2524,40.7621509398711,0.0872664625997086);
#2526=ORIENTED_EDGE('',*,*,#607,.F.);
#2527=EDGE_LOOP('',(#2526));
#2528=FACE_BOUND('',#2527,.T.);
#2529=ORIENTED_EDGE('',*,*,#2516,.T.);
#2530=EDGE_LOOP('',(#2529));
#2531=FACE_BOUND('',#2530,.T.);
#2532=ADVANCED_FACE('F1958',(#2528,#2531),#2525,.F.);
#2533=CARTESIAN_POINT('',(0.,0.,-9.775));
#2534=DIRECTION('',(0.,0.,-1.));
#2535=DIRECTION('',(-1.,0.,0.));
#2536=AXIS2_PLACEMENT_3D('',#2533,#2534,#2535);
#2537=CONICAL_SURFACE('',#2536,40.48,0.0872664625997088);
#2538=CARTESIAN_POINT('',(0.,0.,-13.));
#2539=DIRECTION('',(0.,0.,1.));
#2540=DIRECTION('',(1.,0.,0.));
#2541=AXIS2_PLACEMENT_3D('',#2538,#2539,#2540);
#2542=CIRCLE('',#2541,40.7621509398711);
#2543=CARTESIAN_POINT('',(40.7621509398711,0.,-13.));
#2544=VERTEX_POINT('',#2543);
#2545=EDGE_CURVE('E1474',#2544,#2544,#2542,.T.);
#2546=ORIENTED_EDGE('',*,*,#2545,.F.);
#2547=EDGE_LOOP('',(#2546));
#2548=FACE_BOUND('',#2547,.T.);
#2549=ORIENTED_EDGE('',*,*,#618,.T.);
#2550=EDGE_LOOP('',(#2549));
#2551=FACE_BOUND('',#2550,.T.);
#2552=ADVANCED_FACE('F1960',(#2548,#2551),#2537,.F.);
#2553=CARTESIAN_POINT('',(0.,45.,-13.));
#2554=DIRECTION('',(0.,0.,1.));
#2555=DIRECTION('',(1.,0.,0.));
#2556=AXIS2_PLACEMENT_3D('',#2553,#2554,#2555);
#2557=PLANE('',#2556);
#2558=CARTESIAN_POINT('',(0.,0.,-13.));
#2559=DIRECTION('',(0.,0.,1.));
#2560=DIRECTION('',(1.,0.,0.));
#2561=AXIS2_PLACEMENT_3D('',#2558,#2559,#2560);
#2562=CIRCLE('',#2561,43.9);
#2563=CARTESIAN_POINT('',(43.9,0.,-13.));
#2564=VERTEX_POINT('',#2563);
#2565=EDGE_CURVE('E1539',#2564,#2564,#2562,.F.);
#2566=ORIENTED_EDGE('',*,*,#2565,.T.);
#2567=EDGE_LOOP('',(#2566));
#2568=FACE_BOUND('',#2567,.T.);
#2569=ORIENTED_EDGE('',*,*,#2545,.T.);
#2570=EDGE_LOOP('',(#2569));
#2571=FACE_BOUND('',#2570,.T.);
#2572=ADVANCED_FACE('F1952',(#2568,#2571),#2557,.F.);
#2573=CARTESIAN_POINT('',(0.,0.,50.3916163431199));
#2574=DIRECTION('',(0.,0.,1.));
#2575=DIRECTION('',(1.,0.,0.));
#2576=AXIS2_PLACEMENT_3D('',#2573,#2574,#2575);
#2577=CYLINDRICAL_SURFACE('',#2576,45.);
#2578=CARTESIAN_POINT('',(0.,0.,-11.9));
#2579=DIRECTION('',(0.,0.,1.));
#2580=DIRECTION('',(1.,0.,0.));
#2581=AXIS2_PLACEMENT_3D('',#2578,#2579,#2580);
#2582=CIRCLE('',#2581,45.);
#2583=CARTESIAN_POINT('',(45.,0.,-11.9));
#2584=VERTEX_POINT('',#2583);
#2585=EDGE_CURVE('E1538',#2584,#2584,#2582,.T.);
#2586=ORIENTED_EDGE('',*,*,#2585,.T.);
#2587=EDGE_LOOP('',(#2586));
#2588=FACE_BOUND('',#2587,.T.);
#2589=CARTESIAN_POINT('',(0.,0.,11.9));
#2590=DIRECTION('',(0.,0.,-1.));
#2591=DIRECTION('',(-1.,0.,0.));
#2592=AXIS2_PLACEMENT_3D('',#2589,#2590,#2591);
#2593=CIRCLE('',#2592,45.);
#2594=CARTESIAN_POINT('',(-45.,0.,11.9));
#2595=VERTEX_POINT('',#2594);
#2596=EDGE_CURVE('E1531',#2595,#2595,#2593,.T.);
#2597=ORIENTED_EDGE('',*,*,#2596,.T.);
#2598=EDGE_LOOP('',(#2597));
#2599=FACE_BOUND('',#2598,.T.);
#2600=ADVANCED_FACE('F1931',(#2588,#2599),#2577,.T.);
#2601=CARTESIAN_POINT('',(0.,27.5,13.));
#2602=DIRECTION('',(0.,0.,-1.));
#2603=DIRECTION('',(-1.,0.,0.));
#2604=AXIS2_PLACEMENT_3D('',#2601,#2602,#2603);
#2605=PLANE('',#2604);
#2606=CARTESIAN_POINT('',(0.,0.,13.));
#2607=DIRECTION('',(0.,0.,-1.));
#2608=DIRECTION('',(-1.,0.,0.));
#2609=AXIS2_PLACEMENT_3D('',#2606,#2607,#2608);
#2610=CIRCLE('',#2609,28.6);
#2611=CARTESIAN_POINT('',(-28.6,0.,13.));
#2612=VERTEX_POINT('',#2611);
#2613=EDGE_CURVE('E1526',#2612,#2612,#2610,.T.);
#2614=ORIENTED_EDGE('',*,*,#2613,.T.);
#2615=EDGE_LOOP('',(#2614));
#2616=FACE_BOUND('',#2615,.T.);
#2617=CARTESIAN_POINT('',(0.,0.,13.));
#2618=DIRECTION('',(0.,0.,1.));
#2619=DIRECTION('',(1.,0.,0.));
#2620=AXIS2_PLACEMENT_3D('',#2617,#2618,#2619);
#2621=CIRCLE('',#2620,32.75);
#2622=CARTESIAN_POINT('',(32.75,0.,13.));
#2623=VERTEX_POINT('',#2622);
#2624=EDGE_CURVE('E1445',#2623,#2623,#2621,.T.);
#2625=ORIENTED_EDGE('',*,*,#2624,.T.);
#2626=EDGE_LOOP('',(#2625));
#2627=FACE_BOUND('',#2626,.T.);
#2628=ADVANCED_FACE('F1929',(#2616,#2627),#2605,.F.);
#2629=CARTESIAN_POINT('',(0.,0.,70.8625909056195));
#2630=DIRECTION('',(0.,0.,1.));
#2631=DIRECTION('',(1.,0.,0.));
#2632=AXIS2_PLACEMENT_3D('',#2629,#2630,#2631);
#2633=CYLINDRICAL_SURFACE('',#2632,32.75);
#2634=ORIENTED_EDGE('',*,*,#2624,.F.);
#2635=EDGE_LOOP('',(#2634));
#2636=FACE_BOUND('',#2635,.T.);
#2637=CARTESIAN_POINT('',(0.,0.,9.775));
#2638=DIRECTION('',(0.,0.,1.));
#2639=DIRECTION('',(1.,0.,0.));
#2640=AXIS2_PLACEMENT_3D('',#2637,#2638,#2639);
#2641=CIRCLE('',#2640,32.75);
#2642=CARTESIAN_POINT('',(32.75,0.,9.775));
#2643=VERTEX_POINT('',#2642);
#2644=EDGE_CURVE('E1438',#2643,#2643,#2641,.T.);
#2645=ORIENTED_EDGE('',*,*,#2644,.T.);
#2646=EDGE_LOOP('',(#2645));
#2647=FACE_BOUND('',#2646,.T.);
#2648=ADVANCED_FACE('F1926',(#2636,#2647),#2633,.T.);
#2649=CARTESIAN_POINT('',(0.,32.75,9.775));
#2650=DIRECTION('',(0.,0.,1.));
#2651=DIRECTION('',(1.,0.,0.));
#2652=AXIS2_PLACEMENT_3D('',#2649,#2650,#2651);
#2653=PLANE('',#2652);
#2654=ORIENTED_EDGE('',*,*,#2644,.F.);
#2655=EDGE_LOOP('',(#2654));
#2656=FACE_BOUND('',#2655,.T.);
#2657=ORIENTED_EDGE('',*,*,#1751,.T.);
#2658=EDGE_LOOP('',(#2657));
#2659=FACE_BOUND('',#2658,.T.);
#2660=ADVANCED_FACE('F1923',(#2656,#2659),#2653,.F.);
#2661=CARTESIAN_POINT('',(0.,32.02,-9.775));
#2662=DIRECTION('',(0.,0.,-1.));
#2663=DIRECTION('',(-1.,0.,0.));
#2664=AXIS2_PLACEMENT_3D('',#2661,#2662,#2663);
#2665=PLANE('',#2664);
#2666=ORIENTED_EDGE('',*,*,#1762,.F.);
#2667=EDGE_LOOP('',(#2666));
#2668=FACE_BOUND('',#2667,.T.);
#2669=CARTESIAN_POINT('',(0.,0.,-9.77500000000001));
#2670=DIRECTION('',(0.,0.,1.));
#2671=DIRECTION('',(1.,0.,0.));
#2672=AXIS2_PLACEMENT_3D('',#2669,#2670,#2671);
#2673=CIRCLE('',#2672,32.75);
#2674=CARTESIAN_POINT('',(32.75,0.,-9.77500000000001));
#2675=VERTEX_POINT('',#2674);
#2676=EDGE_CURVE('E1432',#2675,#2675,#2673,.T.);
#2677=ORIENTED_EDGE('',*,*,#2676,.T.);
#2678=EDGE_LOOP('',(#2677));
#2679=FACE_BOUND('',#2678,.T.);
#2680=ADVANCED_FACE('F1921',(#2668,#2679),#2665,.F.);
#2681=CARTESIAN_POINT('',(0.,0.,70.8625909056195));
#2682=DIRECTION('',(0.,0.,1.));
#2683=DIRECTION('',(1.,0.,0.));
#2684=AXIS2_PLACEMENT_3D('',#2681,#2682,#2683);
#2685=CYLINDRICAL_SURFACE('',#2684,32.75);
#2686=ORIENTED_EDGE('',*,*,#2676,.F.);
#2687=EDGE_LOOP('',(#2686));
#2688=FACE_BOUND('',#2687,.T.);
#2689=CARTESIAN_POINT('',(0.,0.,-13.));
#2690=DIRECTION('',(0.,0.,1.));
#2691=DIRECTION('',(1.,0.,0.));
#2692=AXIS2_PLACEMENT_3D('',#2689,#2690,#2691);
#2693=CIRCLE('',#2692,32.75);
#2694=CARTESIAN_POINT('',(32.75,0.,-13.));
#2695=VERTEX_POINT('',#2694);
#2696=EDGE_CURVE('E1427',#2695,#2695,#2693,.T.);
#2697=ORIENTED_EDGE('',*,*,#2696,.T.);
#2698=EDGE_LOOP('',(#2697));
#2699=FACE_BOUND('',#2698,.T.);
#2700=ADVANCED_FACE('F2412',(#2688,#2699),#2685,.T.);
#2701=CARTESIAN_POINT('',(0.,27.5,-13.));
#2702=DIRECTION('',(0.,0.,1.));
#2703=DIRECTION('',(1.,0.,0.));
#2704=AXIS2_PLACEMENT_3D('',#2701,#2702,#2703);
#2705=PLANE('',#2704);
#2706=CARTESIAN_POINT('',(0.,0.,-13.));
#2707=DIRECTION('',(0.,0.,1.));
#2708=DIRECTION('',(1.,0.,0.));
#2709=AXIS2_PLACEMENT_3D('',#2706,#2707,#2708);
#2710=CIRCLE('',#2709,28.6);
#2711=CARTESIAN_POINT('',(28.6,0.,-13.));
#2712=VERTEX_POINT('',#2711);
#2713=EDGE_CURVE('E1524',#2712,#2712,#2710,.T.);
#2714=ORIENTED_EDGE('',*,*,#2713,.T.);
#2715=EDGE_LOOP('',(#2714));
#2716=FACE_BOUND('',#2715,.T.);
#2717=ORIENTED_EDGE('',*,*,#2696,.F.);
#2718=EDGE_LOOP('',(#2717));
#2719=FACE_BOUND('',#2718,.T.);
#2720=ADVANCED_FACE('F2406',(#2716,#2719),#2705,.F.);
#2721=CARTESIAN_POINT('',(0.,0.,70.8625909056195));
#2722=DIRECTION('',(0.,0.,1.));
#2723=DIRECTION('',(1.,0.,0.));
#2724=AXIS2_PLACEMENT_3D('',#2721,#2722,#2723);
#2725=CYLINDRICAL_SURFACE('',#2724,27.5);
#2726=CARTESIAN_POINT('',(0.,0.,-11.9));
#2727=DIRECTION('',(0.,0.,1.));
#2728=DIRECTION('',(1.,0.,0.));
#2729=AXIS2_PLACEMENT_3D('',#2726,#2727,#2728);
#2730=CIRCLE('',#2729,27.5);
#2731=CARTESIAN_POINT('',(27.5,0.,-11.9));
#2732=VERTEX_POINT('',#2731);
#2733=EDGE_CURVE('E1529',#2732,#2732,#2730,.F.);
#2734=ORIENTED_EDGE('',*,*,#2733,.T.);
#2735=EDGE_LOOP('',(#2734));
#2736=FACE_BOUND('',#2735,.T.);
#2737=CARTESIAN_POINT('',(0.,0.,11.9));
#2738=DIRECTION('',(0.,0.,-1.));
#2739=DIRECTION('',(-1.,0.,0.));
#2740=AXIS2_PLACEMENT_3D('',#2737,#2738,#2739);
#2741=CIRCLE('',#2740,27.5);
#2742=CARTESIAN_POINT('',(-27.5,0.,11.9));
#2743=VERTEX_POINT('',#2742);
#2744=EDGE_CURVE('E1523',#2743,#2743,#2741,.F.);
#2745=ORIENTED_EDGE('',*,*,#2744,.T.);
#2746=EDGE_LOOP('',(#2745));
#2747=FACE_BOUND('',#2746,.T.);
#2748=ADVANCED_FACE('F1976',(#2736,#2747),#2725,.F.);
#2749=CARTESIAN_POINT('',(0.,0.,-11.9));
#2750=DIRECTION('',(0.,0.,1.));
#2751=DIRECTION('',(1.,0.,0.));
#2752=AXIS2_PLACEMENT_3D('',#2749,#2750,#2751);
#2753=TOROIDAL_SURFACE('',#2752,28.6,1.1);
#2754=ORIENTED_EDGE('',*,*,#2733,.F.);
#2755=EDGE_LOOP('',(#2754));
#2756=FACE_BOUND('',#2755,.T.);
#2757=ORIENTED_EDGE('',*,*,#2713,.F.);
#2758=EDGE_LOOP('',(#2757));
#2759=FACE_BOUND('',#2758,.T.);
#2760=ADVANCED_FACE('F1978',(#2756,#2759),#2753,.T.);
#2761=CARTESIAN_POINT('',(0.,0.,11.9));
#2762=DIRECTION('',(0.,0.,-1.));
#2763=DIRECTION('',(-1.,0.,0.));
#2764=AXIS2_PLACEMENT_3D('',#2761,#2762,#2763);
#2765=TOROIDAL_SURFACE('',#2764,28.6,1.1);
#2766=ORIENTED_EDGE('',*,*,#2613,.F.);
#2767=EDGE_LOOP('',(#2766));
#2768=FACE_BOUND('',#2767,.T.);
#2769=ORIENTED_EDGE('',*,*,#2744,.F.);
#2770=EDGE_LOOP('',(#2769));
#2771=FACE_BOUND('',#2770,.T.);
#2772=ADVANCED_FACE('F1980',(#2768,#2771),#2765,.T.);
#2773=CARTESIAN_POINT('',(0.,0.,-11.9));
#2774=DIRECTION('',(0.,0.,1.));
#2775=DIRECTION('',(1.,0.,0.));
#2776=AXIS2_PLACEMENT_3D('',#2773,#2774,#2775);
#2777=TOROIDAL_SURFACE('',#2776,43.9,1.1);
#2778=ORIENTED_EDGE('',*,*,#2565,.F.);
#2779=EDGE_LOOP('',(#2778));
#2780=FACE_BOUND('',#2779,.T.);
#2781=ORIENTED_EDGE('',*,*,#2585,.F.);
#2782=EDGE_LOOP('',(#2781));
#2783=FACE_BOUND('',#2782,.T.);
#2784=ADVANCED_FACE('F1981',(#2780,#2783),#2777,.T.);
#2785=CARTESIAN_POINT('',(0.,0.,11.9));
#2786=DIRECTION('',(0.,0.,-1.));
#2787=DIRECTION('',(-1.,0.,0.));
#2788=AXIS2_PLACEMENT_3D('',#2785,#2786,#2787);
#2789=TOROIDAL_SURFACE('',#2788,43.9,1.1);
#2790=ORIENTED_EDGE('',*,*,#2596,.F.);
#2791=EDGE_LOOP('',(#2790));
#2792=FACE_BOUND('',#2791,.T.);
#2793=ORIENTED_EDGE('',*,*,#2505,.F.);
#2794=EDGE_LOOP('',(#2793));
#2795=FACE_BOUND('',#2794,.T.);
#2796=ADVANCED_FACE('F43',(#2792,#2795),#2789,.T.);
#2797=CARTESIAN_POINT('',(15.4986790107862,37.4171210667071,9.74999999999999));
#2798=DIRECTION('',(0.,0.,-1.));
#2799=DIRECTION('',(-0.923879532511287,0.382683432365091,0.));
#2800=AXIS2_PLACEMENT_3D('',#2797,#2798,#2799);
#2801=PLANE('',#2800);
#2802=CARTESIAN_POINT('',(13.8722744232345,33.4906330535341,9.74999999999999));
#2803=DIRECTION('',(0.,0.,1.));
#2804=DIRECTION('',(0.923879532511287,-0.382683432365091,0.));
#2805=AXIS2_PLACEMENT_3D('',#2802,#2803,#2804);
#2806=CIRCLE('',#2805,4.25000000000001);
#2807=EDGE_CURVE('E1409',#1732,#544,#2806,.T.);
#2808=ORIENTED_EDGE('',*,*,#2807,.T.);
#2809=ORIENTED_EDGE('',*,*,#545,.T.);
#2810=EDGE_CURVE('E1412',#533,#1715,#2806,.T.);
#2811=ORIENTED_EDGE('',*,*,#2810,.T.);
#2812=ORIENTED_EDGE('',*,*,#1740,.T.);
#2813=EDGE_LOOP('',(#2808,#2809,#2811,#2812));
#2814=FACE_BOUND('',#2813,.T.);
#2815=ADVANCED_FACE('F1987',(#2814),#2801,.F.);
#2816=CARTESIAN_POINT('',(15.4986790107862,37.4171210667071,1.29999999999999));
#2817=DIRECTION('',(0.,0.,1.));
#2818=DIRECTION('',(0.923879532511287,-0.382683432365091,0.));
#2819=AXIS2_PLACEMENT_3D('',#2816,#2817,#2818);
#2820=PLANE('',#2819);
#2821=CARTESIAN_POINT('',(13.8722744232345,33.4906330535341,1.29999999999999));
#2822=DIRECTION('',(0.,0.,1.));
#2823=DIRECTION('',(0.923879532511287,-0.382683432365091,0.));
#2824=AXIS2_PLACEMENT_3D('',#2821,#2822,#2823);
#2825=CIRCLE('',#2824,4.25);
#2826=EDGE_CURVE('E1413',#535,#1713,#2825,.T.);
#2827=ORIENTED_EDGE('',*,*,#2826,.F.);
#2828=ORIENTED_EDGE('',*,*,#560,.T.);
#2829=EDGE_CURVE('E1415',#1724,#552,#2825,.T.);
#2830=ORIENTED_EDGE('',*,*,#2829,.F.);
#2831=ORIENTED_EDGE('',*,*,#1725,.T.);
#2832=EDGE_LOOP('',(#2827,#2828,#2830,#2831));
#2833=FACE_BOUND('',#2832,.T.);
#2834=ADVANCED_FACE('F2400',(#2833),#2820,.F.);
#2835=CARTESIAN_POINT('',(13.8722744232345,33.4906330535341,9.74999999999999));
#2836=DIRECTION('',(0.,0.,1.));
#2837=DIRECTION('',(0.923879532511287,-0.382683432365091,0.));
#2838=AXIS2_PLACEMENT_3D('',#2835,#2836,#2837);
#2839=CYLINDRICAL_SURFACE('',#2838,4.25000000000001);
#2840=ORIENTED_EDGE('',*,*,#2810,.F.);
#2841=ORIENTED_EDGE('',*,*,#536,.T.);
#2842=ORIENTED_EDGE('',*,*,#2826,.T.);
#2843=ORIENTED_EDGE('',*,*,#1716,.T.);
#2844=EDGE_LOOP('',(#2840,#2841,#2842,#2843));
#2845=FACE_BOUND('',#2844,.T.);
#2846=ADVANCED_FACE('F2392',(#2845),#2839,.T.);
#2847=ORIENTED_EDGE('',*,*,#2829,.T.);
#2848=ORIENTED_EDGE('',*,*,#553,.T.);
#2849=ORIENTED_EDGE('',*,*,#2807,.F.);
#2850=ORIENTED_EDGE('',*,*,#1733,.T.);
#2851=EDGE_LOOP('',(#2847,#2848,#2849,#2850));
#2852=FACE_BOUND('',#2851,.T.);
#2853=ADVANCED_FACE('F2395',(#2852),#2839,.T.);
#2854=CARTESIAN_POINT('',(15.4986790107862,37.4171210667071,-1.30000000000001));
#2855=DIRECTION('',(0.,0.,-1.));
#2856=DIRECTION('',(-0.923879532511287,0.382683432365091,0.));
#2857=AXIS2_PLACEMENT_3D('',#2854,#2855,#2856);
#2858=PLANE('',#2857);
#2859=CARTESIAN_POINT('',(13.8722744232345,33.4906330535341,-1.30000000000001));
#2860=DIRECTION('',(0.,0.,1.));
#2861=DIRECTION('',(0.923879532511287,-0.382683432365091,0.));
#2862=AXIS2_PLACEMENT_3D('',#2859,#2860,#2861);
#2863=CIRCLE('',#2862,4.25);
#2864=EDGE_CURVE('E1395',#1846,#664,#2863,.T.);
#2865=ORIENTED_EDGE('',*,*,#2864,.T.);
#2866=ORIENTED_EDGE('',*,*,#667,.T.);
#2867=EDGE_CURVE('E1394',#666,#1844,#2863,.T.);
#2868=ORIENTED_EDGE('',*,*,#2867,.T.);
#2869=ORIENTED_EDGE('',*,*,#1847,.T.);
#2870=EDGE_LOOP('',(#2865,#2866,#2868,#2869));
#2871=FACE_BOUND('',#2870,.T.);
#2872=ADVANCED_FACE('F2386',(#2871),#2858,.F.);
#2873=CARTESIAN_POINT('',(13.8722744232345,33.4906330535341,9.74999999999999));
#2874=DIRECTION('',(0.,0.,1.));
#2875=DIRECTION('',(0.923879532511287,-0.382683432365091,0.));
#2876=AXIS2_PLACEMENT_3D('',#2873,#2874,#2875);
#2877=CYLINDRICAL_SURFACE('',#2876,4.25000000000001);
#2878=ORIENTED_EDGE('',*,*,#2867,.F.);
#2879=ORIENTED_EDGE('',*,*,#690,.T.);
#2880=CARTESIAN_POINT('',(13.8722744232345,33.4906330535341,-9.75000000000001));
#2881=DIRECTION('',(0.,0.,1.));
#2882=DIRECTION('',(0.923879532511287,-0.382683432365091,0.));
#2883=AXIS2_PLACEMENT_3D('',#2880,#2881,#2882);
#2884=CIRCLE('',#2883,4.25000000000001);
#2885=EDGE_CURVE('E1391',#683,#1854,#2884,.T.);
#2886=ORIENTED_EDGE('',*,*,#2885,.T.);
#2887=ORIENTED_EDGE('',*,*,#1855,.T.);
#2888=EDGE_LOOP('',(#2878,#2879,#2886,#2887));
#2889=FACE_BOUND('',#2888,.T.);
#2890=ADVANCED_FACE('F2387',(#2889),#2877,.T.);
#2891=EDGE_CURVE('E1386',#1863,#674,#2884,.T.);
#2892=ORIENTED_EDGE('',*,*,#2891,.T.);
#2893=ORIENTED_EDGE('',*,*,#675,.T.);
#2894=ORIENTED_EDGE('',*,*,#2864,.F.);
#2895=ORIENTED_EDGE('',*,*,#1870,.T.);
#2896=EDGE_LOOP('',(#2892,#2893,#2894,#2895));
#2897=FACE_BOUND('',#2896,.T.);
#2898=ADVANCED_FACE('F2381',(#2897),#2877,.T.);
#2899=CARTESIAN_POINT('',(15.4986790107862,37.4171210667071,-9.75000000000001));
#2900=DIRECTION('',(0.,0.,1.));
#2901=DIRECTION('',(0.923879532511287,-0.382683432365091,0.));
#2902=AXIS2_PLACEMENT_3D('',#2899,#2900,#2901);
#2903=PLANE('',#2902);
#2904=ORIENTED_EDGE('',*,*,#2885,.F.);
#2905=ORIENTED_EDGE('',*,*,#684,.T.);
#2906=ORIENTED_EDGE('',*,*,#2891,.F.);
#2907=ORIENTED_EDGE('',*,*,#1864,.T.);
#2908=EDGE_LOOP('',(#2904,#2905,#2906,#2907));
#2909=FACE_BOUND('',#2908,.T.);
#2910=ADVANCED_FACE('F2379',(#2909),#2903,.F.);
#2911=CARTESIAN_POINT('',(28.6378246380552,28.6378246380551,9.74999999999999));
#2912=DIRECTION('',(0.,0.,-1.));
#2913=DIRECTION('',(-0.707106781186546,0.707106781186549,0.));
#2914=AXIS2_PLACEMENT_3D('',#2911,#2912,#2913);
#2915=PLANE('',#2914);
#2916=CARTESIAN_POINT('',(25.6326208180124,25.6326208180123,9.74999999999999));
#2917=DIRECTION('',(0.,0.,1.));
#2918=DIRECTION('',(0.707106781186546,-0.707106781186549,0.));
#2919=AXIS2_PLACEMENT_3D('',#2916,#2917,#2918);
#2920=CIRCLE('',#2919,4.25000000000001);
#2921=EDGE_CURVE('E1370',#1696,#508,#2920,.T.);
#2922=ORIENTED_EDGE('',*,*,#2921,.T.);
#2923=ORIENTED_EDGE('',*,*,#509,.T.);
#2924=EDGE_CURVE('E1374',#497,#1679,#2920,.T.);
#2925=ORIENTED_EDGE('',*,*,#2924,.T.);
#2926=ORIENTED_EDGE('',*,*,#1704,.T.);
#2927=EDGE_LOOP('',(#2922,#2923,#2925,#2926));
#2928=FACE_BOUND('',#2927,.T.);
#2929=ADVANCED_FACE('F2376',(#2928),#2915,.F.);
#2930=CARTESIAN_POINT('',(28.6378246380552,28.6378246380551,1.29999999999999));
#2931=DIRECTION('',(0.,0.,1.));
#2932=DIRECTION('',(0.707106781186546,-0.707106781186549,0.));
#2933=AXIS2_PLACEMENT_3D('',#2930,#2931,#2932);
#2934=PLANE('',#2933);
#2935=CARTESIAN_POINT('',(25.6326208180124,25.6326208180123,1.29999999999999));
#2936=DIRECTION('',(0.,0.,1.));
#2937=DIRECTION('',(0.707106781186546,-0.707106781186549,0.));
#2938=AXIS2_PLACEMENT_3D('',#2935,#2936,#2937);
#2939=CIRCLE('',#2938,4.25);
#2940=EDGE_CURVE('E1372',#499,#1677,#2939,.T.);
#2941=ORIENTED_EDGE('',*,*,#2940,.F.);
#2942=ORIENTED_EDGE('',*,*,#524,.T.);
#2943=EDGE_CURVE('E1371',#1688,#516,#2939,.T.);
#2944=ORIENTED_EDGE('',*,*,#2943,.F.);
#2945=ORIENTED_EDGE('',*,*,#1689,.T.);
#2946=EDGE_LOOP('',(#2941,#2942,#2944,#2945));
#2947=FACE_BOUND('',#2946,.T.);
#2948=ADVANCED_FACE('F2375',(#2947),#2934,.F.);
#2949=CARTESIAN_POINT('',(25.6326208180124,25.6326208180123,9.74999999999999));
#2950=DIRECTION('',(0.,0.,1.));
#2951=DIRECTION('',(0.707106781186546,-0.707106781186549,0.));
#2952=AXIS2_PLACEMENT_3D('',#2949,#2950,#2951);
#2953=CYLINDRICAL_SURFACE('',#2952,4.25000000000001);
#2954=ORIENTED_EDGE('',*,*,#2924,.F.);
#2955=ORIENTED_EDGE('',*,*,#500,.T.);
#2956=ORIENTED_EDGE('',*,*,#2940,.T.);
#2957=ORIENTED_EDGE('',*,*,#1680,.T.);
#2958=EDGE_LOOP('',(#2954,#2955,#2956,#2957));
#2959=FACE_BOUND('',#2958,.T.);
#2960=ADVANCED_FACE('F2367',(#2959),#2953,.T.);
#2961=ORIENTED_EDGE('',*,*,#2943,.T.);
#2962=ORIENTED_EDGE('',*,*,#517,.T.);
#2963=ORIENTED_EDGE('',*,*,#2921,.F.);
#2964=ORIENTED_EDGE('',*,*,#1697,.T.);
#2965=EDGE_LOOP('',(#2961,#2962,#2963,#2964));
#2966=FACE_BOUND('',#2965,.T.);
#2967=ADVANCED_FACE('F2370',(#2966),#2953,.T.);
#2968=CARTESIAN_POINT('',(28.6378246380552,28.6378246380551,-1.30000000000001));
#2969=DIRECTION('',(0.,0.,-1.));
#2970=DIRECTION('',(-0.707106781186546,0.707106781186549,0.));
#2971=AXIS2_PLACEMENT_3D('',#2968,#2969,#2970);
#2972=PLANE('',#2971);
#2973=CARTESIAN_POINT('',(25.6326208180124,25.6326208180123,-1.30000000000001));
#2974=DIRECTION('',(0.,0.,1.));
#2975=DIRECTION('',(0.707106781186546,-0.707106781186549,0.));
#2976=AXIS2_PLACEMENT_3D('',#2973,#2974,#2975);
#2977=CIRCLE('',#2976,4.25);
#2978=EDGE_CURVE('E1354',#1882,#700,#2977,.T.);
#2979=ORIENTED_EDGE('',*,*,#2978,.T.);
#2980=ORIENTED_EDGE('',*,*,#703,.T.);
#2981=EDGE_CURVE('E1351',#702,#1880,#2977,.T.);
#2982=ORIENTED_EDGE('',*,*,#2981,.T.);
#2983=ORIENTED_EDGE('',*,*,#1883,.T.);
#2984=EDGE_LOOP('',(#2979,#2980,#2982,#2983));
#2985=FACE_BOUND('',#2984,.T.);
#2986=ADVANCED_FACE('F2361',(#2985),#2972,.F.);
#2987=CARTESIAN_POINT('',(25.6326208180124,25.6326208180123,9.74999999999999));
#2988=DIRECTION('',(0.,0.,1.));
#2989=DIRECTION('',(0.707106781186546,-0.707106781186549,0.));
#2990=AXIS2_PLACEMENT_3D('',#2987,#2988,#2989);
#2991=CYLINDRICAL_SURFACE('',#2990,4.25000000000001);
#2992=ORIENTED_EDGE('',*,*,#2981,.F.);
#2993=ORIENTED_EDGE('',*,*,#726,.T.);
#2994=CARTESIAN_POINT('',(25.6326208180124,25.6326208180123,-9.75000000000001));
#2995=DIRECTION('',(0.,0.,1.));
#2996=DIRECTION('',(0.707106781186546,-0.707106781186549,0.));
#2997=AXIS2_PLACEMENT_3D('',#2994,#2995,#2996);
#2998=CIRCLE('',#2997,4.25000000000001);
#2999=EDGE_CURVE('E1353',#719,#1890,#2998,.T.);
#3000=ORIENTED_EDGE('',*,*,#2999,.T.);
#3001=ORIENTED_EDGE('',*,*,#1891,.T.);
#3002=EDGE_LOOP('',(#2992,#2993,#3000,#3001));
#3003=FACE_BOUND('',#3002,.T.);
#3004=ADVANCED_FACE('F2359',(#3003),#2991,.T.);
#3005=EDGE_CURVE('E1350',#1899,#710,#2998,.T.);
#3006=ORIENTED_EDGE('',*,*,#3005,.T.);
#3007=ORIENTED_EDGE('',*,*,#711,.T.);
#3008=ORIENTED_EDGE('',*,*,#2978,.F.);
#3009=ORIENTED_EDGE('',*,*,#1906,.T.);
#3010=EDGE_LOOP('',(#3006,#3007,#3008,#3009));
#3011=FACE_BOUND('',#3010,.T.);
#3012=ADVANCED_FACE('F2356',(#3011),#2991,.T.);
#3013=CARTESIAN_POINT('',(28.6378246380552,28.6378246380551,-9.75000000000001));
#3014=DIRECTION('',(0.,0.,1.));
#3015=DIRECTION('',(0.707106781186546,-0.707106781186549,0.));
#3016=AXIS2_PLACEMENT_3D('',#3013,#3014,#3015);
#3017=PLANE('',#3016);
#3018=ORIENTED_EDGE('',*,*,#2999,.F.);
#3019=ORIENTED_EDGE('',*,*,#720,.T.);
#3020=ORIENTED_EDGE('',*,*,#3005,.F.);
#3021=ORIENTED_EDGE('',*,*,#1900,.T.);
#3022=EDGE_LOOP('',(#3018,#3019,#3020,#3021));
#3023=FACE_BOUND('',#3022,.T.);
#3024=ADVANCED_FACE('F2355',(#3023),#3017,.F.);
#3025=CARTESIAN_POINT('',(37.4171210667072,15.498679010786,9.74999999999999));
#3026=DIRECTION('',(0.,0.,-1.));
#3027=DIRECTION('',(-0.382683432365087,0.923879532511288,0.));
#3028=AXIS2_PLACEMENT_3D('',#3025,#3026,#3027);
#3029=PLANE('',#3028);
#3030=CARTESIAN_POINT('',(33.4906330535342,13.8722744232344,9.74999999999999));
#3031=DIRECTION('',(0.,0.,1.));
#3032=DIRECTION('',(0.382683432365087,-0.923879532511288,0.));
#3033=AXIS2_PLACEMENT_3D('',#3030,#3031,#3032);
#3034=CIRCLE('',#3033,4.25000000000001);
#3035=EDGE_CURVE('E1327',#1660,#472,#3034,.T.);
#3036=ORIENTED_EDGE('',*,*,#3035,.T.);
#3037=ORIENTED_EDGE('',*,*,#473,.T.);
#3038=EDGE_CURVE('E1332',#461,#1643,#3034,.T.);
#3039=ORIENTED_EDGE('',*,*,#3038,.T.);
#3040=ORIENTED_EDGE('',*,*,#1668,.T.);
#3041=EDGE_LOOP('',(#3036,#3037,#3039,#3040));
#3042=FACE_BOUND('',#3041,.T.);
#3043=ADVANCED_FACE('F2347',(#3042),#3029,.F.);
#3044=CARTESIAN_POINT('',(37.4171210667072,15.498679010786,1.29999999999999));
#3045=DIRECTION('',(0.,0.,1.));
#3046=DIRECTION('',(0.382683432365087,-0.923879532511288,0.));
#3047=AXIS2_PLACEMENT_3D('',#3044,#3045,#3046);
#3048=PLANE('',#3047);
#3049=CARTESIAN_POINT('',(33.4906330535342,13.8722744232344,1.29999999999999));
#3050=DIRECTION('',(0.,0.,1.));
#3051=DIRECTION('',(0.382683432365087,-0.923879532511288,0.));
#3052=AXIS2_PLACEMENT_3D('',#3049,#3050,#3051);
#3053=CIRCLE('',#3052,4.25);
#3054=EDGE_CURVE('E1333',#463,#1641,#3053,.T.);
#3055=ORIENTED_EDGE('',*,*,#3054,.F.);
#3056=ORIENTED_EDGE('',*,*,#488,.T.);
#3057=EDGE_CURVE('E1335',#1652,#480,#3053,.T.);
#3058=ORIENTED_EDGE('',*,*,#3057,.F.);
#3059=ORIENTED_EDGE('',*,*,#1653,.T.);
#3060=EDGE_LOOP('',(#3055,#3056,#3058,#3059));
#3061=FACE_BOUND('',#3060,.T.);
#3062=ADVANCED_FACE('F2349',(#3061),#3048,.F.);
#3063=CARTESIAN_POINT('',(33.4906330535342,13.8722744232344,9.74999999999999));
#3064=DIRECTION('',(0.,0.,1.));
#3065=DIRECTION('',(0.382683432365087,-0.923879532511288,0.));
#3066=AXIS2_PLACEMENT_3D('',#3063,#3064,#3065);
#3067=CYLINDRICAL_SURFACE('',#3066,4.25000000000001);
#3068=ORIENTED_EDGE('',*,*,#3038,.F.);
#3069=ORIENTED_EDGE('',*,*,#464,.T.);
#3070=ORIENTED_EDGE('',*,*,#3054,.T.);
#3071=ORIENTED_EDGE('',*,*,#1644,.T.);
#3072=EDGE_LOOP('',(#3068,#3069,#3070,#3071));
#3073=FACE_BOUND('',#3072,.T.);
#3074=ADVANCED_FACE('F2345',(#3073),#3067,.T.);
#3075=ORIENTED_EDGE('',*,*,#3057,.T.);
#3076=ORIENTED_EDGE('',*,*,#481,.T.);
#3077=ORIENTED_EDGE('',*,*,#3035,.F.);
#3078=ORIENTED_EDGE('',*,*,#1661,.T.);
#3079=EDGE_LOOP('',(#3075,#3076,#3077,#3078));
#3080=FACE_BOUND('',#3079,.T.);
#3081=ADVANCED_FACE('F2344',(#3080),#3067,.T.);
#3082=CARTESIAN_POINT('',(37.4171210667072,15.498679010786,-1.30000000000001));
#3083=DIRECTION('',(0.,0.,-1.));
#3084=DIRECTION('',(-0.382683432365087,0.923879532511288,0.));
#3085=AXIS2_PLACEMENT_3D('',#3082,#3083,#3084);
#3086=PLANE('',#3085);
#3087=CARTESIAN_POINT('',(33.4906330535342,13.8722744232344,-1.30000000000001));
#3088=DIRECTION('',(0.,0.,1.));
#3089=DIRECTION('',(0.382683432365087,-0.923879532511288,0.));
#3090=AXIS2_PLACEMENT_3D('',#3087,#3088,#3089);
#3091=CIRCLE('',#3090,4.25);
#3092=EDGE_CURVE('E1315',#1918,#736,#3091,.T.);
#3093=ORIENTED_EDGE('',*,*,#3092,.T.);
#3094=ORIENTED_EDGE('',*,*,#739,.T.);
#3095=EDGE_CURVE('E1312',#738,#1916,#3091,.T.);
#3096=ORIENTED_EDGE('',*,*,#3095,.T.);
#3097=ORIENTED_EDGE('',*,*,#1919,.T.);
#3098=EDGE_LOOP('',(#3093,#3094,#3096,#3097));
#3099=FACE_BOUND('',#3098,.T.);
#3100=ADVANCED_FACE('F2340',(#3099),#3086,.F.);
#3101=CARTESIAN_POINT('',(33.4906330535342,13.8722744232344,9.74999999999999));
#3102=DIRECTION('',(0.,0.,1.));
#3103=DIRECTION('',(0.382683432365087,-0.923879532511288,0.));
#3104=AXIS2_PLACEMENT_3D('',#3101,#3102,#3103);
#3105=CYLINDRICAL_SURFACE('',#3104,4.25000000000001);
#3106=ORIENTED_EDGE('',*,*,#3095,.F.);
#3107=ORIENTED_EDGE('',*,*,#762,.T.);
#3108=CARTESIAN_POINT('',(33.4906330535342,13.8722744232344,-9.75000000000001));
#3109=DIRECTION('',(0.,0.,1.));
#3110=DIRECTION('',(0.382683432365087,-0.923879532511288,0.));
#3111=AXIS2_PLACEMENT_3D('',#3108,#3109,#3110);
#3112=CIRCLE('',#3111,4.25000000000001);
#3113=EDGE_CURVE('E1313',#755,#1926,#3112,.T.);
#3114=ORIENTED_EDGE('',*,*,#3113,.T.);
#3115=ORIENTED_EDGE('',*,*,#1927,.T.);
#3116=EDGE_LOOP('',(#3106,#3107,#3114,#3115));
#3117=FACE_BOUND('',#3116,.T.);
#3118=ADVANCED_FACE('F2334',(#3117),#3105,.T.);
#3119=EDGE_CURVE('E1306',#1935,#746,#3112,.T.);
#3120=ORIENTED_EDGE('',*,*,#3119,.T.);
#3121=ORIENTED_EDGE('',*,*,#747,.T.);
#3122=ORIENTED_EDGE('',*,*,#3092,.F.);
#3123=ORIENTED_EDGE('',*,*,#1942,.T.);
#3124=EDGE_LOOP('',(#3120,#3121,#3122,#3123));
#3125=FACE_BOUND('',#3124,.T.);
#3126=ADVANCED_FACE('F2335',(#3125),#3105,.T.);
#3127=CARTESIAN_POINT('',(37.4171210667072,15.498679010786,-9.75000000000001));
#3128=DIRECTION('',(0.,0.,1.));
#3129=DIRECTION('',(0.382683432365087,-0.923879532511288,0.));
#3130=AXIS2_PLACEMENT_3D('',#3127,#3128,#3129);
#3131=PLANE('',#3130);
#3132=ORIENTED_EDGE('',*,*,#3113,.F.);
#3133=ORIENTED_EDGE('',*,*,#756,.T.);
#3134=ORIENTED_EDGE('',*,*,#3119,.F.);
#3135=ORIENTED_EDGE('',*,*,#1936,.T.);
#3136=EDGE_LOOP('',(#3132,#3133,#3134,#3135));
#3137=FACE_BOUND('',#3136,.T.);
#3138=ADVANCED_FACE('F2327',(#3137),#3131,.F.);
#3139=CARTESIAN_POINT('',(40.5,-1.41404994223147E-13,9.74999999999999));
#3140=DIRECTION('',(0.,0.,-1.));
#3141=DIRECTION('',(0.,1.,0.));
#3142=AXIS2_PLACEMENT_3D('',#3139,#3140,#3141);
#3143=PLANE('',#3142);
#3144=CARTESIAN_POINT('',(36.25,-1.26566198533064E-13,9.74999999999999));
#3145=DIRECTION('',(0.,0.,1.));
#3146=DIRECTION('',(0.,-1.,0.));
#3147=AXIS2_PLACEMENT_3D('',#3144,#3145,#3146);
#3148=CIRCLE('',#3147,4.25000000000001);
#3149=EDGE_CURVE('E1289',#1624,#436,#3148,.T.);
#3150=ORIENTED_EDGE('',*,*,#3149,.T.);
#3151=ORIENTED_EDGE('',*,*,#437,.T.);
#3152=EDGE_CURVE('E1294',#425,#1607,#3148,.T.);
#3153=ORIENTED_EDGE('',*,*,#3152,.T.);
#3154=ORIENTED_EDGE('',*,*,#1632,.T.);
#3155=EDGE_LOOP('',(#3150,#3151,#3153,#3154));
#3156=FACE_BOUND('',#3155,.T.);
#3157=ADVANCED_FACE('F2323',(#3156),#3143,.F.);
#3158=CARTESIAN_POINT('',(40.5,-1.41404994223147E-13,1.29999999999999));
#3159=DIRECTION('',(0.,0.,1.));
#3160=DIRECTION('',(0.,-1.,0.));
#3161=AXIS2_PLACEMENT_3D('',#3158,#3159,#3160);
#3162=PLANE('',#3161);
#3163=CARTESIAN_POINT('',(36.25,-1.26566198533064E-13,1.29999999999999));
#3164=DIRECTION('',(0.,0.,1.));
#3165=DIRECTION('',(0.,-1.,0.));
#3166=AXIS2_PLACEMENT_3D('',#3163,#3164,#3165);
#3167=CIRCLE('',#3166,4.25);
#3168=EDGE_CURVE('E1292',#427,#1605,#3167,.T.);
#3169=ORIENTED_EDGE('',*,*,#3168,.F.);
#3170=ORIENTED_EDGE('',*,*,#452,.T.);
#3171=EDGE_CURVE('E1291',#1616,#444,#3167,.T.);
#3172=ORIENTED_EDGE('',*,*,#3171,.F.);
#3173=ORIENTED_EDGE('',*,*,#1617,.T.);
#3174=EDGE_LOOP('',(#3169,#3170,#3172,#3173));
#3175=FACE_BOUND('',#3174,.T.);
#3176=ADVANCED_FACE('F2317',(#3175),#3162,.F.);
#3177=CARTESIAN_POINT('',(36.25,-1.26566198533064E-13,9.74999999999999));
#3178=DIRECTION('',(0.,0.,1.));
#3179=DIRECTION('',(0.,-1.,0.));
#3180=AXIS2_PLACEMENT_3D('',#3177,#3178,#3179);
#3181=CYLINDRICAL_SURFACE('',#3180,4.25000000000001);
#3182=ORIENTED_EDGE('',*,*,#3152,.F.);
#3183=ORIENTED_EDGE('',*,*,#428,.T.);
#3184=ORIENTED_EDGE('',*,*,#3168,.T.);
#3185=ORIENTED_EDGE('',*,*,#1608,.T.);
#3186=EDGE_LOOP('',(#3182,#3183,#3184,#3185));
#3187=FACE_BOUND('',#3186,.T.);
#3188=ADVANCED_FACE('F2316',(#3187),#3181,.T.);
#3189=ORIENTED_EDGE('',*,*,#3171,.T.);
#3190=ORIENTED_EDGE('',*,*,#445,.T.);
#3191=ORIENTED_EDGE('',*,*,#3149,.F.);
#3192=ORIENTED_EDGE('',*,*,#1625,.T.);
#3193=EDGE_LOOP('',(#3189,#3190,#3191,#3192));
#3194=FACE_BOUND('',#3193,.T.);
#3195=ADVANCED_FACE('F2313',(#3194),#3181,.T.);
#3196=CARTESIAN_POINT('',(40.5,-1.41404994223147E-13,-1.30000000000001));
#3197=DIRECTION('',(0.,0.,-1.));
#3198=DIRECTION('',(0.,1.,0.));
#3199=AXIS2_PLACEMENT_3D('',#3196,#3197,#3198);
#3200=PLANE('',#3199);
#3201=CARTESIAN_POINT('',(36.25,-1.26566198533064E-13,-1.30000000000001));
#3202=DIRECTION('',(0.,0.,1.));
#3203=DIRECTION('',(0.,-1.,0.));
#3204=AXIS2_PLACEMENT_3D('',#3201,#3202,#3203);
#3205=CIRCLE('',#3204,4.25);
#3206=EDGE_CURVE('E1271',#1954,#772,#3205,.T.);
#3207=ORIENTED_EDGE('',*,*,#3206,.T.);
#3208=ORIENTED_EDGE('',*,*,#775,.T.);
#3209=EDGE_CURVE('E1272',#774,#1952,#3205,.T.);
#3210=ORIENTED_EDGE('',*,*,#3209,.T.);
#3211=ORIENTED_EDGE('',*,*,#1955,.T.);
#3212=EDGE_LOOP('',(#3207,#3208,#3210,#3211));
#3213=FACE_BOUND('',#3212,.T.);
#3214=ADVANCED_FACE('F2312',(#3213),#3200,.F.);
#3215=CARTESIAN_POINT('',(36.25,-1.26566198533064E-13,9.74999999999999));
#3216=DIRECTION('',(0.,0.,1.));
#3217=DIRECTION('',(0.,-1.,0.));
#3218=AXIS2_PLACEMENT_3D('',#3215,#3216,#3217);
#3219=CYLINDRICAL_SURFACE('',#3218,4.25000000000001);
#3220=ORIENTED_EDGE('',*,*,#3209,.F.);
#3221=ORIENTED_EDGE('',*,*,#798,.T.);
#3222=CARTESIAN_POINT('',(36.25,-1.26566198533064E-13,-9.75000000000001));
#3223=DIRECTION('',(0.,0.,1.));
#3224=DIRECTION('',(0.,-1.,0.));
#3225=AXIS2_PLACEMENT_3D('',#3222,#3223,#3224);
#3226=CIRCLE('',#3225,4.25000000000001);
#3227=EDGE_CURVE('E1274',#791,#1962,#3226,.T.);
#3228=ORIENTED_EDGE('',*,*,#3227,.T.);
#3229=ORIENTED_EDGE('',*,*,#1963,.T.);
#3230=EDGE_LOOP('',(#3220,#3221,#3228,#3229));
#3231=FACE_BOUND('',#3230,.T.);
#3232=ADVANCED_FACE('F2309',(#3231),#3219,.T.);
#3233=EDGE_CURVE('E1270',#1971,#782,#3226,.T.);
#3234=ORIENTED_EDGE('',*,*,#3233,.T.);
#3235=ORIENTED_EDGE('',*,*,#783,.T.);
#3236=ORIENTED_EDGE('',*,*,#3206,.F.);
#3237=ORIENTED_EDGE('',*,*,#1978,.T.);
#3238=EDGE_LOOP('',(#3234,#3235,#3236,#3237));
#3239=FACE_BOUND('',#3238,.T.);
#3240=ADVANCED_FACE('F2307',(#3239),#3219,.T.);
#3241=CARTESIAN_POINT('',(40.5,-1.41404994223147E-13,-9.75000000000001));
#3242=DIRECTION('',(0.,0.,1.));
#3243=DIRECTION('',(0.,-1.,0.));
#3244=AXIS2_PLACEMENT_3D('',#3241,#3242,#3243);
#3245=PLANE('',#3244);
#3246=ORIENTED_EDGE('',*,*,#3227,.F.);
#3247=ORIENTED_EDGE('',*,*,#792,.T.);
#3248=ORIENTED_EDGE('',*,*,#3233,.F.);
#3249=ORIENTED_EDGE('',*,*,#1972,.T.);
#3250=EDGE_LOOP('',(#3246,#3247,#3248,#3249));
#3251=FACE_BOUND('',#3250,.T.);
#3252=ADVANCED_FACE('F2305',(#3251),#3245,.F.);
#3253=CARTESIAN_POINT('',(37.4171210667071,-15.4986790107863,9.74999999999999));
#3254=DIRECTION('',(0.,0.,-1.));
#3255=DIRECTION('',(0.382683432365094,0.923879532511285,0.));
#3256=AXIS2_PLACEMENT_3D('',#3253,#3254,#3255);
#3257=PLANE('',#3256);
#3258=CARTESIAN_POINT('',(33.4906330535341,-13.8722744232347,9.74999999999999));
#3259=DIRECTION('',(0.,0.,1.));
#3260=DIRECTION('',(-0.382683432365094,-0.923879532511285,0.));
#3261=AXIS2_PLACEMENT_3D('',#3258,#3259,#3260);
#3262=CIRCLE('',#3261,4.25000000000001);
#3263=EDGE_CURVE('E1248',#1588,#400,#3262,.T.);
#3264=ORIENTED_EDGE('',*,*,#3263,.T.);
#3265=ORIENTED_EDGE('',*,*,#401,.T.);
#3266=EDGE_CURVE('E1251',#389,#1571,#3262,.T.);
#3267=ORIENTED_EDGE('',*,*,#3266,.T.);
#3268=ORIENTED_EDGE('',*,*,#1596,.T.);
#3269=EDGE_LOOP('',(#3264,#3265,#3267,#3268));
#3270=FACE_BOUND('',#3269,.T.);
#3271=ADVANCED_FACE('F2298',(#3270),#3257,.F.);
#3272=CARTESIAN_POINT('',(37.4171210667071,-15.4986790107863,1.29999999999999));
#3273=DIRECTION('',(0.,0.,1.));
#3274=DIRECTION('',(-0.382683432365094,-0.923879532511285,0.));
#3275=AXIS2_PLACEMENT_3D('',#3272,#3273,#3274);
#3276=PLANE('',#3275);
#3277=CARTESIAN_POINT('',(33.4906330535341,-13.8722744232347,1.29999999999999));
#3278=DIRECTION('',(0.,0.,1.));
#3279=DIRECTION('',(-0.382683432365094,-0.923879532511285,0.));
#3280=AXIS2_PLACEMENT_3D('',#3277,#3278,#3279);
#3281=CIRCLE('',#3280,4.25);
#3282=EDGE_CURVE('E1254',#391,#1569,#3281,.T.);
#3283=ORIENTED_EDGE('',*,*,#3282,.F.);
#3284=ORIENTED_EDGE('',*,*,#416,.T.);
#3285=EDGE_CURVE('E1255',#1580,#408,#3281,.T.);
#3286=ORIENTED_EDGE('',*,*,#3285,.F.);
#3287=ORIENTED_EDGE('',*,*,#1581,.T.);
#3288=EDGE_LOOP('',(#3283,#3284,#3286,#3287));
#3289=FACE_BOUND('',#3288,.T.);
#3290=ADVANCED_FACE('F2292',(#3289),#3276,.F.);
#3291=CARTESIAN_POINT('',(33.4906330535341,-13.8722744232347,9.74999999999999));
#3292=DIRECTION('',(0.,0.,1.));
#3293=DIRECTION('',(-0.382683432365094,-0.923879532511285,0.));
#3294=AXIS2_PLACEMENT_3D('',#3291,#3292,#3293);
#3295=CYLINDRICAL_SURFACE('',#3294,4.25000000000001);
#3296=ORIENTED_EDGE('',*,*,#3266,.F.);
#3297=ORIENTED_EDGE('',*,*,#392,.T.);
#3298=ORIENTED_EDGE('',*,*,#3282,.T.);
#3299=ORIENTED_EDGE('',*,*,#1572,.T.);
#3300=EDGE_LOOP('',(#3296,#3297,#3298,#3299));
#3301=FACE_BOUND('',#3300,.T.);
#3302=ADVANCED_FACE('F2291',(#3301),#3295,.T.);
#3303=ORIENTED_EDGE('',*,*,#3285,.T.);
#3304=ORIENTED_EDGE('',*,*,#409,.T.);
#3305=ORIENTED_EDGE('',*,*,#3263,.F.);
#3306=ORIENTED_EDGE('',*,*,#1589,.T.);
#3307=EDGE_LOOP('',(#3303,#3304,#3305,#3306));
#3308=FACE_BOUND('',#3307,.T.);
#3309=ADVANCED_FACE('F2289',(#3308),#3295,.T.);
#3310=CARTESIAN_POINT('',(37.4171210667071,-15.4986790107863,-1.30000000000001));
#3311=DIRECTION('',(0.,0.,-1.));
#3312=DIRECTION('',(0.382683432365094,0.923879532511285,0.));
#3313=AXIS2_PLACEMENT_3D('',#3310,#3311,#3312);
#3314=PLANE('',#3313);
#3315=CARTESIAN_POINT('',(33.4906330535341,-13.8722744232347,-1.30000000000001));
#3316=DIRECTION('',(0.,0.,1.));
#3317=DIRECTION('',(-0.382683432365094,-0.923879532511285,0.));
#3318=AXIS2_PLACEMENT_3D('',#3315,#3316,#3317);
#3319=CIRCLE('',#3318,4.25);
#3320=EDGE_CURVE('E1232',#1990,#808,#3319,.T.);
#3321=ORIENTED_EDGE('',*,*,#3320,.T.);
#3322=ORIENTED_EDGE('',*,*,#811,.T.);
#3323=EDGE_CURVE('E1234',#810,#1988,#3319,.T.);
#3324=ORIENTED_EDGE('',*,*,#3323,.T.);
#3325=ORIENTED_EDGE('',*,*,#1991,.T.);
#3326=EDGE_LOOP('',(#3321,#3322,#3324,#3325));
#3327=FACE_BOUND('',#3326,.T.);
#3328=ADVANCED_FACE('F2284',(#3327),#3314,.F.);
#3329=CARTESIAN_POINT('',(33.4906330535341,-13.8722744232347,9.74999999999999));
#3330=DIRECTION('',(0.,0.,1.));
#3331=DIRECTION('',(-0.382683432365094,-0.923879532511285,0.));
#3332=AXIS2_PLACEMENT_3D('',#3329,#3330,#3331);
#3333=CYLINDRICAL_SURFACE('',#3332,4.25000000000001);
#3334=ORIENTED_EDGE('',*,*,#3323,.F.);
#3335=ORIENTED_EDGE('',*,*,#834,.T.);
#3336=CARTESIAN_POINT('',(33.4906330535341,-13.8722744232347,-9.75000000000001));
#3337=DIRECTION('',(0.,0.,1.));
#3338=DIRECTION('',(-0.382683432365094,-0.923879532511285,0.));
#3339=AXIS2_PLACEMENT_3D('',#3336,#3337,#3338);
#3340=CIRCLE('',#3339,4.25000000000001);
#3341=EDGE_CURVE('E1233',#827,#1998,#3340,.T.);
#3342=ORIENTED_EDGE('',*,*,#3341,.T.);
#3343=ORIENTED_EDGE('',*,*,#1999,.T.);
#3344=EDGE_LOOP('',(#3334,#3335,#3342,#3343));
#3345=FACE_BOUND('',#3344,.T.);
#3346=ADVANCED_FACE('F2282',(#3345),#3333,.T.);
#3347=EDGE_CURVE('E1227',#2007,#818,#3340,.T.);
#3348=ORIENTED_EDGE('',*,*,#3347,.T.);
#3349=ORIENTED_EDGE('',*,*,#819,.T.);
#3350=ORIENTED_EDGE('',*,*,#3320,.F.);
#3351=ORIENTED_EDGE('',*,*,#2014,.T.);
#3352=EDGE_LOOP('',(#3348,#3349,#3350,#3351));
#3353=FACE_BOUND('',#3352,.T.);
#3354=ADVANCED_FACE('F2276',(#3353),#3333,.T.);
#3355=CARTESIAN_POINT('',(37.4171210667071,-15.4986790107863,-9.75000000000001));
#3356=DIRECTION('',(0.,0.,1.));
#3357=DIRECTION('',(-0.382683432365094,-0.923879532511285,0.));
#3358=AXIS2_PLACEMENT_3D('',#3355,#3356,#3357);
#3359=PLANE('',#3358);
#3360=ORIENTED_EDGE('',*,*,#3341,.F.);
#3361=ORIENTED_EDGE('',*,*,#828,.T.);
#3362=ORIENTED_EDGE('',*,*,#3347,.F.);
#3363=ORIENTED_EDGE('',*,*,#2008,.T.);
#3364=EDGE_LOOP('',(#3360,#3361,#3362,#3363));
#3365=FACE_BOUND('',#3364,.T.);
#3366=ADVANCED_FACE('F2278',(#3365),#3359,.F.);
#3367=CARTESIAN_POINT('',(28.637824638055,-28.6378246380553,9.74999999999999));
#3368=DIRECTION('',(0.,0.,-1.));
#3369=DIRECTION('',(0.707106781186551,0.707106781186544,0.));
#3370=AXIS2_PLACEMENT_3D('',#3367,#3368,#3369);
#3371=PLANE('',#3370);
#3372=CARTESIAN_POINT('',(25.6326208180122,-25.6326208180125,9.74999999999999));
#3373=DIRECTION('',(0.,0.,1.));
#3374=DIRECTION('',(-0.707106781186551,-0.707106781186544,0.));
#3375=AXIS2_PLACEMENT_3D('',#3372,#3373,#3374);
#3376=CIRCLE('',#3375,4.25000000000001);
#3377=EDGE_CURVE('E1206',#1552,#364,#3376,.T.);
#3378=ORIENTED_EDGE('',*,*,#3377,.T.);
#3379=ORIENTED_EDGE('',*,*,#365,.T.);
#3380=EDGE_CURVE('E1212',#353,#1535,#3376,.T.);
#3381=ORIENTED_EDGE('',*,*,#3380,.T.);
#3382=ORIENTED_EDGE('',*,*,#1560,.T.);
#3383=EDGE_LOOP('',(#3378,#3379,#3381,#3382));
#3384=FACE_BOUND('',#3383,.T.);
#3385=ADVANCED_FACE('F2271',(#3384),#3371,.F.);
#3386=CARTESIAN_POINT('',(28.637824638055,-28.6378246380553,1.29999999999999));
#3387=DIRECTION('',(0.,0.,1.));
#3388=DIRECTION('',(-0.707106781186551,-0.707106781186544,0.));
#3389=AXIS2_PLACEMENT_3D('',#3386,#3387,#3388);
#3390=PLANE('',#3389);
#3391=CARTESIAN_POINT('',(25.6326208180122,-25.6326208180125,1.29999999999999));
#3392=DIRECTION('',(0.,0.,1.));
#3393=DIRECTION('',(-0.707106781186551,-0.707106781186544,0.));
#3394=AXIS2_PLACEMENT_3D('',#3391,#3392,#3393);
#3395=CIRCLE('',#3394,4.25);
#3396=EDGE_CURVE('E1213',#355,#1533,#3395,.T.);
#3397=ORIENTED_EDGE('',*,*,#3396,.F.);
#3398=ORIENTED_EDGE('',*,*,#380,.T.);
#3399=EDGE_CURVE('E1215',#1544,#372,#3395,.T.);
#3400=ORIENTED_EDGE('',*,*,#3399,.F.);
#3401=ORIENTED_EDGE('',*,*,#1545,.T.);
#3402=EDGE_LOOP('',(#3397,#3398,#3400,#3401));
#3403=FACE_BOUND('',#3402,.T.);
#3404=ADVANCED_FACE('F2270',(#3403),#3390,.F.);
#3405=CARTESIAN_POINT('',(25.6326208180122,-25.6326208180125,9.74999999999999));
#3406=DIRECTION('',(0.,0.,1.));
#3407=DIRECTION('',(-0.707106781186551,-0.707106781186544,0.));
#3408=AXIS2_PLACEMENT_3D('',#3405,#3406,#3407);
#3409=CYLINDRICAL_SURFACE('',#3408,4.25000000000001);
#3410=ORIENTED_EDGE('',*,*,#3380,.F.);
#3411=ORIENTED_EDGE('',*,*,#356,.T.);
#3412=ORIENTED_EDGE('',*,*,#3396,.T.);
#3413=ORIENTED_EDGE('',*,*,#1536,.T.);
#3414=EDGE_LOOP('',(#3410,#3411,#3412,#3413));
#3415=FACE_BOUND('',#3414,.T.);
#3416=ADVANCED_FACE('F2263',(#3415),#3409,.T.);
#3417=ORIENTED_EDGE('',*,*,#3399,.T.);
#3418=ORIENTED_EDGE('',*,*,#373,.T.);
#3419=ORIENTED_EDGE('',*,*,#3377,.F.);
#3420=ORIENTED_EDGE('',*,*,#1553,.T.);
#3421=EDGE_LOOP('',(#3417,#3418,#3419,#3420));
#3422=FACE_BOUND('',#3421,.T.);
#3423=ADVANCED_FACE('F2264',(#3422),#3409,.T.);
#3424=CARTESIAN_POINT('',(28.637824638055,-28.6378246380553,-1.30000000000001));
#3425=DIRECTION('',(0.,0.,-1.));
#3426=DIRECTION('',(0.707106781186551,0.707106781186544,0.));
#3427=AXIS2_PLACEMENT_3D('',#3424,#3425,#3426);
#3428=PLANE('',#3427);
#3429=CARTESIAN_POINT('',(25.6326208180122,-25.6326208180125,-1.30000000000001));
#3430=DIRECTION('',(0.,0.,1.));
#3431=DIRECTION('',(-0.707106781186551,-0.707106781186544,0.));
#3432=AXIS2_PLACEMENT_3D('',#3429,#3430,#3431);
#3433=CIRCLE('',#3432,4.25);
#3434=EDGE_CURVE('E1191',#2026,#844,#3433,.T.);
#3435=ORIENTED_EDGE('',*,*,#3434,.T.);
#3436=ORIENTED_EDGE('',*,*,#847,.T.);
#3437=EDGE_CURVE('E1192',#846,#2024,#3433,.T.);
#3438=ORIENTED_EDGE('',*,*,#3437,.T.);
#3439=ORIENTED_EDGE('',*,*,#2027,.T.);
#3440=EDGE_LOOP('',(#3435,#3436,#3438,#3439));
#3441=FACE_BOUND('',#3440,.T.);
#3442=ADVANCED_FACE('F2259',(#3441),#3428,.F.);
#3443=CARTESIAN_POINT('',(25.6326208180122,-25.6326208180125,9.74999999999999));
#3444=DIRECTION('',(0.,0.,1.));
#3445=DIRECTION('',(-0.707106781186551,-0.707106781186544,0.));
#3446=AXIS2_PLACEMENT_3D('',#3443,#3444,#3445);
#3447=CYLINDRICAL_SURFACE('',#3446,4.25000000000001);
#3448=ORIENTED_EDGE('',*,*,#3437,.F.);
#3449=ORIENTED_EDGE('',*,*,#870,.T.);
#3450=CARTESIAN_POINT('',(25.6326208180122,-25.6326208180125,-9.75000000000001));
#3451=DIRECTION('',(0.,0.,1.));
#3452=DIRECTION('',(-0.707106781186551,-0.707106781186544,0.));
#3453=AXIS2_PLACEMENT_3D('',#3450,#3451,#3452);
#3454=CIRCLE('',#3453,4.25000000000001);
#3455=EDGE_CURVE('E1194',#863,#2034,#3454,.T.);
#3456=ORIENTED_EDGE('',*,*,#3455,.T.);
#3457=ORIENTED_EDGE('',*,*,#2035,.T.);
#3458=EDGE_LOOP('',(#3448,#3449,#3456,#3457));
#3459=FACE_BOUND('',#3458,.T.);
#3460=ADVANCED_FACE('F2257',(#3459),#3447,.T.);
#3461=EDGE_CURVE('E1189',#2043,#854,#3454,.T.);
#3462=ORIENTED_EDGE('',*,*,#3461,.T.);
#3463=ORIENTED_EDGE('',*,*,#855,.T.);
#3464=ORIENTED_EDGE('',*,*,#3434,.F.);
#3465=ORIENTED_EDGE('',*,*,#2050,.T.);
#3466=EDGE_LOOP('',(#3462,#3463,#3464,#3465));
#3467=FACE_BOUND('',#3466,.T.);
#3468=ADVANCED_FACE('F2255',(#3467),#3447,.T.);
#3469=CARTESIAN_POINT('',(28.637824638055,-28.6378246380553,-9.75000000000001));
#3470=DIRECTION('',(0.,0.,1.));
#3471=DIRECTION('',(-0.707106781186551,-0.707106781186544,0.));
#3472=AXIS2_PLACEMENT_3D('',#3469,#3470,#3471);
#3473=PLANE('',#3472);
#3474=ORIENTED_EDGE('',*,*,#3455,.F.);
#3475=ORIENTED_EDGE('',*,*,#864,.T.);
#3476=ORIENTED_EDGE('',*,*,#3461,.F.);
#3477=ORIENTED_EDGE('',*,*,#2044,.T.);
#3478=EDGE_LOOP('',(#3474,#3475,#3476,#3477));
#3479=FACE_BOUND('',#3478,.T.);
#3480=ADVANCED_FACE('F2247',(#3479),#3473,.F.);
#3481=CARTESIAN_POINT('',(15.4986790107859,-37.4171210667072,9.74999999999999));
#3482=DIRECTION('',(0.,0.,-1.));
#3483=DIRECTION('',(0.923879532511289,0.382683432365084,0.));
#3484=AXIS2_PLACEMENT_3D('',#3481,#3482,#3483);
#3485=PLANE('',#3484);
#3486=CARTESIAN_POINT('',(13.8722744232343,-33.4906330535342,9.74999999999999));
#3487=DIRECTION('',(0.,0.,1.));
#3488=DIRECTION('',(-0.923879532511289,-0.382683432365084,0.));
#3489=AXIS2_PLACEMENT_3D('',#3486,#3487,#3488);
#3490=CIRCLE('',#3489,4.25000000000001);
#3491=EDGE_CURVE('E1168',#1516,#328,#3490,.T.);
#3492=ORIENTED_EDGE('',*,*,#3491,.T.);
#3493=ORIENTED_EDGE('',*,*,#329,.T.);
#3494=EDGE_CURVE('E1171',#317,#1499,#3490,.T.);
#3495=ORIENTED_EDGE('',*,*,#3494,.T.);
#3496=ORIENTED_EDGE('',*,*,#1524,.T.);
#3497=EDGE_LOOP('',(#3492,#3493,#3495,#3496));
#3498=FACE_BOUND('',#3497,.T.);
#3499=ADVANCED_FACE('F2249',(#3498),#3485,.F.);
#3500=CARTESIAN_POINT('',(15.4986790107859,-37.4171210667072,1.29999999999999));
#3501=DIRECTION('',(0.,0.,1.));
#3502=DIRECTION('',(-0.923879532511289,-0.382683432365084,0.));
#3503=AXIS2_PLACEMENT_3D('',#3500,#3501,#3502);
#3504=PLANE('',#3503);
#3505=CARTESIAN_POINT('',(13.8722744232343,-33.4906330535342,1.29999999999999));
#3506=DIRECTION('',(0.,0.,1.));
#3507=DIRECTION('',(-0.923879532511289,-0.382683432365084,0.));
#3508=AXIS2_PLACEMENT_3D('',#3505,#3506,#3507);
#3509=CIRCLE('',#3508,4.25);
#3510=EDGE_CURVE('E1174',#319,#1497,#3509,.T.);
#3511=ORIENTED_EDGE('',*,*,#3510,.F.);
#3512=ORIENTED_EDGE('',*,*,#344,.T.);
#3513=EDGE_CURVE('E1175',#1508,#336,#3509,.T.);
#3514=ORIENTED_EDGE('',*,*,#3513,.F.);
#3515=ORIENTED_EDGE('',*,*,#1509,.T.);
#3516=EDGE_LOOP('',(#3511,#3512,#3514,#3515));
#3517=FACE_BOUND('',#3516,.T.);
#3518=ADVANCED_FACE('F2241',(#3517),#3504,.F.);
#3519=CARTESIAN_POINT('',(13.8722744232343,-33.4906330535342,9.74999999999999));
#3520=DIRECTION('',(0.,0.,1.));
#3521=DIRECTION('',(-0.923879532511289,-0.382683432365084,0.));
#3522=AXIS2_PLACEMENT_3D('',#3519,#3520,#3521);
#3523=CYLINDRICAL_SURFACE('',#3522,4.25000000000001);
#3524=ORIENTED_EDGE('',*,*,#3494,.F.);
#3525=ORIENTED_EDGE('',*,*,#320,.T.);
#3526=ORIENTED_EDGE('',*,*,#3510,.T.);
#3527=ORIENTED_EDGE('',*,*,#1500,.T.);
#3528=EDGE_LOOP('',(#3524,#3525,#3526,#3527));
#3529=FACE_BOUND('',#3528,.T.);
#3530=ADVANCED_FACE('F2236',(#3529),#3523,.T.);
#3531=ORIENTED_EDGE('',*,*,#3513,.T.);
#3532=ORIENTED_EDGE('',*,*,#337,.T.);
#3533=ORIENTED_EDGE('',*,*,#3491,.F.);
#3534=ORIENTED_EDGE('',*,*,#1517,.T.);
#3535=EDGE_LOOP('',(#3531,#3532,#3533,#3534));
#3536=FACE_BOUND('',#3535,.T.);
#3537=ADVANCED_FACE('F2240',(#3536),#3523,.T.);
#3538=CARTESIAN_POINT('',(15.4986790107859,-37.4171210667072,-1.30000000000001));
#3539=DIRECTION('',(0.,0.,-1.));
#3540=DIRECTION('',(0.923879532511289,0.382683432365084,0.));
#3541=AXIS2_PLACEMENT_3D('',#3538,#3539,#3540);
#3542=PLANE('',#3541);
#3543=CARTESIAN_POINT('',(13.8722744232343,-33.4906330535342,-1.30000000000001));
#3544=DIRECTION('',(0.,0.,1.));
#3545=DIRECTION('',(-0.923879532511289,-0.382683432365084,0.));
#3546=AXIS2_PLACEMENT_3D('',#3543,#3544,#3545);
#3547=CIRCLE('',#3546,4.25);
#3548=EDGE_CURVE('E1154',#2062,#880,#3547,.T.);
#3549=ORIENTED_EDGE('',*,*,#3548,.T.);
#3550=ORIENTED_EDGE('',*,*,#883,.T.);
#3551=EDGE_CURVE('E1151',#882,#2060,#3547,.T.);
#3552=ORIENTED_EDGE('',*,*,#3551,.T.);
#3553=ORIENTED_EDGE('',*,*,#2063,.T.);
#3554=EDGE_LOOP('',(#3549,#3550,#3552,#3553));
#3555=FACE_BOUND('',#3554,.T.);
#3556=ADVANCED_FACE('F2234',(#3555),#3542,.F.);
#3557=CARTESIAN_POINT('',(13.8722744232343,-33.4906330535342,9.74999999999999));
#3558=DIRECTION('',(0.,0.,1.));
#3559=DIRECTION('',(-0.923879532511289,-0.382683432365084,0.));
#3560=AXIS2_PLACEMENT_3D('',#3557,#3558,#3559);
#3561=CYLINDRICAL_SURFACE('',#3560,4.25000000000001);
#3562=ORIENTED_EDGE('',*,*,#3551,.F.);
#3563=ORIENTED_EDGE('',*,*,#906,.T.);
#3564=CARTESIAN_POINT('',(13.8722744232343,-33.4906330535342,-9.75000000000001));
#3565=DIRECTION('',(0.,0.,1.));
#3566=DIRECTION('',(-0.923879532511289,-0.382683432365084,0.));
#3567=AXIS2_PLACEMENT_3D('',#3564,#3565,#3566);
#3568=CIRCLE('',#3567,4.25000000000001);
#3569=EDGE_CURVE('E1153',#899,#2070,#3568,.T.);
#3570=ORIENTED_EDGE('',*,*,#3569,.T.);
#3571=ORIENTED_EDGE('',*,*,#2071,.T.);
#3572=EDGE_LOOP('',(#3562,#3563,#3570,#3571));
#3573=FACE_BOUND('',#3572,.T.);
#3574=ADVANCED_FACE('F2229',(#3573),#3561,.T.);
#3575=EDGE_CURVE('E1150',#2079,#890,#3568,.T.);
#3576=ORIENTED_EDGE('',*,*,#3575,.T.);
#3577=ORIENTED_EDGE('',*,*,#891,.T.);
#3578=ORIENTED_EDGE('',*,*,#3548,.F.);
#3579=ORIENTED_EDGE('',*,*,#2086,.T.);
#3580=EDGE_LOOP('',(#3576,#3577,#3578,#3579));
#3581=FACE_BOUND('',#3580,.T.);
#3582=ADVANCED_FACE('F2227',(#3581),#3561,.T.);
#3583=CARTESIAN_POINT('',(15.4986790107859,-37.4171210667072,-9.75000000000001));
#3584=DIRECTION('',(0.,0.,1.));
#3585=DIRECTION('',(-0.923879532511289,-0.382683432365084,0.));
#3586=AXIS2_PLACEMENT_3D('',#3583,#3584,#3585);
#3587=PLANE('',#3586);
#3588=ORIENTED_EDGE('',*,*,#3569,.F.);
#3589=ORIENTED_EDGE('',*,*,#900,.T.);
#3590=ORIENTED_EDGE('',*,*,#3575,.F.);
#3591=ORIENTED_EDGE('',*,*,#2080,.T.);
#3592=EDGE_LOOP('',(#3588,#3589,#3590,#3591));
#3593=FACE_BOUND('',#3592,.T.);
#3594=ADVANCED_FACE('F2222',(#3593),#3587,.F.);
#3595=CARTESIAN_POINT('',(-2.82809988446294E-13,-40.5,9.74999999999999));
#3596=DIRECTION('',(0.,0.,-1.));
#3597=DIRECTION('',(1.,0.,0.));
#3598=AXIS2_PLACEMENT_3D('',#3595,#3596,#3597);
#3599=PLANE('',#3598);
#3600=CARTESIAN_POINT('',(-2.53132397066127E-13,-36.25,9.74999999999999));
#3601=DIRECTION('',(0.,0.,1.));
#3602=DIRECTION('',(-1.,0.,0.));
#3603=AXIS2_PLACEMENT_3D('',#3600,#3601,#3602);
#3604=CIRCLE('',#3603,4.25000000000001);
#3605=EDGE_CURVE('E1127',#1480,#292,#3604,.T.);
#3606=ORIENTED_EDGE('',*,*,#3605,.T.);
#3607=ORIENTED_EDGE('',*,*,#293,.T.);
#3608=EDGE_CURVE('E1132',#281,#1463,#3604,.T.);
#3609=ORIENTED_EDGE('',*,*,#3608,.T.);
#3610=ORIENTED_EDGE('',*,*,#1488,.T.);
#3611=EDGE_LOOP('',(#3606,#3607,#3609,#3610));
#3612=FACE_BOUND('',#3611,.T.);
#3613=ADVANCED_FACE('F2219',(#3612),#3599,.F.);
#3614=CARTESIAN_POINT('',(-2.82809988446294E-13,-40.5,1.29999999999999));
#3615=DIRECTION('',(0.,0.,1.));
#3616=DIRECTION('',(-1.,0.,0.));
#3617=AXIS2_PLACEMENT_3D('',#3614,#3615,#3616);
#3618=PLANE('',#3617);
#3619=CARTESIAN_POINT('',(-2.53132397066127E-13,-36.25,1.29999999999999));
#3620=DIRECTION('',(0.,0.,1.));
#3621=DIRECTION('',(-1.,0.,0.));
#3622=AXIS2_PLACEMENT_3D('',#3619,#3620,#3621);
#3623=CIRCLE('',#3622,4.25);
#3624=EDGE_CURVE('E1133',#283,#1461,#3623,.T.);
#3625=ORIENTED_EDGE('',*,*,#3624,.F.);
#3626=ORIENTED_EDGE('',*,*,#308,.T.);
#3627=EDGE_CURVE('E1135',#1472,#300,#3623,.T.);
#3628=ORIENTED_EDGE('',*,*,#3627,.F.);
#3629=ORIENTED_EDGE('',*,*,#1473,.T.);
#3630=EDGE_LOOP('',(#3625,#3626,#3628,#3629));
#3631=FACE_BOUND('',#3630,.T.);
#3632=ADVANCED_FACE('F2216',(#3631),#3618,.F.);
#3633=CARTESIAN_POINT('',(-2.53132397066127E-13,-36.25,9.74999999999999));
#3634=DIRECTION('',(0.,0.,1.));
#3635=DIRECTION('',(-1.,0.,0.));
#3636=AXIS2_PLACEMENT_3D('',#3633,#3634,#3635);
#3637=CYLINDRICAL_SURFACE('',#3636,4.25000000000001);
#3638=ORIENTED_EDGE('',*,*,#3608,.F.);
#3639=ORIENTED_EDGE('',*,*,#284,.T.);
#3640=ORIENTED_EDGE('',*,*,#3624,.T.);
#3641=ORIENTED_EDGE('',*,*,#1464,.T.);
#3642=EDGE_LOOP('',(#3638,#3639,#3640,#3641));
#3643=FACE_BOUND('',#3642,.T.);
#3644=ADVANCED_FACE('F2211',(#3643),#3637,.T.);
#3645=ORIENTED_EDGE('',*,*,#3627,.T.);
#3646=ORIENTED_EDGE('',*,*,#301,.T.);
#3647=ORIENTED_EDGE('',*,*,#3605,.F.);
#3648=ORIENTED_EDGE('',*,*,#1481,.T.);
#3649=EDGE_LOOP('',(#3645,#3646,#3647,#3648));
#3650=FACE_BOUND('',#3649,.T.);
#3651=ADVANCED_FACE('F2213',(#3650),#3637,.T.);
#3652=CARTESIAN_POINT('',(-2.82809988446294E-13,-40.5,-1.30000000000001));
#3653=DIRECTION('',(0.,0.,-1.));
#3654=DIRECTION('',(1.,0.,0.));
#3655=AXIS2_PLACEMENT_3D('',#3652,#3653,#3654);
#3656=PLANE('',#3655);
#3657=CARTESIAN_POINT('',(-2.53132397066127E-13,-36.25,-1.30000000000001));
#3658=DIRECTION('',(0.,0.,1.));
#3659=DIRECTION('',(-1.,0.,0.));
#3660=AXIS2_PLACEMENT_3D('',#3657,#3658,#3659);
#3661=CIRCLE('',#3660,4.25);
#3662=EDGE_CURVE('E1115',#2098,#916,#3661,.T.);
#3663=ORIENTED_EDGE('',*,*,#3662,.T.);
#3664=ORIENTED_EDGE('',*,*,#919,.T.);
#3665=EDGE_CURVE('E1113',#918,#2096,#3661,.T.);
#3666=ORIENTED_EDGE('',*,*,#3665,.T.);
#3667=ORIENTED_EDGE('',*,*,#2099,.T.);
#3668=EDGE_LOOP('',(#3663,#3664,#3666,#3667));
#3669=FACE_BOUND('',#3668,.T.);
#3670=ADVANCED_FACE('F2207',(#3669),#3656,.F.);
#3671=CARTESIAN_POINT('',(-2.53132397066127E-13,-36.25,9.74999999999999));
#3672=DIRECTION('',(0.,0.,1.));
#3673=DIRECTION('',(-1.,0.,0.));
#3674=AXIS2_PLACEMENT_3D('',#3671,#3672,#3673);
#3675=CYLINDRICAL_SURFACE('',#3674,4.25000000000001);
#3676=ORIENTED_EDGE('',*,*,#3665,.F.);
#3677=ORIENTED_EDGE('',*,*,#942,.T.);
#3678=CARTESIAN_POINT('',(-2.53132397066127E-13,-36.25,-9.75000000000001));
#3679=DIRECTION('',(0.,0.,1.));
#3680=DIRECTION('',(-1.,0.,0.));
#3681=AXIS2_PLACEMENT_3D('',#3678,#3679,#3680);
#3682=CIRCLE('',#3681,4.25000000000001);
#3683=EDGE_CURVE('E1112',#935,#2106,#3682,.T.);
#3684=ORIENTED_EDGE('',*,*,#3683,.T.);
#3685=ORIENTED_EDGE('',*,*,#2107,.T.);
#3686=EDGE_LOOP('',(#3676,#3677,#3684,#3685));
#3687=FACE_BOUND('',#3686,.T.);
#3688=ADVANCED_FACE('F2205',(#3687),#3675,.T.);
#3689=EDGE_CURVE('E1109',#2115,#926,#3682,.T.);
#3690=ORIENTED_EDGE('',*,*,#3689,.T.);
#3691=ORIENTED_EDGE('',*,*,#927,.T.);
#3692=ORIENTED_EDGE('',*,*,#3662,.F.);
#3693=ORIENTED_EDGE('',*,*,#2122,.T.);
#3694=EDGE_LOOP('',(#3690,#3691,#3692,#3693));
#3695=FACE_BOUND('',#3694,.T.);
#3696=ADVANCED_FACE('F2204',(#3695),#3675,.T.);
#3697=CARTESIAN_POINT('',(-2.82809988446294E-13,-40.5,-9.75000000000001));
#3698=DIRECTION('',(0.,0.,1.));
#3699=DIRECTION('',(-1.,0.,0.));
#3700=AXIS2_PLACEMENT_3D('',#3697,#3698,#3699);
#3701=PLANE('',#3700);
#3702=ORIENTED_EDGE('',*,*,#3683,.F.);
#3703=ORIENTED_EDGE('',*,*,#936,.T.);
#3704=ORIENTED_EDGE('',*,*,#3689,.F.);
#3705=ORIENTED_EDGE('',*,*,#2116,.T.);
#3706=EDGE_LOOP('',(#3702,#3703,#3704,#3705));
#3707=FACE_BOUND('',#3706,.T.);
#3708=ADVANCED_FACE('F2200',(#3707),#3701,.F.);
#3709=CARTESIAN_POINT('',(-15.4986790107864,-37.417121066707,9.74999999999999));
#3710=DIRECTION('',(0.,0.,-1.));
#3711=DIRECTION('',(0.923879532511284,-0.382683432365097,0.));
#3712=AXIS2_PLACEMENT_3D('',#3709,#3710,#3711);
#3713=PLANE('',#3712);
#3714=CARTESIAN_POINT('',(-13.8722744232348,-33.490633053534,9.74999999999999));
#3715=DIRECTION('',(0.,0.,1.));
#3716=DIRECTION('',(-0.923879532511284,0.382683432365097,0.));
#3717=AXIS2_PLACEMENT_3D('',#3714,#3715,#3716);
#3718=CIRCLE('',#3717,4.25000000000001);
#3719=EDGE_CURVE('E1086',#1444,#256,#3718,.T.);
#3720=ORIENTED_EDGE('',*,*,#3719,.T.);
#3721=ORIENTED_EDGE('',*,*,#257,.T.);
#3722=EDGE_CURVE('E1091',#245,#1427,#3718,.T.);
#3723=ORIENTED_EDGE('',*,*,#3722,.T.);
#3724=ORIENTED_EDGE('',*,*,#1452,.T.);
#3725=EDGE_LOOP('',(#3720,#3721,#3723,#3724));
#3726=FACE_BOUND('',#3725,.T.);
#3727=ADVANCED_FACE('F2193',(#3726),#3713,.F.);
#3728=CARTESIAN_POINT('',(-15.4986790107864,-37.417121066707,1.29999999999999));
#3729=DIRECTION('',(0.,0.,1.));
#3730=DIRECTION('',(-0.923879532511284,0.382683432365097,0.));
#3731=AXIS2_PLACEMENT_3D('',#3728,#3729,#3730);
#3732=PLANE('',#3731);
#3733=CARTESIAN_POINT('',(-13.8722744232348,-33.490633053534,1.29999999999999));
#3734=DIRECTION('',(0.,0.,1.));
#3735=DIRECTION('',(-0.923879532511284,0.382683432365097,0.));
#3736=AXIS2_PLACEMENT_3D('',#3733,#3734,#3735);
#3737=CIRCLE('',#3736,4.25);
#3738=EDGE_CURVE('E1094',#247,#1425,#3737,.T.);
#3739=ORIENTED_EDGE('',*,*,#3738,.F.);
#3740=ORIENTED_EDGE('',*,*,#272,.T.);
#3741=EDGE_CURVE('E1095',#1436,#264,#3737,.T.);
#3742=ORIENTED_EDGE('',*,*,#3741,.F.);
#3743=ORIENTED_EDGE('',*,*,#1437,.T.);
#3744=EDGE_LOOP('',(#3739,#3740,#3742,#3743));
#3745=FACE_BOUND('',#3744,.T.);
#3746=ADVANCED_FACE('F2188',(#3745),#3732,.F.);
#3747=CARTESIAN_POINT('',(-13.8722744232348,-33.490633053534,9.74999999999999));
#3748=DIRECTION('',(0.,0.,1.));
#3749=DIRECTION('',(-0.923879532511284,0.382683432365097,0.));
#3750=AXIS2_PLACEMENT_3D('',#3747,#3748,#3749);
#3751=CYLINDRICAL_SURFACE('',#3750,4.25000000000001);
#3752=ORIENTED_EDGE('',*,*,#3722,.F.);
#3753=ORIENTED_EDGE('',*,*,#248,.T.);
#3754=ORIENTED_EDGE('',*,*,#3738,.T.);
#3755=ORIENTED_EDGE('',*,*,#1428,.T.);
#3756=EDGE_LOOP('',(#3752,#3753,#3754,#3755));
#3757=FACE_BOUND('',#3756,.T.);
#3758=ADVANCED_FACE('F2190',(#3757),#3751,.T.);
#3759=ORIENTED_EDGE('',*,*,#3741,.T.);
#3760=ORIENTED_EDGE('',*,*,#265,.T.);
#3761=ORIENTED_EDGE('',*,*,#3719,.F.);
#3762=ORIENTED_EDGE('',*,*,#1445,.T.);
#3763=EDGE_LOOP('',(#3759,#3760,#3761,#3762));
#3764=FACE_BOUND('',#3763,.T.);
#3765=ADVANCED_FACE('F2183',(#3764),#3751,.T.);
#3766=CARTESIAN_POINT('',(-15.4986790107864,-37.417121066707,-1.30000000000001));
#3767=DIRECTION('',(0.,0.,-1.));
#3768=DIRECTION('',(0.923879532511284,-0.382683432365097,0.));
#3769=AXIS2_PLACEMENT_3D('',#3766,#3767,#3768);
#3770=PLANE('',#3769);
#3771=CARTESIAN_POINT('',(-13.8722744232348,-33.490633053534,-1.30000000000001));
#3772=DIRECTION('',(0.,0.,1.));
#3773=DIRECTION('',(-0.923879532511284,0.382683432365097,0.));
#3774=AXIS2_PLACEMENT_3D('',#3771,#3772,#3773);
#3775=CIRCLE('',#3774,4.25);
#3776=EDGE_CURVE('E1071',#2134,#952,#3775,.T.);
#3777=ORIENTED_EDGE('',*,*,#3776,.T.);
#3778=ORIENTED_EDGE('',*,*,#955,.T.);
#3779=EDGE_CURVE('E1072',#954,#2132,#3775,.T.);
#3780=ORIENTED_EDGE('',*,*,#3779,.T.);
#3781=ORIENTED_EDGE('',*,*,#2135,.T.);
#3782=EDGE_LOOP('',(#3777,#3778,#3780,#3781));
#3783=FACE_BOUND('',#3782,.T.);
#3784=ADVANCED_FACE('F2182',(#3783),#3770,.F.);
#3785=CARTESIAN_POINT('',(-13.8722744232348,-33.490633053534,9.74999999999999));
#3786=DIRECTION('',(0.,0.,1.));
#3787=DIRECTION('',(-0.923879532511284,0.382683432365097,0.));
#3788=AXIS2_PLACEMENT_3D('',#3785,#3786,#3787);
#3789=CYLINDRICAL_SURFACE('',#3788,4.25000000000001);
#3790=ORIENTED_EDGE('',*,*,#3779,.F.);
#3791=ORIENTED_EDGE('',*,*,#978,.T.);
#3792=CARTESIAN_POINT('',(-13.8722744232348,-33.490633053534,-9.75000000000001));
#3793=DIRECTION('',(0.,0.,1.));
#3794=DIRECTION('',(-0.923879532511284,0.382683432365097,0.));
#3795=AXIS2_PLACEMENT_3D('',#3792,#3793,#3794);
#3796=CIRCLE('',#3795,4.25000000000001);
#3797=EDGE_CURVE('E1074',#971,#2142,#3796,.T.);
#3798=ORIENTED_EDGE('',*,*,#3797,.T.);
#3799=ORIENTED_EDGE('',*,*,#2143,.T.);
#3800=EDGE_LOOP('',(#3790,#3791,#3798,#3799));
#3801=FACE_BOUND('',#3800,.T.);
#3802=ADVANCED_FACE('F2177',(#3801),#3789,.T.);
#3803=EDGE_CURVE('E1070',#2151,#962,#3796,.T.);
#3804=ORIENTED_EDGE('',*,*,#3803,.T.);
#3805=ORIENTED_EDGE('',*,*,#963,.T.);
#3806=ORIENTED_EDGE('',*,*,#3776,.F.);
#3807=ORIENTED_EDGE('',*,*,#2158,.T.);
#3808=EDGE_LOOP('',(#3804,#3805,#3806,#3807));
#3809=FACE_BOUND('',#3808,.T.);
#3810=ADVANCED_FACE('F2178',(#3809),#3789,.T.);
#3811=CARTESIAN_POINT('',(-15.4986790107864,-37.417121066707,-9.75000000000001));
#3812=DIRECTION('',(0.,0.,1.));
#3813=DIRECTION('',(-0.923879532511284,0.382683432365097,0.));
#3814=AXIS2_PLACEMENT_3D('',#3811,#3812,#3813);
#3815=PLANE('',#3814);
#3816=ORIENTED_EDGE('',*,*,#3797,.F.);
#3817=ORIENTED_EDGE('',*,*,#972,.T.);
#3818=ORIENTED_EDGE('',*,*,#3803,.F.);
#3819=ORIENTED_EDGE('',*,*,#2152,.T.);
#3820=EDGE_LOOP('',(#3816,#3817,#3818,#3819));
#3821=FACE_BOUND('',#3820,.T.);
#3822=ADVANCED_FACE('F2171',(#3821),#3815,.F.);
#3823=CARTESIAN_POINT('',(-28.6378246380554,-28.6378246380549,9.74999999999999));
#3824=DIRECTION('',(0.,0.,-1.));
#3825=DIRECTION('',(0.707106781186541,-0.707106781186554,0.));
#3826=AXIS2_PLACEMENT_3D('',#3823,#3824,#3825);
#3827=PLANE('',#3826);
#3828=CARTESIAN_POINT('',(-25.6326208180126,-25.6326208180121,9.74999999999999));
#3829=DIRECTION('',(0.,0.,1.));
#3830=DIRECTION('',(-0.707106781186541,0.707106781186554,0.));
#3831=AXIS2_PLACEMENT_3D('',#3828,#3829,#3830);
#3832=CIRCLE('',#3831,4.25000000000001);
#3833=EDGE_CURVE('E1050',#1408,#220,#3832,.T.);
#3834=ORIENTED_EDGE('',*,*,#3833,.T.);
#3835=ORIENTED_EDGE('',*,*,#221,.T.);
#3836=EDGE_CURVE('E1053',#209,#1391,#3832,.T.);
#3837=ORIENTED_EDGE('',*,*,#3836,.T.);
#3838=ORIENTED_EDGE('',*,*,#1416,.T.);
#3839=EDGE_LOOP('',(#3834,#3835,#3837,#3838));
#3840=FACE_BOUND('',#3839,.T.);
#3841=ADVANCED_FACE('F2170',(#3840),#3827,.F.);
#3842=CARTESIAN_POINT('',(-28.6378246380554,-28.6378246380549,1.29999999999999));
#3843=DIRECTION('',(0.,0.,1.));
#3844=DIRECTION('',(-0.707106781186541,0.707106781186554,0.));
#3845=AXIS2_PLACEMENT_3D('',#3842,#3843,#3844);
#3846=PLANE('',#3845);
#3847=CARTESIAN_POINT('',(-25.6326208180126,-25.6326208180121,1.29999999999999));
#3848=DIRECTION('',(0.,0.,1.));
#3849=DIRECTION('',(-0.707106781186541,0.707106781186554,0.));
#3850=AXIS2_PLACEMENT_3D('',#3847,#3848,#3849);
#3851=CIRCLE('',#3850,4.25);
#3852=EDGE_CURVE('E1051',#211,#1389,#3851,.T.);
#3853=ORIENTED_EDGE('',*,*,#3852,.F.);
#3854=ORIENTED_EDGE('',*,*,#236,.T.);
#3855=EDGE_CURVE('E1054',#1400,#228,#3851,.T.);
#3856=ORIENTED_EDGE('',*,*,#3855,.F.);
#3857=ORIENTED_EDGE('',*,*,#1401,.T.);
#3858=EDGE_LOOP('',(#3853,#3854,#3856,#3857));
#3859=FACE_BOUND('',#3858,.T.);
#3860=ADVANCED_FACE('F2161',(#3859),#3846,.F.);
#3861=CARTESIAN_POINT('',(-25.6326208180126,-25.6326208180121,9.74999999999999));
#3862=DIRECTION('',(0.,0.,1.));
#3863=DIRECTION('',(-0.707106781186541,0.707106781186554,0.));
#3864=AXIS2_PLACEMENT_3D('',#3861,#3862,#3863);
#3865=CYLINDRICAL_SURFACE('',#3864,4.25000000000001);
#3866=ORIENTED_EDGE('',*,*,#3836,.F.);
#3867=ORIENTED_EDGE('',*,*,#212,.T.);
#3868=ORIENTED_EDGE('',*,*,#3852,.T.);
#3869=ORIENTED_EDGE('',*,*,#1392,.T.);
#3870=EDGE_LOOP('',(#3866,#3867,#3868,#3869));
#3871=FACE_BOUND('',#3870,.T.);
#3872=ADVANCED_FACE('F2162',(#3871),#3865,.T.);
#3873=ORIENTED_EDGE('',*,*,#3855,.T.);
#3874=ORIENTED_EDGE('',*,*,#229,.T.);
#3875=ORIENTED_EDGE('',*,*,#3833,.F.);
#3876=ORIENTED_EDGE('',*,*,#1409,.T.);
#3877=EDGE_LOOP('',(#3873,#3874,#3875,#3876));
#3878=FACE_BOUND('',#3877,.T.);
#3879=ADVANCED_FACE('F2156',(#3878),#3865,.T.);
#3880=CARTESIAN_POINT('',(-28.6378246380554,-28.6378246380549,-1.30000000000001));
#3881=DIRECTION('',(0.,0.,-1.));
#3882=DIRECTION('',(0.707106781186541,-0.707106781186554,0.));
#3883=AXIS2_PLACEMENT_3D('',#3880,#3881,#3882);
#3884=PLANE('',#3883);
#3885=CARTESIAN_POINT('',(-25.6326208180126,-25.6326208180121,-1.30000000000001));
#3886=DIRECTION('',(0.,0.,1.));
#3887=DIRECTION('',(-0.707106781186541,0.707106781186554,0.));
#3888=AXIS2_PLACEMENT_3D('',#3885,#3886,#3887);
#3889=CIRCLE('',#3888,4.25);
#3890=EDGE_CURVE('E1035',#2170,#988,#3889,.T.);
#3891=ORIENTED_EDGE('',*,*,#3890,.T.);
#3892=ORIENTED_EDGE('',*,*,#991,.T.);
#3893=EDGE_CURVE('E1033',#990,#2168,#3889,.T.);
#3894=ORIENTED_EDGE('',*,*,#3893,.T.);
#3895=ORIENTED_EDGE('',*,*,#2171,.T.);
#3896=EDGE_LOOP('',(#3891,#3892,#3894,#3895));
#3897=FACE_BOUND('',#3896,.T.);
#3898=ADVANCED_FACE('F2154',(#3897),#3884,.F.);
#3899=CARTESIAN_POINT('',(-25.6326208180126,-25.6326208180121,9.74999999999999));
#3900=DIRECTION('',(0.,0.,1.));
#3901=DIRECTION('',(-0.707106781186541,0.707106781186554,0.));
#3902=AXIS2_PLACEMENT_3D('',#3899,#3900,#3901);
#3903=CYLINDRICAL_SURFACE('',#3902,4.25000000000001);
#3904=ORIENTED_EDGE('',*,*,#3893,.F.);
#3905=ORIENTED_EDGE('',*,*,#1014,.T.);
#3906=CARTESIAN_POINT('',(-25.6326208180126,-25.6326208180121,-9.75000000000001));
#3907=DIRECTION('',(0.,0.,1.));
#3908=DIRECTION('',(-0.707106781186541,0.707106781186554,0.));
#3909=AXIS2_PLACEMENT_3D('',#3906,#3907,#3908);
#3910=CIRCLE('',#3909,4.25000000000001);
#3911=EDGE_CURVE('E1032',#1007,#2178,#3910,.T.);
#3912=ORIENTED_EDGE('',*,*,#3911,.T.);
#3913=ORIENTED_EDGE('',*,*,#2179,.T.);
#3914=EDGE_LOOP('',(#3904,#3905,#3912,#3913));
#3915=FACE_BOUND('',#3914,.T.);
#3916=ADVANCED_FACE('F2155',(#3915),#3903,.T.);
#3917=EDGE_CURVE('E1027',#2187,#998,#3910,.T.);
#3918=ORIENTED_EDGE('',*,*,#3917,.T.);
#3919=ORIENTED_EDGE('',*,*,#999,.T.);
#3920=ORIENTED_EDGE('',*,*,#3890,.F.);
#3921=ORIENTED_EDGE('',*,*,#2194,.T.);
#3922=EDGE_LOOP('',(#3918,#3919,#3920,#3921));
#3923=FACE_BOUND('',#3922,.T.);
#3924=ADVANCED_FACE('F2149',(#3923),#3903,.T.);
#3925=CARTESIAN_POINT('',(-28.6378246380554,-28.6378246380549,-9.75000000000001));
#3926=DIRECTION('',(0.,0.,1.));
#3927=DIRECTION('',(-0.707106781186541,0.707106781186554,0.));
#3928=AXIS2_PLACEMENT_3D('',#3925,#3926,#3927);
#3929=PLANE('',#3928);
#3930=ORIENTED_EDGE('',*,*,#3911,.F.);
#3931=ORIENTED_EDGE('',*,*,#1008,.T.);
#3932=ORIENTED_EDGE('',*,*,#3917,.F.);
#3933=ORIENTED_EDGE('',*,*,#2188,.T.);
#3934=EDGE_LOOP('',(#3930,#3931,#3932,#3933));
#3935=FACE_BOUND('',#3934,.T.);
#3936=ADVANCED_FACE('F2146',(#3935),#3929,.F.);
#3937=CARTESIAN_POINT('',(-37.4171210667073,-15.4986790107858,9.74999999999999));
#3938=DIRECTION('',(0.,0.,-1.));
#3939=DIRECTION('',(0.382683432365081,-0.923879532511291,0.));
#3940=AXIS2_PLACEMENT_3D('',#3937,#3938,#3939);
#3941=PLANE('',#3940);
#3942=CARTESIAN_POINT('',(-33.4906330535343,-13.8722744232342,9.74999999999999));
#3943=DIRECTION('',(0.,0.,1.));
#3944=DIRECTION('',(-0.382683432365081,0.923879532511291,0.));
#3945=AXIS2_PLACEMENT_3D('',#3942,#3943,#3944);
#3946=CIRCLE('',#3945,4.25000000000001);
#3947=EDGE_CURVE('E1006',#1372,#184,#3946,.T.);
#3948=ORIENTED_EDGE('',*,*,#3947,.T.);
#3949=ORIENTED_EDGE('',*,*,#185,.T.);
#3950=EDGE_CURVE('E1013',#173,#1355,#3946,.T.);
#3951=ORIENTED_EDGE('',*,*,#3950,.T.);
#3952=ORIENTED_EDGE('',*,*,#1380,.T.);
#3953=EDGE_LOOP('',(#3948,#3949,#3951,#3952));
#3954=FACE_BOUND('',#3953,.T.);
#3955=ADVANCED_FACE('F2145',(#3954),#3941,.F.);
#3956=CARTESIAN_POINT('',(-37.4171210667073,-15.4986790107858,1.29999999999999));
#3957=DIRECTION('',(0.,0.,1.));
#3958=DIRECTION('',(-0.382683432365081,0.923879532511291,0.));
#3959=AXIS2_PLACEMENT_3D('',#3956,#3957,#3958);
#3960=PLANE('',#3959);
#3961=CARTESIAN_POINT('',(-33.4906330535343,-13.8722744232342,1.29999999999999));
#3962=DIRECTION('',(0.,0.,1.));
#3963=DIRECTION('',(-0.382683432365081,0.923879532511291,0.));
#3964=AXIS2_PLACEMENT_3D('',#3961,#3962,#3963);
#3965=CIRCLE('',#3964,4.25);
#3966=EDGE_CURVE('E1012',#175,#1353,#3965,.T.);
#3967=ORIENTED_EDGE('',*,*,#3966,.F.);
#3968=ORIENTED_EDGE('',*,*,#200,.T.);
#3969=EDGE_CURVE('E1015',#1364,#192,#3965,.T.);
#3970=ORIENTED_EDGE('',*,*,#3969,.F.);
#3971=ORIENTED_EDGE('',*,*,#1365,.T.);
#3972=EDGE_LOOP('',(#3967,#3968,#3970,#3971));
#3973=FACE_BOUND('',#3972,.T.);
#3974=ADVANCED_FACE('F2136',(#3973),#3960,.F.);
#3975=CARTESIAN_POINT('',(-33.4906330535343,-13.8722744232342,9.74999999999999));
#3976=DIRECTION('',(0.,0.,1.));
#3977=DIRECTION('',(-0.382683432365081,0.923879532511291,0.));
#3978=AXIS2_PLACEMENT_3D('',#3975,#3976,#3977);
#3979=CYLINDRICAL_SURFACE('',#3978,4.25000000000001);
#3980=ORIENTED_EDGE('',*,*,#3950,.F.);
#3981=ORIENTED_EDGE('',*,*,#176,.T.);
#3982=ORIENTED_EDGE('',*,*,#3966,.T.);
#3983=ORIENTED_EDGE('',*,*,#1356,.T.);
#3984=EDGE_LOOP('',(#3980,#3981,#3982,#3983));
#3985=FACE_BOUND('',#3984,.T.);
#3986=ADVANCED_FACE('F2134',(#3985),#3979,.T.);
#3987=ORIENTED_EDGE('',*,*,#3969,.T.);
#3988=ORIENTED_EDGE('',*,*,#193,.T.);
#3989=ORIENTED_EDGE('',*,*,#3947,.F.);
#3990=ORIENTED_EDGE('',*,*,#1373,.T.);
#3991=EDGE_LOOP('',(#3987,#3988,#3989,#3990));
#3992=FACE_BOUND('',#3991,.T.);
#3993=ADVANCED_FACE('F2131',(#3992),#3979,.T.);
#3994=CARTESIAN_POINT('',(-37.4171210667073,-15.4986790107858,-1.30000000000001));
#3995=DIRECTION('',(0.,0.,-1.));
#3996=DIRECTION('',(0.382683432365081,-0.923879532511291,0.));
#3997=AXIS2_PLACEMENT_3D('',#3994,#3995,#3996);
#3998=PLANE('',#3997);
#3999=CARTESIAN_POINT('',(-33.4906330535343,-13.8722744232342,-1.30000000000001));
#4000=DIRECTION('',(0.,0.,1.));
#4001=DIRECTION('',(-0.382683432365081,0.923879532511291,0.));
#4002=AXIS2_PLACEMENT_3D('',#3999,#4000,#4001);
#4003=CIRCLE('',#4002,4.25);
#4004=EDGE_CURVE('E991',#2206,#1024,#4003,.T.);
#4005=ORIENTED_EDGE('',*,*,#4004,.T.);
#4006=ORIENTED_EDGE('',*,*,#1027,.T.);
#4007=EDGE_CURVE('E992',#1026,#2204,#4003,.T.);
#4008=ORIENTED_EDGE('',*,*,#4007,.T.);
#4009=ORIENTED_EDGE('',*,*,#2207,.T.);
#4010=EDGE_LOOP('',(#4005,#4006,#4008,#4009));
#4011=FACE_BOUND('',#4010,.T.);
#4012=ADVANCED_FACE('F2130',(#4011),#3998,.F.);
#4013=CARTESIAN_POINT('',(-33.4906330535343,-13.8722744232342,9.74999999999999));
#4014=DIRECTION('',(0.,0.,1.));
#4015=DIRECTION('',(-0.382683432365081,0.923879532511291,0.));
#4016=AXIS2_PLACEMENT_3D('',#4013,#4014,#4015);
#4017=CYLINDRICAL_SURFACE('',#4016,4.25000000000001);
#4018=ORIENTED_EDGE('',*,*,#4007,.F.);
#4019=ORIENTED_EDGE('',*,*,#1050,.T.);
#4020=CARTESIAN_POINT('',(-33.4906330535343,-13.8722744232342,-9.75000000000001));
#4021=DIRECTION('',(0.,0.,1.));
#4022=DIRECTION('',(-0.382683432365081,0.923879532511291,0.));
#4023=AXIS2_PLACEMENT_3D('',#4020,#4021,#4022);
#4024=CIRCLE('',#4023,4.25000000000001);
#4025=EDGE_CURVE('E994',#1043,#2214,#4024,.T.);
#4026=ORIENTED_EDGE('',*,*,#4025,.T.);
#4027=ORIENTED_EDGE('',*,*,#2215,.T.);
#4028=EDGE_LOOP('',(#4018,#4019,#4026,#4027));
#4029=FACE_BOUND('',#4028,.T.);
#4030=ADVANCED_FACE('F2128',(#4029),#4017,.T.);
#4031=EDGE_CURVE('E989',#2223,#1034,#4024,.T.);
#4032=ORIENTED_EDGE('',*,*,#4031,.T.);
#4033=ORIENTED_EDGE('',*,*,#1035,.T.);
#4034=ORIENTED_EDGE('',*,*,#4004,.F.);
#4035=ORIENTED_EDGE('',*,*,#2230,.T.);
#4036=EDGE_LOOP('',(#4032,#4033,#4034,#4035));
#4037=FACE_BOUND('',#4036,.T.);
#4038=ADVANCED_FACE('F2123',(#4037),#4017,.T.);
#4039=CARTESIAN_POINT('',(-37.4171210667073,-15.4986790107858,-9.75000000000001));
#4040=DIRECTION('',(0.,0.,1.));
#4041=DIRECTION('',(-0.382683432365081,0.923879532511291,0.));
#4042=AXIS2_PLACEMENT_3D('',#4039,#4040,#4041);
#4043=PLANE('',#4042);
#4044=ORIENTED_EDGE('',*,*,#4025,.F.);
#4045=ORIENTED_EDGE('',*,*,#1044,.T.);
#4046=ORIENTED_EDGE('',*,*,#4031,.F.);
#4047=ORIENTED_EDGE('',*,*,#2224,.T.);
#4048=EDGE_LOOP('',(#4044,#4045,#4046,#4047));
#4049=FACE_BOUND('',#4048,.T.);
#4050=ADVANCED_FACE('F2117',(#4049),#4043,.F.);
#4051=CARTESIAN_POINT('',(-40.5,4.24214982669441E-13,9.74999999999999));
#4052=DIRECTION('',(0.,0.,-1.));
#4053=DIRECTION('',(0.,-1.,0.));
#4054=AXIS2_PLACEMENT_3D('',#4051,#4052,#4053);
#4055=PLANE('',#4054);
#4056=CARTESIAN_POINT('',(-36.25,3.79698595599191E-13,9.74999999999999));
#4057=DIRECTION('',(0.,0.,1.));
#4058=DIRECTION('',(0.,1.,0.));
#4059=AXIS2_PLACEMENT_3D('',#4056,#4057,#4058);
#4060=CIRCLE('',#4059,4.25000000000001);
#4061=EDGE_CURVE('E970',#1336,#148,#4060,.T.);
#4062=ORIENTED_EDGE('',*,*,#4061,.T.);
#4063=ORIENTED_EDGE('',*,*,#149,.T.);
#4064=EDGE_CURVE('E974',#137,#1319,#4060,.T.);
#4065=ORIENTED_EDGE('',*,*,#4064,.T.);
#4066=ORIENTED_EDGE('',*,*,#1344,.T.);
#4067=EDGE_LOOP('',(#4062,#4063,#4065,#4066));
#4068=FACE_BOUND('',#4067,.T.);
#4069=ADVANCED_FACE('F2119',(#4068),#4055,.F.);
#4070=CARTESIAN_POINT('',(-40.5,4.24214982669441E-13,1.29999999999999));
#4071=DIRECTION('',(0.,0.,1.));
#4072=DIRECTION('',(0.,1.,0.));
#4073=AXIS2_PLACEMENT_3D('',#4070,#4071,#4072);
#4074=PLANE('',#4073);
#4075=CARTESIAN_POINT('',(-36.25,3.79698595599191E-13,1.29999999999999));
#4076=DIRECTION('',(0.,0.,1.));
#4077=DIRECTION('',(0.,1.,0.));
#4078=AXIS2_PLACEMENT_3D('',#4075,#4076,#4077);
#4079=CIRCLE('',#4078,4.25);
#4080=EDGE_CURVE('E972',#139,#1317,#4079,.T.);
#4081=ORIENTED_EDGE('',*,*,#4080,.F.);
#4082=ORIENTED_EDGE('',*,*,#164,.T.);
#4083=EDGE_CURVE('E971',#1328,#156,#4079,.T.);
#4084=ORIENTED_EDGE('',*,*,#4083,.F.);
#4085=ORIENTED_EDGE('',*,*,#1329,.T.);
#4086=EDGE_LOOP('',(#4081,#4082,#4084,#4085));
#4087=FACE_BOUND('',#4086,.T.);
#4088=ADVANCED_FACE('F2115',(#4087),#4074,.F.);
#4089=CARTESIAN_POINT('',(-36.25,3.79698595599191E-13,9.74999999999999));
#4090=DIRECTION('',(0.,0.,1.));
#4091=DIRECTION('',(0.,1.,0.));
#4092=AXIS2_PLACEMENT_3D('',#4089,#4090,#4091);
#4093=CYLINDRICAL_SURFACE('',#4092,4.25000000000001);
#4094=ORIENTED_EDGE('',*,*,#4064,.F.);
#4095=ORIENTED_EDGE('',*,*,#140,.T.);
#4096=ORIENTED_EDGE('',*,*,#4080,.T.);
#4097=ORIENTED_EDGE('',*,*,#1320,.T.);
#4098=EDGE_LOOP('',(#4094,#4095,#4096,#4097));
#4099=FACE_BOUND('',#4098,.T.);
#4100=ADVANCED_FACE('F2109',(#4099),#4093,.T.);
#4101=ORIENTED_EDGE('',*,*,#4083,.T.);
#4102=ORIENTED_EDGE('',*,*,#157,.T.);
#4103=ORIENTED_EDGE('',*,*,#4061,.F.);
#4104=ORIENTED_EDGE('',*,*,#1337,.T.);
#4105=EDGE_LOOP('',(#4101,#4102,#4103,#4104));
#4106=FACE_BOUND('',#4105,.T.);
#4107=ADVANCED_FACE('F2110',(#4106),#4093,.T.);
#4108=CARTESIAN_POINT('',(-40.5,4.24214982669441E-13,-1.30000000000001));
#4109=DIRECTION('',(0.,0.,-1.));
#4110=DIRECTION('',(0.,-1.,0.));
#4111=AXIS2_PLACEMENT_3D('',#4108,#4109,#4110);
#4112=PLANE('',#4111);
#4113=CARTESIAN_POINT('',(-36.25,3.79698595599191E-13,-1.30000000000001));
#4114=DIRECTION('',(0.,0.,1.));
#4115=DIRECTION('',(0.,1.,0.));
#4116=AXIS2_PLACEMENT_3D('',#4113,#4114,#4115);
#4117=CIRCLE('',#4116,4.25);
#4118=EDGE_CURVE('E955',#2242,#1060,#4117,.T.);
#4119=ORIENTED_EDGE('',*,*,#4118,.T.);
#4120=ORIENTED_EDGE('',*,*,#1063,.T.);
#4121=EDGE_CURVE('E954',#1062,#2240,#4117,.T.);
#4122=ORIENTED_EDGE('',*,*,#4121,.T.);
#4123=ORIENTED_EDGE('',*,*,#2243,.T.);
#4124=EDGE_LOOP('',(#4119,#4120,#4122,#4123));
#4125=FACE_BOUND('',#4124,.T.);
#4126=ADVANCED_FACE('F2102',(#4125),#4112,.F.);
#4127=CARTESIAN_POINT('',(-36.25,3.79698595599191E-13,9.74999999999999));
#4128=DIRECTION('',(0.,0.,1.));
#4129=DIRECTION('',(0.,1.,0.));
#4130=AXIS2_PLACEMENT_3D('',#4127,#4128,#4129);
#4131=CYLINDRICAL_SURFACE('',#4130,4.25000000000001);
#4132=ORIENTED_EDGE('',*,*,#4121,.F.);
#4133=ORIENTED_EDGE('',*,*,#1086,.T.);
#4134=CARTESIAN_POINT('',(-36.25,3.79698595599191E-13,-9.75000000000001));
#4135=DIRECTION('',(0.,0.,1.));
#4136=DIRECTION('',(0.,1.,0.));
#4137=AXIS2_PLACEMENT_3D('',#4134,#4135,#4136);
#4138=CIRCLE('',#4137,4.25000000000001);
#4139=EDGE_CURVE('E951',#1079,#2250,#4138,.T.);
#4140=ORIENTED_EDGE('',*,*,#4139,.T.);
#4141=ORIENTED_EDGE('',*,*,#2251,.T.);
#4142=EDGE_LOOP('',(#4132,#4133,#4140,#4141));
#4143=FACE_BOUND('',#4142,.T.);
#4144=ADVANCED_FACE('F2097',(#4143),#4131,.T.);
#4145=EDGE_CURVE('E948',#2259,#1070,#4138,.T.);
#4146=ORIENTED_EDGE('',*,*,#4145,.T.);
#4147=ORIENTED_EDGE('',*,*,#1071,.T.);
#4148=ORIENTED_EDGE('',*,*,#4118,.F.);
#4149=ORIENTED_EDGE('',*,*,#2266,.T.);
#4150=EDGE_LOOP('',(#4146,#4147,#4148,#4149));
#4151=FACE_BOUND('',#4150,.T.);
#4152=ADVANCED_FACE('F2100',(#4151),#4131,.T.);
#4153=CARTESIAN_POINT('',(-40.5,4.24214982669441E-13,-9.75000000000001));
#4154=DIRECTION('',(0.,0.,1.));
#4155=DIRECTION('',(0.,1.,0.));
#4156=AXIS2_PLACEMENT_3D('',#4153,#4154,#4155);
#4157=PLANE('',#4156);
#4158=ORIENTED_EDGE('',*,*,#4139,.F.);
#4159=ORIENTED_EDGE('',*,*,#1080,.T.);
#4160=ORIENTED_EDGE('',*,*,#4145,.F.);
#4161=ORIENTED_EDGE('',*,*,#2260,.T.);
#4162=EDGE_LOOP('',(#4158,#4159,#4160,#4161));
#4163=FACE_BOUND('',#4162,.T.);
#4164=ADVANCED_FACE('F2093',(#4163),#4157,.F.);
#4165=CARTESIAN_POINT('',(-37.417121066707,15.4986790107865,9.74999999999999));
#4166=DIRECTION('',(0.,0.,-1.));
#4167=DIRECTION('',(-0.3826834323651,-0.923879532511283,0.));
#4168=AXIS2_PLACEMENT_3D('',#4165,#4166,#4167);
#4169=PLANE('',#4168);
#4170=CARTESIAN_POINT('',(-33.490633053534,13.8722744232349,9.74999999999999));
#4171=DIRECTION('',(0.,0.,1.));
#4172=DIRECTION('',(0.3826834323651,0.923879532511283,0.));
#4173=AXIS2_PLACEMENT_3D('',#4170,#4171,#4172);
#4174=CIRCLE('',#4173,4.25000000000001);
#4175=EDGE_CURVE('E927',#1300,#112,#4174,.T.);
#4176=ORIENTED_EDGE('',*,*,#4175,.T.);
#4177=ORIENTED_EDGE('',*,*,#113,.T.);
#4178=EDGE_CURVE('E933',#101,#1283,#4174,.T.);
#4179=ORIENTED_EDGE('',*,*,#4178,.T.);
#4180=ORIENTED_EDGE('',*,*,#1308,.T.);
#4181=EDGE_LOOP('',(#4176,#4177,#4179,#4180));
#4182=FACE_BOUND('',#4181,.T.);
#4183=ADVANCED_FACE('F2088',(#4182),#4169,.F.);
#4184=CARTESIAN_POINT('',(-37.4171210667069,15.4986790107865,1.29999999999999));
#4185=DIRECTION('',(0.,0.,1.));
#4186=DIRECTION('',(0.3826834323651,0.923879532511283,0.));
#4187=AXIS2_PLACEMENT_3D('',#4184,#4185,#4186);
#4188=PLANE('',#4187);
#4189=CARTESIAN_POINT('',(-33.490633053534,13.8722744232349,1.29999999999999));
#4190=DIRECTION('',(0.,0.,1.));
#4191=DIRECTION('',(0.3826834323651,0.923879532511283,0.));
#4192=AXIS2_PLACEMENT_3D('',#4189,#4190,#4191);
#4193=CIRCLE('',#4192,4.25);
#4194=EDGE_CURVE('E934',#103,#1281,#4193,.T.);
#4195=ORIENTED_EDGE('',*,*,#4194,.F.);
#4196=ORIENTED_EDGE('',*,*,#128,.T.);
#4197=EDGE_CURVE('E932',#1292,#120,#4193,.T.);
#4198=ORIENTED_EDGE('',*,*,#4197,.F.);
#4199=ORIENTED_EDGE('',*,*,#1293,.T.);
#4200=EDGE_LOOP('',(#4195,#4196,#4198,#4199));
#4201=FACE_BOUND('',#4200,.T.);
#4202=ADVANCED_FACE('F2087',(#4201),#4188,.F.);
#4203=CARTESIAN_POINT('',(-33.490633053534,13.8722744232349,9.74999999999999));
#4204=DIRECTION('',(0.,0.,1.));
#4205=DIRECTION('',(0.3826834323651,0.923879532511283,0.));
#4206=AXIS2_PLACEMENT_3D('',#4203,#4204,#4205);
#4207=CYLINDRICAL_SURFACE('',#4206,4.25000000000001);
#4208=ORIENTED_EDGE('',*,*,#4178,.F.);
#4209=ORIENTED_EDGE('',*,*,#104,.T.);
#4210=ORIENTED_EDGE('',*,*,#4194,.T.);
#4211=ORIENTED_EDGE('',*,*,#1284,.T.);
#4212=EDGE_LOOP('',(#4208,#4209,#4210,#4211));
#4213=FACE_BOUND('',#4212,.T.);
#4214=ADVANCED_FACE('F2084',(#4213),#4207,.T.);
#4215=ORIENTED_EDGE('',*,*,#4197,.T.);
#4216=ORIENTED_EDGE('',*,*,#121,.T.);
#4217=ORIENTED_EDGE('',*,*,#4175,.F.);
#4218=ORIENTED_EDGE('',*,*,#1301,.T.);
#4219=EDGE_LOOP('',(#4215,#4216,#4217,#4218));
#4220=FACE_BOUND('',#4219,.T.);
#4221=ADVANCED_FACE('F2082',(#4220),#4207,.T.);
#4222=CARTESIAN_POINT('',(-37.4171210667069,15.4986790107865,-1.30000000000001));
#4223=DIRECTION('',(0.,0.,-1.));
#4224=DIRECTION('',(-0.3826834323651,-0.923879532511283,0.));
#4225=AXIS2_PLACEMENT_3D('',#4222,#4223,#4224);
#4226=PLANE('',#4225);
#4227=CARTESIAN_POINT('',(-33.490633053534,13.8722744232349,-1.30000000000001));
#4228=DIRECTION('',(0.,0.,1.));
#4229=DIRECTION('',(0.3826834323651,0.923879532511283,0.));
#4230=AXIS2_PLACEMENT_3D('',#4227,#4228,#4229);
#4231=CIRCLE('',#4230,4.25);
#4232=EDGE_CURVE('E915',#2278,#1096,#4231,.T.);
#4233=ORIENTED_EDGE('',*,*,#4232,.T.);
#4234=ORIENTED_EDGE('',*,*,#1099,.T.);
#4235=EDGE_CURVE('E913',#1098,#2276,#4231,.T.);
#4236=ORIENTED_EDGE('',*,*,#4235,.T.);
#4237=ORIENTED_EDGE('',*,*,#2279,.T.);
#4238=EDGE_LOOP('',(#4233,#4234,#4236,#4237));
#4239=FACE_BOUND('',#4238,.T.);
#4240=ADVANCED_FACE('F2080',(#4239),#4226,.F.);
#4241=CARTESIAN_POINT('',(-33.490633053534,13.8722744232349,9.74999999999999));
#4242=DIRECTION('',(0.,0.,1.));
#4243=DIRECTION('',(0.3826834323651,0.923879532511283,0.));
#4244=AXIS2_PLACEMENT_3D('',#4241,#4242,#4243);
#4245=CYLINDRICAL_SURFACE('',#4244,4.25000000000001);
#4246=ORIENTED_EDGE('',*,*,#4235,.F.);
#4247=ORIENTED_EDGE('',*,*,#1122,.T.);
#4248=CARTESIAN_POINT('',(-33.490633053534,13.8722744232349,-9.75000000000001));
#4249=DIRECTION('',(0.,0.,1.));
#4250=DIRECTION('',(0.3826834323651,0.923879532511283,0.));
#4251=AXIS2_PLACEMENT_3D('',#4248,#4249,#4250);
#4252=CIRCLE('',#4251,4.25000000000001);
#4253=EDGE_CURVE('E912',#1115,#2286,#4252,.T.);
#4254=ORIENTED_EDGE('',*,*,#4253,.T.);
#4255=ORIENTED_EDGE('',*,*,#2287,.T.);
#4256=EDGE_LOOP('',(#4246,#4247,#4254,#4255));
#4257=FACE_BOUND('',#4256,.T.);
#4258=ADVANCED_FACE('F2072',(#4257),#4245,.T.);
#4259=EDGE_CURVE('E906',#2295,#1106,#4252,.T.);
#4260=ORIENTED_EDGE('',*,*,#4259,.T.);
#4261=ORIENTED_EDGE('',*,*,#1107,.T.);
#4262=ORIENTED_EDGE('',*,*,#4232,.F.);
#4263=ORIENTED_EDGE('',*,*,#2302,.T.);
#4264=EDGE_LOOP('',(#4260,#4261,#4262,#4263));
#4265=FACE_BOUND('',#4264,.T.);
#4266=ADVANCED_FACE('F2075',(#4265),#4245,.T.);
#4267=CARTESIAN_POINT('',(-37.417121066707,15.4986790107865,-9.75000000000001));
#4268=DIRECTION('',(0.,0.,1.));
#4269=DIRECTION('',(0.3826834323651,0.923879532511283,0.));
#4270=AXIS2_PLACEMENT_3D('',#4267,#4268,#4269);
#4271=PLANE('',#4270);
#4272=ORIENTED_EDGE('',*,*,#4253,.F.);
#4273=ORIENTED_EDGE('',*,*,#1116,.T.);
#4274=ORIENTED_EDGE('',*,*,#4259,.F.);
#4275=ORIENTED_EDGE('',*,*,#2296,.T.);
#4276=EDGE_LOOP('',(#4272,#4273,#4274,#4275));
#4277=FACE_BOUND('',#4276,.T.);
#4278=ADVANCED_FACE('F2067',(#4277),#4271,.F.);
#4279=CARTESIAN_POINT('',(-28.6378246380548,28.6378246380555,9.74999999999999));
#4280=DIRECTION('',(0.,0.,-1.));
#4281=DIRECTION('',(-0.707106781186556,-0.707106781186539,0.));
#4282=AXIS2_PLACEMENT_3D('',#4279,#4280,#4281);
#4283=PLANE('',#4282);
#4284=CARTESIAN_POINT('',(-25.632620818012,25.6326208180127,9.74999999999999));
#4285=DIRECTION('',(0.,0.,1.));
#4286=DIRECTION('',(0.707106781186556,0.707106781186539,0.));
#4287=AXIS2_PLACEMENT_3D('',#4284,#4285,#4286);
#4288=CIRCLE('',#4287,4.25000000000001);
#4289=EDGE_CURVE('E889',#1264,#76,#4288,.T.);
#4290=ORIENTED_EDGE('',*,*,#4289,.T.);
#4291=ORIENTED_EDGE('',*,*,#77,.T.);
#4292=EDGE_CURVE('E894',#65,#1247,#4288,.T.);
#4293=ORIENTED_EDGE('',*,*,#4292,.T.);
#4294=ORIENTED_EDGE('',*,*,#1272,.T.);
#4295=EDGE_LOOP('',(#4290,#4291,#4293,#4294));
#4296=FACE_BOUND('',#4295,.T.);
#4297=ADVANCED_FACE('F2062',(#4296),#4283,.F.);
#4298=CARTESIAN_POINT('',(-28.6378246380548,28.6378246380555,1.29999999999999));
#4299=DIRECTION('',(0.,0.,1.));
#4300=DIRECTION('',(0.707106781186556,0.707106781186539,0.));
#4301=AXIS2_PLACEMENT_3D('',#4298,#4299,#4300);
#4302=PLANE('',#4301);
#4303=CARTESIAN_POINT('',(-25.632620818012,25.6326208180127,1.29999999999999));
#4304=DIRECTION('',(0.,0.,1.));
#4305=DIRECTION('',(0.707106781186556,0.707106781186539,0.));
#4306=AXIS2_PLACEMENT_3D('',#4303,#4304,#4305);
#4307=CIRCLE('',#4306,4.25);
#4308=EDGE_CURVE('E892',#67,#1245,#4307,.T.);
#4309=ORIENTED_EDGE('',*,*,#4308,.F.);
#4310=ORIENTED_EDGE('',*,*,#92,.T.);
#4311=EDGE_CURVE('E891',#1256,#84,#4307,.T.);
#4312=ORIENTED_EDGE('',*,*,#4311,.F.);
#4313=ORIENTED_EDGE('',*,*,#1257,.T.);
#4314=EDGE_LOOP('',(#4309,#4310,#4312,#4313));
#4315=FACE_BOUND('',#4314,.T.);
#4316=ADVANCED_FACE('F2063',(#4315),#4302,.F.);
#4317=CARTESIAN_POINT('',(-25.632620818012,25.6326208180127,9.74999999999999));
#4318=DIRECTION('',(0.,0.,1.));
#4319=DIRECTION('',(0.707106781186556,0.707106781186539,0.));
#4320=AXIS2_PLACEMENT_3D('',#4317,#4318,#4319);
#4321=CYLINDRICAL_SURFACE('',#4320,4.25000000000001);
#4322=ORIENTED_EDGE('',*,*,#4292,.F.);
#4323=ORIENTED_EDGE('',*,*,#68,.T.);
#4324=ORIENTED_EDGE('',*,*,#4308,.T.);
#4325=ORIENTED_EDGE('',*,*,#1248,.T.);
#4326=EDGE_LOOP('',(#4322,#4323,#4324,#4325));
#4327=FACE_BOUND('',#4326,.T.);
#4328=ADVANCED_FACE('F2056',(#4327),#4321,.T.);
#4329=ORIENTED_EDGE('',*,*,#4311,.T.);
#4330=ORIENTED_EDGE('',*,*,#85,.T.);
#4331=ORIENTED_EDGE('',*,*,#4289,.F.);
#4332=ORIENTED_EDGE('',*,*,#1265,.T.);
#4333=EDGE_LOOP('',(#4329,#4330,#4331,#4332));
#4334=FACE_BOUND('',#4333,.T.);
#4335=ADVANCED_FACE('F2057',(#4334),#4321,.T.);
#4336=CARTESIAN_POINT('',(-28.6378246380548,28.6378246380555,-1.30000000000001));
#4337=DIRECTION('',(0.,0.,-1.));
#4338=DIRECTION('',(-0.707106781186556,-0.707106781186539,0.));
#4339=AXIS2_PLACEMENT_3D('',#4336,#4337,#4338);
#4340=PLANE('',#4339);
#4341=CARTESIAN_POINT('',(-25.632620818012,25.6326208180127,-1.30000000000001));
#4342=DIRECTION('',(0.,0.,1.));
#4343=DIRECTION('',(0.707106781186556,0.707106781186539,0.));
#4344=AXIS2_PLACEMENT_3D('',#4341,#4342,#4343);
#4345=CIRCLE('',#4344,4.25);
#4346=EDGE_CURVE('E875',#2314,#1132,#4345,.T.);
#4347=ORIENTED_EDGE('',*,*,#4346,.T.);
#4348=ORIENTED_EDGE('',*,*,#1135,.T.);
#4349=EDGE_CURVE('E874',#1134,#2312,#4345,.T.);
#4350=ORIENTED_EDGE('',*,*,#4349,.T.);
#4351=ORIENTED_EDGE('',*,*,#2315,.T.);
#4352=EDGE_LOOP('',(#4347,#4348,#4350,#4351));
#4353=FACE_BOUND('',#4352,.T.);
#4354=ADVANCED_FACE('F2032',(#4353),#4340,.F.);
#4355=CARTESIAN_POINT('',(-25.632620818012,25.6326208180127,9.74999999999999));
#4356=DIRECTION('',(0.,0.,1.));
#4357=DIRECTION('',(0.707106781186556,0.707106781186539,0.));
#4358=AXIS2_PLACEMENT_3D('',#4355,#4356,#4357);
#4359=CYLINDRICAL_SURFACE('',#4358,4.25000000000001);
#4360=ORIENTED_EDGE('',*,*,#4349,.F.);
#4361=ORIENTED_EDGE('',*,*,#1158,.T.);
#4362=CARTESIAN_POINT('',(-25.632620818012,25.6326208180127,-9.75000000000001));
#4363=DIRECTION('',(0.,0.,1.));
#4364=DIRECTION('',(0.707106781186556,0.707106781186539,0.));
#4365=AXIS2_PLACEMENT_3D('',#4362,#4363,#4364);
#4366=CIRCLE('',#4365,4.25000000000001);
#4367=EDGE_CURVE('E871',#1151,#2322,#4366,.T.);
#4368=ORIENTED_EDGE('',*,*,#4367,.T.);
#4369=ORIENTED_EDGE('',*,*,#2323,.T.);
#4370=EDGE_LOOP('',(#4360,#4361,#4368,#4369));
#4371=FACE_BOUND('',#4370,.T.);
#4372=ADVANCED_FACE('F2033',(#4371),#4359,.T.);
#4373=EDGE_CURVE('E868',#2331,#1142,#4366,.T.);
#4374=ORIENTED_EDGE('',*,*,#4373,.T.);
#4375=ORIENTED_EDGE('',*,*,#1143,.T.);
#4376=ORIENTED_EDGE('',*,*,#4346,.F.);
#4377=ORIENTED_EDGE('',*,*,#2338,.T.);
#4378=EDGE_LOOP('',(#4374,#4375,#4376,#4377));
#4379=FACE_BOUND('',#4378,.T.);
#4380=ADVANCED_FACE('F2030',(#4379),#4359,.T.);
#4381=CARTESIAN_POINT('',(-28.6378246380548,28.6378246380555,-9.75000000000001));
#4382=DIRECTION('',(0.,0.,1.));
#4383=DIRECTION('',(0.707106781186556,0.707106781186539,0.));
#4384=AXIS2_PLACEMENT_3D('',#4381,#4382,#4383);
#4385=PLANE('',#4384);
#4386=ORIENTED_EDGE('',*,*,#4367,.F.);
#4387=ORIENTED_EDGE('',*,*,#1152,.T.);
#4388=ORIENTED_EDGE('',*,*,#4373,.F.);
#4389=ORIENTED_EDGE('',*,*,#2332,.T.);
#4390=EDGE_LOOP('',(#4386,#4387,#4388,#4389));
#4391=FACE_BOUND('',#4390,.T.);
#4392=ADVANCED_FACE('F2039',(#4391),#4385,.F.);
#4393=CARTESIAN_POINT('',(-15.4986790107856,37.4171210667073,9.74999999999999));
#4394=DIRECTION('',(0.,0.,-1.));
#4395=DIRECTION('',(-0.923879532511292,-0.382683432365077,0.));
#4396=AXIS2_PLACEMENT_3D('',#4393,#4394,#4395);
#4397=PLANE('',#4396);
#4398=CARTESIAN_POINT('',(-13.8722744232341,33.4906330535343,9.74999999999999));
#4399=DIRECTION('',(0.,0.,1.));
#4400=DIRECTION('',(0.923879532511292,0.382683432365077,0.));
#4401=AXIS2_PLACEMENT_3D('',#4398,#4399,#4400);
#4402=CIRCLE('',#4401,4.25000000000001);
#4403=EDGE_CURVE('E850',#1228,#40,#4402,.T.);
#4404=ORIENTED_EDGE('',*,*,#4403,.T.);
#4405=ORIENTED_EDGE('',*,*,#41,.T.);
#4406=EDGE_CURVE('E853',#29,#1211,#4402,.T.);
#4407=ORIENTED_EDGE('',*,*,#4406,.T.);
#4408=ORIENTED_EDGE('',*,*,#1236,.T.);
#4409=EDGE_LOOP('',(#4404,#4405,#4407,#4408));
#4410=FACE_BOUND('',#4409,.T.);
#4411=ADVANCED_FACE('F2038',(#4410),#4397,.F.);
#4412=CARTESIAN_POINT('',(-15.4986790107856,37.4171210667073,1.29999999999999));
#4413=DIRECTION('',(0.,0.,1.));
#4414=DIRECTION('',(0.923879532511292,0.382683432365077,0.));
#4415=AXIS2_PLACEMENT_3D('',#4412,#4413,#4414);
#4416=PLANE('',#4415);
#4417=CARTESIAN_POINT('',(-13.8722744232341,33.4906330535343,1.29999999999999));
#4418=DIRECTION('',(0.,0.,1.));
#4419=DIRECTION('',(0.923879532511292,0.382683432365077,0.));
#4420=AXIS2_PLACEMENT_3D('',#4417,#4418,#4419);
#4421=CIRCLE('',#4420,4.25);
#4422=EDGE_CURVE('E851',#31,#1209,#4421,.T.);
#4423=ORIENTED_EDGE('',*,*,#4422,.F.);
#4424=ORIENTED_EDGE('',*,*,#56,.T.);
#4425=EDGE_CURVE('E854',#1220,#48,#4421,.T.);
#4426=ORIENTED_EDGE('',*,*,#4425,.F.);
#4427=ORIENTED_EDGE('',*,*,#1221,.T.);
#4428=EDGE_LOOP('',(#4423,#4424,#4426,#4427));
#4429=FACE_BOUND('',#4428,.T.);
#4430=ADVANCED_FACE('F2046',(#4429),#4416,.F.);
#4431=CARTESIAN_POINT('',(-13.8722744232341,33.4906330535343,9.74999999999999));
#4432=DIRECTION('',(0.,0.,1.));
#4433=DIRECTION('',(0.923879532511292,0.382683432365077,0.));
#4434=AXIS2_PLACEMENT_3D('',#4431,#4432,#4433);
#4435=CYLINDRICAL_SURFACE('',#4434,4.25000000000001);
#4436=ORIENTED_EDGE('',*,*,#4406,.F.);
#4437=ORIENTED_EDGE('',*,*,#32,.T.);
#4438=ORIENTED_EDGE('',*,*,#4422,.T.);
#4439=ORIENTED_EDGE('',*,*,#1212,.T.);
#4440=EDGE_LOOP('',(#4436,#4437,#4438,#4439));
#4441=FACE_BOUND('',#4440,.T.);
#4442=ADVANCED_FACE('F2485',(#4441),#4435,.T.);
#4443=ORIENTED_EDGE('',*,*,#4425,.T.);
#4444=ORIENTED_EDGE('',*,*,#49,.T.);
#4445=ORIENTED_EDGE('',*,*,#4403,.F.);
#4446=ORIENTED_EDGE('',*,*,#1229,.T.);
#4447=EDGE_LOOP('',(#4443,#4444,#4445,#4446));
#4448=FACE_BOUND('',#4447,.T.);
#4449=ADVANCED_FACE('F2487',(#4448),#4435,.T.);
#4450=CARTESIAN_POINT('',(-15.4986790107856,37.4171210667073,-1.30000000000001));
#4451=DIRECTION('',(0.,0.,-1.));
#4452=DIRECTION('',(-0.923879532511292,-0.382683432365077,0.));
#4453=AXIS2_PLACEMENT_3D('',#4450,#4451,#4452);
#4454=PLANE('',#4453);
#4455=CARTESIAN_POINT('',(-13.8722744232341,33.4906330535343,-1.30000000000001));
#4456=DIRECTION('',(0.,0.,1.));
#4457=DIRECTION('',(0.923879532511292,0.382683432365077,0.));
#4458=AXIS2_PLACEMENT_3D('',#4455,#4456,#4457);
#4459=CIRCLE('',#4458,4.25);
#4460=EDGE_CURVE('E845',#2350,#1168,#4459,.T.);
#4461=ORIENTED_EDGE('',*,*,#4460,.T.);
#4462=ORIENTED_EDGE('',*,*,#1171,.T.);
#4463=EDGE_CURVE('E840',#1170,#2348,#4459,.T.);
#4464=ORIENTED_EDGE('',*,*,#4463,.T.);
#4465=ORIENTED_EDGE('',*,*,#2351,.T.);
#4466=EDGE_LOOP('',(#4461,#4462,#4464,#4465));
#4467=FACE_BOUND('',#4466,.T.);
#4468=ADVANCED_FACE('F1904',(#4467),#4454,.F.);
#4469=CARTESIAN_POINT('',(-13.8722744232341,33.4906330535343,9.74999999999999));
#4470=DIRECTION('',(0.,0.,1.));
#4471=DIRECTION('',(0.923879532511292,0.382683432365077,0.));
#4472=AXIS2_PLACEMENT_3D('',#4469,#4470,#4471);
#4473=CYLINDRICAL_SURFACE('',#4472,4.25000000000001);
#4474=ORIENTED_EDGE('',*,*,#4463,.F.);
#4475=ORIENTED_EDGE('',*,*,#1194,.T.);
#4476=CARTESIAN_POINT('',(-13.8722744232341,33.4906330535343,-9.75000000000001));
#4477=DIRECTION('',(0.,0.,1.));
#4478=DIRECTION('',(0.923879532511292,0.382683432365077,0.));
#4479=AXIS2_PLACEMENT_3D('',#4476,#4477,#4478);
#4480=CIRCLE('',#4479,4.25000000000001);
#4481=EDGE_CURVE('E837',#1187,#2358,#4480,.T.);
#4482=ORIENTED_EDGE('',*,*,#4481,.T.);
#4483=ORIENTED_EDGE('',*,*,#2359,.T.);
#4484=EDGE_LOOP('',(#4474,#4475,#4482,#4483));
#4485=FACE_BOUND('',#4484,.T.);
#4486=ADVANCED_FACE('F1898',(#4485),#4473,.T.);
#4487=EDGE_CURVE('E834',#2367,#1178,#4480,.T.);
#4488=ORIENTED_EDGE('',*,*,#4487,.T.);
#4489=ORIENTED_EDGE('',*,*,#1179,.T.);
#4490=ORIENTED_EDGE('',*,*,#4460,.F.);
#4491=ORIENTED_EDGE('',*,*,#2374,.T.);
#4492=EDGE_LOOP('',(#4488,#4489,#4490,#4491));
#4493=FACE_BOUND('',#4492,.T.);
#4494=ADVANCED_FACE('F838',(#4493),#4473,.T.);
#4495=CARTESIAN_POINT('',(-15.4986790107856,37.4171210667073,-9.75000000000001));
#4496=DIRECTION('',(0.,0.,1.));
#4497=DIRECTION('',(0.923879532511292,0.382683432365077,0.));
#4498=AXIS2_PLACEMENT_3D('',#4495,#4496,#4497);
#4499=PLANE('',#4498);
#4500=ORIENTED_EDGE('',*,*,#4481,.F.);
#4501=ORIENTED_EDGE('',*,*,#1188,.T.);
#4502=ORIENTED_EDGE('',*,*,#4487,.F.);
#4503=ORIENTED_EDGE('',*,*,#2368,.T.);
#4504=EDGE_LOOP('',(#4500,#4501,#4502,#4503));
#4505=FACE_BOUND('',#4504,.T.);
#4506=ADVANCED_FACE('F835',(#4505),#4499,.F.);
#4507=CLOSED_SHELL('',(#1198,#2378,#2397,#2416,#2428,#2435,#2454,#2472,#2480,#2492,#2520,#2532,
#2552,#2572,#2600,#2628,#2648,#2660,#2680,#2700,#2720,#2748,#2760,#2772,#2784,#2796,#2815,#2834,
#2846,#2853,#2872,#2890,#2898,#2910,#2929,#2948,#2960,#2967,#2986,#3004,#3012,#3024,#3043,#3062,
#3074,#3081,#3100,#3118,#3126,#3138,#3157,#3176,#3188,#3195,#3214,#3232,#3240,#3252,#3271,#3290,
#3302,#3309,#3328,#3346,#3354,#3366,#3385,#3404,#3416,#3423,#3442,#3460,#3468,#3480,#3499,#3518,
#3530,#3537,#3556,#3574,#3582,#3594,#3613,#3632,#3644,#3651,#3670,#3688,#3696,#3708,#3727,#3746,
#3758,#3765,#3784,#3802,#3810,#3822,#3841,#3860,#3872,#3879,#3898,#3916,#3924,#3936,#3955,#3974,
#3986,#3993,#4012,#4030,#4038,#4050,#4069,#4088,#4100,#4107,#4126,#4144,#4152,#4164,#4183,#4202,
#4214,#4221,#4240,#4258,#4266,#4278,#4297,#4316,#4328,#4335,#4354,#4372,#4380,#4392,#4411,#4430,
#4442,#4449,#4468,#4486,#4494,#4506));
#4508=MANIFOLD_SOLID_BREP('B2',#4507);
#4509=ADVANCED_BREP_SHAPE_REPRESENTATION('',(#18,#4508),#14);
#4510=SHAPE_DEFINITION_REPRESENTATION(#9,#4509);
ENDSEC;
END-ISO-10303-21;
